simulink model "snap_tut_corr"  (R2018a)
settings: Solver=VariableStepDiscrete  StartTime=0.0  StopTime=100  RelTol=1e-3
undefined symbols (not defined in the file): Area, behavioral, Behavioral, Bit, Both, BRAM, bram, c, core, d, Falling, getfield, hamming, hex2dec, led, Location, logic, Lower, Minimum_Area, out, quant0, quant1, quant2, reg, repmat, Rising, ROACH, ROACH2, SNAP, Speed, sync_in, Truncate, Unsigned, Upper, Width, Wrap, xc7k160t
libraries: xbsIndex_r4 x17901, casper_library_misc x29, xbsReplacements_r4 x20, casper_library_delays x14, xps_library x5
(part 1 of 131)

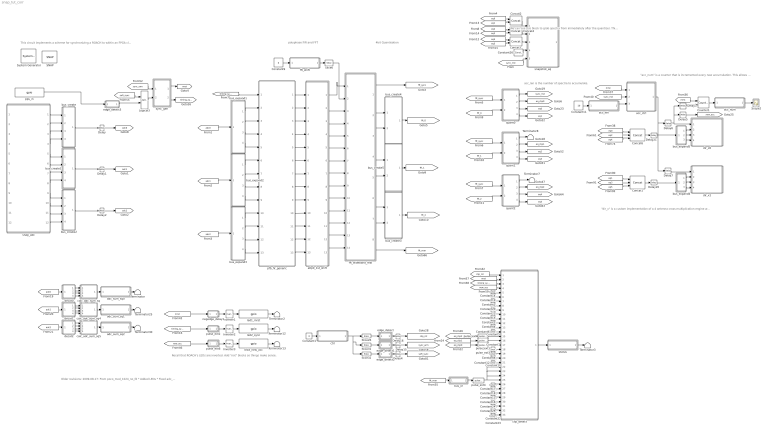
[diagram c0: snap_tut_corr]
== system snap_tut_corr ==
  note: We can use this block to grab spectra from immediately after the quantizer. This will help determine what the correct quantizer EQ coefficients are
  note: This circuit implements a scheme for synchronizing a ROACH to within an FPGA clock of a second boundary using an external 1 pulse-per-second device. * A sync_arm command will cause the sync_gen to stop issuing sync pulses. * It will then ignore the next input trigger (1PPS), while sync is flushed through the DSP pipeline. * It will then lock onto the next trigger (1PPS) and issue syncs thereafter every sync_period clocks. * Need a multiple of (pfb_fir taps*LCM(FFT reorder orders) *fft bins/parallel inputs =) (4 * LCM(2,2,2,9) * 1024 / 4) = 18432) for sync_period for simulation * Trigger off either ADC's 1PPS inputs
  note: polyphase FIR and FFT
  note: "dir_x" is a custom implementation of a 4 antenna cross-multiplication engine which uses a multiplication core for each auto- and cross-correlation. Some BRAM space is wasted in this 1024 channel compile because the minimum shared BRAM size is 2048.
  note: "acc_num" is a counter that is incremented every new accumulation. This allows a computer to know when a new accumulation is available.
  note: acc_len is the number of spectra to accumulate.
  note: 4bit Quantisation
  note: Recall that ROACH's LEDs are inverted. Add "not" blocks so things make sense.
  note: Older revisions: 2009-08-17: From poco_mod_1024_no_fd * Added LEDs * Fixed adc_levels 2009-08-18: r310 * Changed dir_x numbering scheme * mods to adc_levels * added status register * EQ now per channel 2010-08-14: r313 * adc_sum_sq copied from kat-7 feng 2010-08-16: r314: * tidyup for workshop 2012-05-09: r315: * replaced FFT and PFB_FIR with new library ones * software register replacement 2013-08-16: r316: Updated for workshop. Ran DM's update_casper_blocks script Replaced all cross-multiplication modules with dsp48_cmults Replaced deprecated snap blocks Replaced FFT and FIR blocks for combined multi-input blocks.
  " System Generator" : xbsIndex_r4/ System Generator  Tag=genX  xilinxfamily=kintex7  part=xc7k160t  speed=-2  package=ffg676  synthesis_tool=XST  clock_wrapper=Clock Enables  directory=/home/jackh/mergeymcmergeface/tutorials_devel2/vivado/snap/tut_corr/snap_tut_corr/sysgen  proj_type=Vivado  Synth_file=Vivado Synthesis Defaults  Impl_file=Vivado Implementation Defaults  testbench=off  simulink_period=1  sysclk_period=5  dcm_input_clock_period=10  incr_netlist=off  trim_vbits=Everywhere in SubSystem  dbl_ovrd=According to Block Masks  core_generation=According to Block Masks  run_coregen=off  deprecated_control=off  eval_field=0  block_type=sysgen
  Concat1 : xbsIndex_r4/Concat  num_inputs=3  dbl_ovrd=off  block_type=concat
  Concat2 : xbsIndex_r4/Concat  num_inputs=2  dbl_ovrd=off  block_type=concat
  Concat3 : xbsIndex_r4/Concat  num_inputs=2  dbl_ovrd=off  block_type=concat
  Concat4 : xbsIndex_r4/Concat  num_inputs=2  dbl_ovrd=off  block_type=concat
  Concat6 : xbsIndex_r4/Concat  num_inputs=3  dbl_ovrd=off  block_type=concat
  Constant1 : Constant  Value=0
  Constant{2..8,10,12..25} (22 alike) : xbsIndex_r4/Constant  const=0  gui_display_data_type=Fixed-point  arith_type=Boolean  n_bits=1  bin_pt=0  preci_type=Single  exp_width=8  frac_width=24  explicit_period=on  period=1  equ=P=C  opselect=C  inp2=PCIN>>17  opr=+  inp1=P  carry=CIN  dbl_ovrd=off  block_type=constant
  Constant11 : Constant  Value=10
  Constant26 : xbsIndex_r4/Constant  const=0  gui_display_data_type=Boolean  arith_type=Boolean  n_bits=32  bin_pt=0  preci_type=Single  exp_width=8  frac_width=24  explicit_period=on  period=1  equ=P=C  opselect=C  inp2=PCIN>>17  opr=+  inp1=P  carry=CIN  dbl_ovrd=off  block_type=constant
  Constant9 : Constant  Value=0
  Counter1 : xbsIndex_r4/Counter  cnt_type=Free Running  cnt_to=Inf  operation=Up  start_count=0  cnt_by_val=1  arith_type=Unsigned  n_bits=32  bin_pt=0  load_pin=off  rst=on  en=on  explicit_period=off  period=1  use_behavioral_HDL=off  implementation=Fabric  use_rpm=on  dbl_ovrd=off  block_type=counter
  Delay{,1..2,4..7,15..16} (9 alike) : xbsIndex_r4/Delay  rst=off  infoeditControl=Selection of Reset will increase slice count due to use of real FFs and instead of SRLs  en=off  latency=1  reg_retiming=on  dbl_ovrd=off  block_type=delay
  Delay20 : xbsIndex_r4/Delay  rst=off  infoeditControl=Selection of Reset will increase slice count due to use of real FFs and instead of SRLs  en=off  latency=2  reg_retiming=on  dbl_ovrd=off  block_type=delay
  Delay21 : xbsIndex_r4/Delay  rst=off  infoeditControl=Selection of Reset will increase slice count due to use of real FFs and instead of SRLs  en=off  latency=2  reg_retiming=on  dbl_ovrd=off  block_type=delay
  Delay3 : xbsIndex_r4/Delay  rst=off  infoeditControl=Selection of Reset will increase slice count due to use of real FFs and instead of SRLs  en=off  latency=2  reg_retiming=on  dbl_ovrd=off  block_type=delay
  Inverter1 : xbsIndex_r4/Inverter  en=off  latency=1  dbl_ovrd=off  block_type=inv
  Inverter2 : xbsIndex_r4/Inverter  en=off  latency=1  dbl_ovrd=off  block_type=inv
  Inverter3 : xbsIndex_r4/Inverter  en=off  latency=1  dbl_ovrd=off  block_type=inv
  Logical3 : xbsIndex_r4/Logical  logical_function=OR  inputs=2  en=off  latency=0  precision=Full  arith_type=Unsigned  n_bits=16  bin_pt=0  align_bp=on  dbl_ovrd=off  block_type=logical
  SNAP : xps_library/Platforms/SNAP  Tag=xps:xsg  hw_sys=SNAP:xc7k160t  clk_src=adc0_clk  clk_rate=200  use_microblaze=off  sample_period=1  synthesis_tool=XST
  Scope2 : Scope
  Slice26 : xbsIndex_r4/Slice  nbits=1  boolean_output=on  mode=Lower Bit Location + Width  bit1=0  base1=MSB of Input  bit0=16  base0=LSB of Input  dbl_ovrd=off  block_type=slice
  Slice31 : xbsIndex_r4/Slice  nbits=1  boolean_output=on  mode=Lower Bit Location + Width  bit1=0  base1=MSB of Input  bit0=17  base0=LSB of Input  dbl_ovrd=off  block_type=slice
  Slice32 : xbsIndex_r4/Slice  nbits=1  boolean_output=on  mode=Lower Bit Location + Width  bit1=0  base1=MSB of Input  bit0=18  base0=LSB of Input  dbl_ovrd=off  block_type=slice
  Slice6 : xbsIndex_r4/Slice  nbits=11  boolean_output=off  mode=Lower Bit Location + Width  bit1=0  base1=MSB of Input  bit0=0  base0=LSB of Input  dbl_ovrd=off  block_type=slice
  Terminator{,2..3,7..8,12..13,25,30} (9 alike) : Terminator
  a0p0_1st_shift : Subsystem  mask{shift=1, latency=0}
      mask prompts: shift "Number bits to shift right by"; latency "Shift latency"
  acc_ctrl : Subsystem  mask{chan_bits=9}
      mask prompts: chan_bits "Vector length (2^?)"
  acc_len : Subsystem  Tag=xps:sw_reg  AncestorBlock=xps_library/Memory/software_register  mask(swreg){io_dir=From Processor, io_delay=0, init_val=0, sample_period=1, names=reg, bitwidths=32, bin_pts=0, arith_types=0, sim_port=on, show_format=on}
      mask prompts: io_dir "I/O direction"; io_delay "I/O delay"; init_val "Initial Value"; sample_period "Sample period"; names "Bitfield names [msb...lsb]"; bitwidths "Bitfield widths"; bin_pts "Bitfield binary pts"; arith_types "Bitfield types, ufix=0, fix=1, bool=2"; sim_port "Provide sim input/output?"; show_format "Print format string?"
      mask help: A 32-bit software-accessible register. Can be divided into bitfields of varying widths and types using the fields in the block mask.
      mask init:
      | swreg_init(gcb)
  acc_num : Subsystem  Tag=xps:sw_reg  AncestorBlock=xps_library/Memory/software_register  mask(swreg){io_dir=To Processor, io_delay=0, init_val=0, sample_period=1, names=reg, bitwidths=32, bin_pts=0, arith_types=0, sim_port=on, show_format=on}
      mask prompts: io_dir "I/O direction"; io_delay "I/O delay"; init_val "Initial Value"; sample_period "Sample period"; names "Bitfield names [msb...lsb]"; bitwidths "Bitfield widths"; bin_pts "Bitfield binary pts"; arith_types "Bitfield types, ufix=0, fix=1, bool=2"; sim_port "Provide sim input/output?"; show_format "Print format string?"
      mask help: A 32-bit software-accessible register. Can be divided into bitfields of varying widths and types using the fields in the block mask.
      mask init:
      | swreg_init(gcb)
  adc_sum_sq0 : Subsystem  Tag=xps:sw_reg  AncestorBlock=xps_library/Memory/software_register  mask(swreg){io_dir=To Processor, io_delay=0, init_val=0, sample_period=1, names=reg, bitwidths=32, bin_pts=0, arith_types=0, sim_port=on, show_format=on}
      mask prompts: io_dir "I/O direction"; io_delay "I/O delay"; init_val "Initial Value"; sample_period "Sample period"; names "Bitfield names [msb...lsb]"; bitwidths "Bitfield widths"; bin_pts "Bitfield binary pts"; arith_types "Bitfield types, ufix=0, fix=1, bool=2"; sim_port "Provide sim input/output?"; show_format "Print format string?"
      mask help: A 32-bit software-accessible register. Can be divided into bitfields of varying widths and types using the fields in the block mask.
      mask init:
      | swreg_init(gcb)
  adc_sum_sq1 : Subsystem  Tag=xps:sw_reg  AncestorBlock=xps_library/Memory/software_register  mask(swreg){io_dir=To Processor, io_delay=0, init_val=0, sample_period=1, names=reg, bitwidths=32, bin_pts=0, arith_types=0, sim_port=on, show_format=on}
      mask prompts: io_dir "I/O direction"; io_delay "I/O delay"; init_val "Initial Value"; sample_period "Sample period"; names "Bitfield names [msb...lsb]"; bitwidths "Bitfield widths"; bin_pts "Bitfield binary pts"; arith_types "Bitfield types, ufix=0, fix=1, bool=2"; sim_port "Provide sim input/output?"; show_format "Print format string?"
      mask help: A 32-bit software-accessible register. Can be divided into bitfields of varying widths and types using the fields in the block mask.
      mask init:
      | swreg_init(gcb)
  adc_sum_sq2 : Subsystem  Tag=xps:sw_reg  AncestorBlock=xps_library/Memory/software_register  mask(swreg){io_dir=To Processor, io_delay=0, init_val=0, sample_period=1, names=reg, bitwidths=32, bin_pts=0, arith_types=0, sim_port=on, show_format=on}
      mask prompts: io_dir "I/O direction"; io_delay "I/O delay"; init_val "Initial Value"; sample_period "Sample period"; names "Bitfield names [msb...lsb]"; bitwidths "Bitfield widths"; bin_pts "Bitfield binary pts"; arith_types "Bitfield types, ufix=0, fix=1, bool=2"; sim_port "Provide sim input/output?"; show_format "Print format string?"
      mask help: A 32-bit software-accessible register. Can be divided into bitfields of varying widths and types using the fields in the block mask.
      mask init:
      | swreg_init(gcb)
  bus_create : Subsystem  AncestorBlock=casper_library_flow_control/bus_create  mask(bus_create){inputNum=4}
      mask prompts: inputNum "Number of inputs:"
      mask init:
      | bus_create_init(gcb,...
      |     'inputNum', inputNum);
  bus_create1 : Subsystem  AncestorBlock=casper_library_flow_control/bus_create  mask(bus_create){inputNum=4}
      mask prompts: inputNum "Number of inputs:"
      mask init:
      | bus_create_init(gcb,...
      |     'inputNum', inputNum);
  bus_create2 : Subsystem  AncestorBlock=casper_library_flow_control/bus_create  mask(bus_create){inputNum=4}
      mask prompts: inputNum "Number of inputs:"
      mask init:
      | bus_create_init(gcb,...
      |     'inputNum', inputNum);
  bus_create3 : Subsystem  AncestorBlock=casper_library_flow_control/bus_create  mask(bus_create){inputNum=2}
      mask prompts: inputNum "Number of inputs:"
      mask init:
      | bus_create_init(gcb,...
      |     'inputNum', inputNum);
  bus_create4 : Subsystem  AncestorBlock=casper_library_flow_control/bus_create  mask(bus_create){inputNum=2}
      mask prompts: inputNum "Number of inputs:"
      mask init:
      | bus_create_init(gcb,...
      |     'inputNum', inputNum);
  bus_create5 : Subsystem  AncestorBlock=casper_library_flow_control/bus_create  mask(bus_create){inputNum=2}
      mask prompts: inputNum "Number of inputs:"
      mask init:
      | bus_create_init(gcb,...
      |     'inputNum', inputNum);
  bus_expand1 : Subsystem  AncestorBlock=casper_library_flow_control/bus_expand  mask(bus_expand){mode=divisions of equal size, outputNum=4, outputWidth=8, outputBinaryPt=7, outputArithmeticType=1, show_format=off, outputToWorkspace=off, variablePrefix=out, outputToModelAsWell=on}
      mask prompts: outputNum "Number of outputs:"; outputWidth "Output width:"; outputBinaryPt "Output binary point position:"; outputArithmeticType "Output arithmetic type (ufix=0, fix=1, bool=2):"; show_format "Print format string?"; outputToWorkspace "Output to workspace?"; variablePrefix "Variable name prefix:"; outputToModelAsWell "Output to model as well?"
      mask help: Expands a 'bus' made using a bus_create or Xilinx concat block. The input will be divided into the specified number of outputs with the specified arithmetic types. Divisions are made from most significant bit.
      mask init:
      | bus_expand_init(gcb,...
      |     'mode', mode, ...
      |     'outputNum', outputNum, ...
      |     'outputWidth', outputWidth, ...
      |     'outputBinaryPt', outputBinaryPt, ...
      |     'outputArithmeticType', outputArithmeticType, ...
      |     'show_format', show_format, ...
      |     'outputToWorkspace', outputToWorkspace, ...
      |     'variablePrefix', variablePrefix, ...
      |     'outputToModelAsWell', outputToModelAsWell);
  bus_expand2 : Subsystem  AncestorBlock=casper_library_flow_control/bus_expand  mask(bus_expand){mode=divisions of equal size, outputNum=4, outputWidth=8, outputBinaryPt=7, outputArithmeticType=1, show_format=off, outputToWorkspace=off, variablePrefix=out, outputToModelAsWell=on}
      mask prompts: outputNum "Number of outputs:"; outputWidth "Output width:"; outputBinaryPt "Output binary point position:"; outputArithmeticType "Output arithmetic type (ufix=0, fix=1, bool=2):"; show_format "Print format string?"; outputToWorkspace "Output to workspace?"; variablePrefix "Variable name prefix:"; outputToModelAsWell "Output to model as well?"
      mask help: Expands a 'bus' made using a bus_create or Xilinx concat block. The input will be divided into the specified number of outputs with the specified arithmetic types. Divisions are made from most significant bit.
      mask init:
      | bus_expand_init(gcb,...
      |     'mode', mode, ...
      |     'outputNum', outputNum, ...
      |     'outputWidth', outputWidth, ...
      |     'outputBinaryPt', outputBinaryPt, ...
      |     'outputArithmeticType', outputArithmeticType, ...
      |     'show_format', show_format, ...
      |     'outputToWorkspace', outputToWorkspace, ...
      |     'variablePrefix', variablePrefix, ...
      |     'outputToModelAsWell', outputToModelAsWell);
  bus_expand3 : Subsystem  AncestorBlock=casper_library_flow_control/bus_expand  mask(bus_expand){mode=divisions of equal size, outputNum=4, outputWidth=8, outputBinaryPt=7, outputArithmeticType=1, show_format=off, outputToWorkspace=off, variablePrefix=out, outputToModelAsWell=on}
      mask prompts: outputNum "Number of outputs:"; outputWidth "Output width:"; outputBinaryPt "Output binary point position:"; outputArithmeticType "Output arithmetic type (ufix=0, fix=1, bool=2):"; show_format "Print format string?"; outputToWorkspace "Output to workspace?"; variablePrefix "Variable name prefix:"; outputToModelAsWell "Output to model as well?"
      mask help: Expands a 'bus' made using a bus_create or Xilinx concat block. The input will be divided into the specified number of outputs with the specified arithmetic types. Divisions are made from most significant bit.
      mask init:
      | bus_expand_init(gcb,...
      |     'mode', mode, ...
      |     'outputNum', outputNum, ...
      |     'outputWidth', outputWidth, ...
      |     'outputBinaryPt', outputBinaryPt, ...
      |     'outputArithmeticType', outputArithmeticType, ...
      |     'show_format', show_format, ...
      |     'outputToWorkspace', outputToWorkspace, ...
      |     'variablePrefix', variablePrefix, ...
      |     'outputToModelAsWell', outputToModelAsWell);
  bus_expand4 : Subsystem  AncestorBlock=casper_library_flow_control/bus_expand  mask(bus_expand){mode=divisions of equal size, outputNum=3, outputWidth=8, outputBinaryPt=0, outputArithmeticType=0, show_format=off, outputToWorkspace=off, variablePrefix=out, outputToModelAsWell=on}
      mask prompts: outputNum "Number of outputs:"; outputWidth "Output width:"; outputBinaryPt "Output binary point position:"; outputArithmeticType "Output arithmetic type (ufix=0, fix=1, bool=2):"; show_format "Print format string?"; outputToWorkspace "Output to workspace?"; variablePrefix "Variable name prefix:"; outputToModelAsWell "Output to model as well?"
      mask help: Expands a 'bus' made using a bus_create or Xilinx concat block. The input will be divided into the specified number of outputs with the specified arithmetic types. Divisions are made from most significant bit.
      mask init:
      | bus_expand_init(gcb,...
      |     'mode', mode, ...
      |     'outputNum', outputNum, ...
      |     'outputWidth', outputWidth, ...
      |     'outputBinaryPt', outputBinaryPt, ...
      |     'outputArithmeticType', outputArithmeticType, ...
      |     'show_format', show_format, ...
      |     'outputToWorkspace', outputToWorkspace, ...
      |     'variablePrefix', variablePrefix, ...
      |     'outputToModelAsWell', outputToModelAsWell);
  bus_expand5 : Subsystem  AncestorBlock=casper_library_flow_control/bus_expand  mask(bus_expand){mode=divisions of equal size, outputNum=3, outputWidth=8, outputBinaryPt=0, outputArithmeticType=0, show_format=off, outputToWorkspace=off, variablePrefix=out, outputToModelAsWell=on}
      mask prompts: outputNum "Number of outputs:"; outputWidth "Output width:"; outputBinaryPt "Output binary point position:"; outputArithmeticType "Output arithmetic type (ufix=0, fix=1, bool=2):"; show_format "Print format string?"; outputToWorkspace "Output to workspace?"; variablePrefix "Variable name prefix:"; outputToModelAsWell "Output to model as well?"
      mask help: Expands a 'bus' made using a bus_create or Xilinx concat block. The input will be divided into the specified number of outputs with the specified arithmetic types. Divisions are made from most significant bit.
      mask init:
      | bus_expand_init(gcb,...
      |     'mode', mode, ...
      |     'outputNum', outputNum, ...
      |     'outputWidth', outputWidth, ...
      |     'outputBinaryPt', outputBinaryPt, ...
      |     'outputArithmeticType', outputArithmeticType, ...
      |     'show_format', show_format, ...
      |     'outputToWorkspace', outputToWorkspace, ...
      |     'variablePrefix', variablePrefix, ...
      |     'outputToModelAsWell', outputToModelAsWell);
  bus_or : Subsystem
  calc_adc_sum_sq : Subsystem
  calc_adc_sum_sq4 : Subsystem
  calc_adc_sum_sq5 : Subsystem
  clip_detect : Subsystem
  ctrl : Subsystem  Tag=xps:sw_reg  AncestorBlock=xps_library/Memory/software_register  mask(swreg){io_dir=From Processor, io_delay=0, init_val=0, sample_period=1, names=reg, bitwidths=32, bin_pts=0, arith_types=0, sim_port=on, show_format=on}
      mask prompts: io_dir "I/O direction"; io_delay "I/O delay"; init_val "Initial Value"; sample_period "Sample period"; names "Bitfield names [msb...lsb]"; bitwidths "Bitfield widths"; bin_pts "Bitfield binary pts"; arith_types "Bitfield types, ufix=0, fix=1, bool=2"; sim_port "Provide sim input/output?"; show_format "Print format string?"
      mask help: A 32-bit software-accessible register. Can be divided into bitfields of varying widths and types using the fields in the block mask.
      mask init:
      | swreg_init(gcb)
  decat0 : Subsystem
  decat1 : Subsystem
  decat2 : Subsystem
  dir_x0 : Subsystem  mask{n_chans=512}
      mask prompts: n_chans "Number of Channels"
  dir_x1 : Subsystem  mask{n_chans=512}
      mask prompts: n_chans "Number of Channels"
  edge_detect : Subsystem  AncestorBlock=casper_library_misc/edge_detect  mask(edge_detect){edge=Rising, polarity=Active High, x_in=[0 0.08 0.08 0.16 0.16 0.24 0.24 0.32 0.32 0.4], y_in=[-1 -1  1  1  1  1  1  1  1  1], x_out=[0.6 0.68 0.68 0.76 0.76 0.84 0.84 0.92 0.92 1], y_out=[-1 -1  1  1 -1 -1 -1 -1 -1 -1]}
      mask prompts: edge "Edge Type"; polarity "Output Polarity"; x_in "Input X Positions"; y_in "Input Y Positions"; x_out "Output X Positions"; y_out "Output Y Positions"
      mask help: Output is active for one-cycle after each edge of the specified type (i.e. rising, falling or both).
      mask init:
      | edge_detect_init(gcb,...
      |     'edge',edge,...
      |     'polarity',polarity,...
      |     'x_in',x_in,...
      |     'x_out',x_out,...
      |     'y_in',y_in,...
      |     'y_out',y_out);
      | 
      | x_in_num=str2num(getfield(getfield(get_param(gcb,'UserData'),'parameters'),'x_in'));
      | x_out_num=str2num(getfield(getfield(get_param(gcb,'UserData'),'parameters'),'x_out'));
      | y_in_num=str2num(getfield(getfield(get_param(gcb,'UserData'),'parameters'),'y_in'));
      | y_out_num=str2num(getfield(getfield(get_param(gcb,'UserData'),'parameters'),'y_out'));
  edge_detect1 : Subsystem  AncestorBlock=casper_library_misc/edge_detect  mask(edge_detect){edge=Rising, polarity=Active High, x_in=[0 0.08 0.08 0.16 0.16 0.24 0.24 0.32 0.32 0.4], y_in=[-1 -1  1  1  1  1  1  1  1  1], x_out=[0.6 0.68 0.68 0.76 0.76 0.84 0.84 0.92 0.92 1], y_out=[-1 -1  1  1 -1 -1 -1 -1 -1 -1]}
      mask prompts: edge "Edge Type"; polarity "Output Polarity"; x_in "Input X Positions"; y_in "Input Y Positions"; x_out "Output X Positions"; y_out "Output Y Positions"
      mask help: Output is active for one-cycle after each edge of the specified type (i.e. rising, falling or both).
      mask init:
      | edge_detect_init(gcb,...
      |     'edge',edge,...
      |     'polarity',polarity,...
      |     'x_in',x_in,...
      |     'x_out',x_out,...
      |     'y_in',y_in,...
      |     'y_out',y_out);
      | 
      | x_in_num=str2num(getfield(getfield(get_param(gcb,'UserData'),'parameters'),'x_in'));
      | x_out_num=str2num(getfield(getfield(get_param(gcb,'UserData'),'parameters'),'x_out'));
      | y_in_num=str2num(getfield(getfield(get_param(gcb,'UserData'),'parameters'),'y_in'));
      | y_out_num=str2num(getfield(getfield(get_param(gcb,'UserData'),'parameters'),'y_out'));
  edge_detect2 : Subsystem  AncestorBlock=casper_library_misc/edge_detect  mask(edge_detect){edge=Rising, polarity=Active High, x_in=[0 0.08 0.08 0.16 0.16 0.24 0.24 0.32 0.32 0.4], y_in=[-1 -1  1  1  1  1  1  1  1  1], x_out=[0.6 0.68 0.68 0.76 0.76 0.84 0.84 0.92 0.92 1], y_out=[-1 -1  1  1 -1 -1 -1 -1 -1 -1]}
      mask prompts: edge "Edge Type"; polarity "Output Polarity"; x_in "Input X Positions"; y_in "Input Y Positions"; x_out "Output X Positions"; y_out "Output Y Positions"
      mask help: Output is active for one-cycle after each edge of the specified type (i.e. rising, falling or both).
      mask init:
      | edge_detect_init(gcb,...
      |     'edge',edge,...
      |     'polarity',polarity,...
      |     'x_in',x_in,...
      |     'x_out',x_out,...
      |     'y_in',y_in,...
      |     'y_out',y_out);
      | 
      | x_in_num=str2num(getfield(getfield(get_param(gcb,'UserData'),'parameters'),'x_in'));
      | x_out_num=str2num(getfield(getfield(get_param(gcb,'UserData'),'parameters'),'x_out'));
      | y_in_num=str2num(getfield(getfield(get_param(gcb,'UserData'),'parameters'),'y_in'));
      | y_out_num=str2num(getfield(getfield(get_param(gcb,'UserData'),'parameters'),'y_out'));
  edge_detect3 : Subsystem  AncestorBlock=casper_library_misc/edge_detect  mask(edge_detect){edge=Rising, polarity=Active High, x_in=[0 0.08 0.08 0.16 0.16 0.24 0.24 0.32 0.32 0.4], y_in=[-1 -1  1  1  1  1  1  1  1  1], x_out=[0.6 0.68 0.68 0.76 0.76 0.84 0.84 0.92 0.92 1], y_out=[-1 -1  1  1 -1 -1 -1 -1 -1 -1]}
      mask prompts: edge "Edge Type"; polarity "Output Polarity"; x_in "Input X Positions"; y_in "Input Y Positions"; x_out "Output X Positions"; y_out "Output Y Positions"
      mask help: Output is active for one-cycle after each edge of the specified type (i.e. rising, falling or both).
      mask init:
      | edge_detect_init(gcb,...
      |     'edge',edge,...
      |     'polarity',polarity,...
      |     'x_in',x_in,...
      |     'x_out',x_out,...
      |     'y_in',y_in,...
      |     'y_out',y_out);
      | 
      | x_in_num=str2num(getfield(getfield(get_param(gcb,'UserData'),'parameters'),'x_in'));
      | x_out_num=str2num(getfield(getfield(get_param(gcb,'UserData'),'parameters'),'x_out'));
      | y_in_num=str2num(getfield(getfield(get_param(gcb,'UserData'),'parameters'),'y_in'));
      | y_out_num=str2num(getfield(getfield(get_param(gcb,'UserData'),'parameters'),'y_out'));
  fft_shift : Subsystem  Tag=xps:sw_reg  AncestorBlock=xps_library/Memory/software_register  mask(swreg){io_dir=From Processor, io_delay=0, init_val=0, sample_period=1, names=reg, bitwidths=32, bin_pts=0, arith_types=0, sim_port=on, show_format=on}
      mask prompts: io_dir "I/O direction"; io_delay "I/O delay"; init_val "Initial Value"; sample_period "Sample period"; names "Bitfield names [msb...lsb]"; bitwidths "Bitfield widths"; bin_pts "Bitfield binary pts"; arith_types "Bitfield types, ufix=0, fix=1, bool=2"; sim_port "Provide sim input/output?"; show_format "Print format string?"
      mask help: A 32-bit software-accessible register. Can be divided into bitfields of varying widths and types using the fields in the block mask.
      mask init:
      | swreg_init(gcb)
  fft_wideband_real : Subsystem  Tag=casper:fft_wideband_real  AncestorBlock=casper_library_ffts/fft_wideband_real  mask(fft_wideband_real){n_streams=3, FFTSize=11, n_inputs=2, input_bit_width=18, bin_pt_in=17, coeff_bit_width=18, unscramble=on, async=off, floating_point=off, float_type=single, exp_width=8, frac_width=24, add_latency=1, mult_latency=3, bram_latency=3, conv_latency=1, input_latency=0, biplex_direct_latency=0, add_pipe_latency=0, mult_pipe_latency=0, quantization=Round  (unbiased: Even Values), overflow=Wrap, delays_bit_limit=7, coeffs_bit_limit=7, coeff_sharing=off, coeff_decimation=off, coeff_generation=off, cal_bits=1, n_bits_rotation=25, mult_spec=2, max_fanout=8, bitgrowth=off, max_bits=19, hardcode_shifts=off, shift_schedule=[], dsp48_adders=off}
      mask prompts: n_streams "Number simultaneous streams"; FFTSize "Size of FFT: (2^? pts)"; n_inputs "Number of Simultaneous Inputs: (2^?)"; input_bit_width "Input Bit Width"; bin_pt_in "Input binary point"; coeff_bit_width "Coefficient Bit Width"; unscramble "Unscramble output (ie, put channels in canonical order)"; async "Asynchronous operation"; floating_point "floating point"; float_type "float type"; exp_width "exponent width"; frac_width "fraction width"; add_latency "Add Latency"; mult_latency "Mult Latency"; bram_latency "BRAM Latency"; conv_latency "Convert Latency"; input_latency "Input Latency"; biplex_direct_latency "Latency between biplexes and fft_direct"; add_pipe_latency "Add Interface Pipeline Latency"; mult_pipe_latency "CMult Pipeline Latency"; quantization "Quantization Behavior"; overflow "Overflow Behavior"; delays_bit_limit "Number bits above which to store stage's delays in BRAM (2^? bits)"; coeffs_bit_limit "Number bits above which to store stage's coefficients in BRAM (2^? bits)"; coeff_sharing "BRAM sharing in coeff storage"; coeff_decimation "Store a fraction of coeff factors where useful"; coeff_generation "Generate coeffs with multipliers where useful"; cal_bits "Number calibration locations when generating coeffs (2^?)"; n_bits_rotation "Feedback rotation vector resolution"; mult_spec "Multiplier impl. (0=core, 1=embedded, 2=behavioural) (left=1st stage, or just one value)"; max_fanout "Maximum fanout"; bitgrowth "Bitgrowth instead of shifting"; max_bits "Max bits to grow to"; hardcode_shifts "Hardcode shift schedule"; shift_schedule "Shift schedule"; dsp48_adders "DSP48 adders in butterfly"
      mask help: A real-sampled wideband FFT.
      mask init:
      | fft_wideband_real_init(gcb, ...
      |     'n_streams', n_streams, ...
      |     'FFTSize', FFTSize, ...
      |     'n_inputs', n_inputs, ...
      |     'input_bit_width', input_bit_width, ...
      |     'bin_pt_in', bin_pt_in, ...
      |     'coeff_bit_width', coeff_bit_width, ...
      |     'floating_point', floating_point, ...
      |     'float_type', float_type, ...
      |     'exp_width', exp_width, ...
      |     'frac_width', frac_width, ...
      |     'unscramble', unscramble, ...
      |     'async', async, ...
      |     'add_latency', add_latency, ...
      |     'mult_latency', mult_latency, ...
      |     'bram_latency', bram_latency, ...
      |     'conv_latency', conv_latency, ...
      |     'input_latency', input_latency, ...
      |     'add_pipe_latency', add_pipe_latency, ...
      |     'mult_pipe_latency', mult_pipe_latency, ...
      |     'biplex_direct_latency', biplex_direct_latency, ...
      |     'quantization', quantization, ...
      |     'overflow', overflow, ...
      |     'delays_bit_limit', delays_bit_limit, ...
      |     'coeffs_bit_limit', coeffs_bit_limit, ...
      |     'coeff_sharing', coeff_sharing, ...
      |     'coeff_decimation', coeff_decimation, ...
      |     'coeff_generation', coeff_generation, ...
      |     'cal_bits', cal_bits, ...
      |     'n_bits_rotation', n_bits_rotation, ...
      |     'max_fanout', max_fanout, ...   
      |     'mult_spec', mult_spec, ...
      |     'bitgrowth', bitgrowth, ...
      |     'max_bits', max_bits, ...
      |     'hardcode_shifts', hardcode_shifts, ...
      |     'shift_schedule', shift_schedule, ...
      |     'dsp48_adders', dsp48_adders);
  led1_mrst : xps_library/IO/gpio  Tag=xps:gpio  io_group_params_forwarded=on  io_group=ROACH:led  io_group_real=led  io_group_custom=0  io_dir=out  arith_type=Boolean  bitwidth=1  bin_pt=0  bit_index=1  sample_period=1  use_single_ended=off  use_ddr=off  reg_iob=on  reg_clk_phase=0  termination=None
  led2_sync : xps_library/IO/gpio  Tag=xps:gpio  io_group_params_forwarded=on  io_group=ROACH:led  io_group_real=led  io_group_custom=0  io_dir=out  arith_type=Boolean  bitwidth=1  bin_pt=0  bit_index=2  sample_period=1  use_single_ended=off  use_ddr=off  reg_iob=on  reg_clk_phase=0  termination=None
  led3_new_acc : xps_library/IO/gpio  Tag=xps:gpio  io_group_params_forwarded=on  io_group=ROACH:led  io_group_real=led  io_group_custom=0  io_dir=out  arith_type=Unsigned  bitwidth=1  bin_pt=0  bit_index=3  sample_period=1  use_single_ended=off  use_ddr=off  reg_iob=on  reg_clk_phase=0  termination=None
  negedge_delay1 : Subsystem  AncestorBlock=casper_library_misc/negedge_delay  mask(negedge_delay){pulse_len=2^24}
      mask prompts: pulse_len "Length of Pulse"
      mask help: Extends a boolean signal to be high for the specified number of clocks after the last high input (negative edge). Minimum length is 3.
      mask init:
      | bits = ceil(log2(pulse_len+1));
      | 
      | if pulse_len < 3,
      |     errordlg('Minimum length is 3.');
      | end
  pfb_fir_generic : Subsystem  Tag=casper:pfb_fir_generic  AncestorBlock=casper_library_pfbs/pfb_fir_generic  mask(pfb_fir_generic){n_streams=3, PFBSize=11, TotalTaps=4, n_inputs=2, BitWidthIn=8, BitWidthOut=18, CoeffBitWidth=18, complex=off, async=off, floating_point=off, float_type=single, frac_width=0, exp_width=0, WindowType=hamming, quantization=Round  (unbiased: Even Values), fwidth=1, coeffs_bram_optimization=Area, delays_bram_optimization=Area, add_latency=2, mult_latency=3, bram_latency=1, fan_latency=1, conv_latency=1, fixed_float_latency=0}
      mask prompts: n_streams "Number input streams?"; PFBSize "Size of PFB: (2^? pnts)"; TotalTaps "Total Number of Taps:"; n_inputs "Number of Simultaneous Inputs: (2^?)"; BitWidthIn "Input Bitwidth:"; BitWidthOut "Output Bitwidth:"; CoeffBitWidth "Coefficient Bitwidth:"; complex "Complex data inputs"; async "Asynchronous operation"; floating_point "floating point"; float_type "float type"; frac_width "fraction width"; exp_width "exponent width"; WindowType "Windowing Function:"; quantization "Quantization Behavior"; fwidth "Bin Width Scaling (normal=1)"; coeffs_bram_optimization "Coefficient BRAMs optimization"; delays_bram_optimization "Delay BRAMs optimization"; add_latency "Add Latency"; mult_latency "Mult Latency"; bram_latency "BRAM Latency"; fan_latency "Fanout Latency"; conv_latency "Convert latency"; fixed_float_latency "Fixed to float latency"
      mask init:
      | pfb_fir_generic_init(gcb, ...
      |     'n_streams', n_streams, ...
      |     'PFBSize', PFBSize, ...
      |     'TotalTaps', TotalTaps, ...
      |     'WindowType', WindowType, ...
      |     'n_inputs', n_inputs, ...
      |     'complex', complex, ...
      |     'BitWidthIn', BitWidthIn, ...
      |     'BitWidthOut', BitWidthOut, ...
      |     'CoeffBitWidth', CoeffBitWidth, ...
      |     'floating_point', floating_point, ...
      |     'float_type', float_type, ...
      |     'exp_width', exp_width, ...
      |     'frac_width', frac_width, ... 
      |     'fixed_float_latency', fixed_float_latency, ...
      |     'async', async, ...
      |     'add_latency', add_latency, ...
      |     'mult_latency', mult_latency, ...
      |     'bram_latency', bram_latency, ...
      |     'fan_latency', fan_latency, ...
      |     'conv_latency', conv_latency, ...
      |     'quantization', quantization, ...
      |     'fwidth', fwidth, ...
      |     'coeffs_bram_optimization', coeffs_bram_optimization, ...
      |     'delays_bram_optimization', delays_bram_optimization);
  pps_in : xps_library/IO/gpio  Tag=xps:gpio  io_group_params_forwarded=on  io_group=ROACH2:sync_in  io_group_real=sync_in  io_group_custom=0  io_dir=in  arith_type=Boolean  bitwidth=1  bin_pt=0  bit_index=0  sample_period=1  use_single_ended=off  use_ddr=off  reg_iob=off  reg_clk_phase=0  termination=None
  pulse_ext : casper_library_misc/pulse_ext  pulse_len=2^24
      link override Constant5: sg_icon_stat=70,32,0,1,white,blue,0,1cbef600,right,,[ ],[ ]  sg_mask_display="fprintf('','COMMENT: begin icon graphics'); patch([0 70 70 0 0 ],[0 0 32 32 0 ],[0.77 0.82 0.91 ]); plot([0 70 70 0 0 ],[0 0 32 32 0 ]); patch([26.1 31.88 35.88 39.88 43.88 35.88 30.1 26.1 ],[20.44 20.44 24.44 20.44 24.44 24.44 24.44 20.44 ],[1 1 1 ]); patch([30.1 35.88 31.88 26.1 30.1 ],[16.44 16.44 20.44 20.44 16.44 ],[0.931 0.946 0.973 ]); patch([26.1 31.88 35.88 30.1 26.1 ],[12.44 12.44 16.44 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"
  pulse_ext1 : casper_library_misc/pulse_ext  pulse_len=2^24
      link override Constant5: sg_icon_stat=70,32,0,1,white,blue,0,1cbef600,right,,[ ],[ ]  sg_mask_display="fprintf('','COMMENT: begin icon graphics'); patch([0 70 70 0 0 ],[0 0 32 32 0 ],[0.77 0.82 0.91 ]); plot([0 70 70 0 0 ],[0 0 32 32 0 ]); patch([26.1 31.88 35.88 39.88 43.88 35.88 30.1 26.1 ],[20.44 20.44 24.44 20.44 24.44 24.44 24.44 20.44 ],[1 1 1 ]); patch([30.1 35.88 31.88 26.1 30.1 ],[16.44 16.44 20.44 20.44 16.44 ],[0.931 0.946 0.973 ]); patch([26.1 31.88 35.88 30.1 26.1 ],[12.44 12.44 16.44 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"
  pulse_ext2 : Subsystem  mask{pulse_len=2^24}
      mask prompts: pulse_len "Length of Pulse"
      mask init:
      | bits = ceil(log2(pulse_len+1));
  pulse_ext3 : casper_library_misc/pulse_ext  pulse_len=2^24
      link override Constant5: sg_icon_stat=70,32,0,1,white,blue,0,1cbef600,right,,[ ],[ ]  sg_mask_display="fprintf('','COMMENT: begin icon graphics'); patch([0 70 70 0 0 ],[0 0 32 32 0 ],[0.77 0.82 0.91 ]); plot([0 70 70 0 0 ],[0 0 32 32 0 ]); patch([26.1 31.88 35.88 39.88 43.88 35.88 30.1 26.1 ],[20.44 20.44 24.44 20.44 24.44 24.44 24.44 20.44 ],[1 1 1 ]); patch([30.1 35.88 31.88 26.1 30.1 ],[16.44 16.44 20.44 20.44 16.44 ],[0.931 0.946 0.973 ]); patch([26.1 31.88 35.88 30.1 26.1 ],[12.44 12.44 16.44 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"
  pulse_ext4 : casper_library_misc/pulse_ext  pulse_len=2^24
      link override Constant5: sg_icon_stat=70,32,0,1,white,blue,0,1cbef600,right,,[ ],[ ]  sg_mask_display="fprintf('','COMMENT: begin icon graphics'); patch([0 70 70 0 0 ],[0 0 32 32 0 ],[0.77 0.82 0.91 ]); plot([0 70 70 0 0 ],[0 0 32 32 0 ]); patch([26.1 31.88 35.88 39.88 43.88 35.88 30.1 26.1 ],[20.44 20.44 24.44 20.44 24.44 24.44 24.44 20.44 ],[1 1 1 ]); patch([30.1 35.88 31.88 26.1 30.1 ],[16.44 16.44 20.44 20.44 16.44 ],[0.931 0.946 0.973 ]); patch([26.1 31.88 35.88 30.1 26.1 ],[12.44 12.44 16.44 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"
  pulse_ext6 : Subsystem  mask{pulse_len=2^24}
      mask prompts: pulse_len "Length of Pulse"
      mask init:
      | bits = ceil(log2(pulse_len+1));
  quant0 : Subsystem
  quant1 : Subsystem
  quant2 : Subsystem
  snap_adc : Subsystem  Tag=xps:snap_adc  AncestorBlock=xps_library/ADCs/snap_adc  mask(adc_snap){sample_rate=800, snap_inputs=3, adc_resolution=8}
      mask prompts: sample_rate "Sample rate (MHz)"; snap_inputs "Number of inputs per snap"; adc_resolution "Resolution of ADC (number of bit)"
      mask help: Interface to the 3 adc chips on the SNAP board. Please see Help for instructions on parameter settings
      mask init:
      | adc_snap_init(gcb);
  snapshot_eq : Subsystem  Tag=casper:bitsnap  AncestorBlock=casper_library_scopes/bitfield_snapshot  mask(bitsnap){io_names=[quant0 quant1 quant2], io_widths=[16 16 16], io_bps=[0 0 0], io_types=[0 0 0], show_format=on, snap_storage=bram, snap_dram_dimm=2, snap_dram_clock=250, snap_nsamples=10, snap_data_width=64, snap_offset=off, snap_circap=off, snap_value=off, snap_ext_arm=off, snap_ext_circ=off, snap_provide_outputs=on, snap_use_dsp48=on, snap_delay=0, extra_names=[c d], extra_widths=[30 2], extra_bps=[0 0], extra_types=[0 0]}
      mask prompts: io_names "Names [msb...lsb]"; io_widths "Bitwidths [msb...lsb]"; io_bps "Binary pts [msb...lsb]"; io_types "Data types [msb...lsb], ufix=0, fix=1, bool=2"; show_format "Print format string?"; snap_storage "Storage medium"; snap_dram_dimm "DRAM dimm"; snap_dram_clock "DRAM clock rate"; snap_nsamples "Number of Samples (2^?)"; snap_data_width "Data width"; snap_offset "Start delay support"; snap_circap "Circular capture support"; snap_value "Extra value capture support"; snap_ext_arm "External arm support"; snap_ext_circ "External circular capture support"; snap_provide_outputs "Provide outputs"; snap_use_dsp48 "Use DSP48s to implement counters"; snap_delay "Pre-snapshot delay"; extra_names "Names [msb...lsb]"; extra_widths "Widths [msb...lsb]"; extra_bps "Binary pts [msb...lsb]"; extra_types "Data types [msb...lsb], ufix=0, fix=1, bool=2"
      mask help: A wrapped snapshot block. Allows specification of inputs to a snapblock word so the toolflow can automatically set up the scope. See documentation for snapshot for explanation of parameters.
      mask init:
      | bitsnap_init(gcb);
  status : Subsystem  Tag=xps:sw_reg  AncestorBlock=xps_library/Memory/software_register  mask(swreg){io_dir=To Processor, io_delay=0, init_val=0, sample_period=1, names=reg, bitwidths=32, bin_pts=0, arith_types=0, sim_port=on, show_format=on}
      mask prompts: io_dir "I/O direction"; io_delay "I/O delay"; init_val "Initial Value"; sample_period "Sample period"; names "Bitfield names [msb...lsb]"; bitwidths "Bitfield widths"; bin_pts "Bitfield binary pts"; arith_types "Bitfield types, ufix=0, fix=1, bool=2"; sim_port "Provide sim input/output?"; show_format "Print format string?"
      mask help: A 32-bit software-accessible register. Can be divided into bitfields of varying widths and types using the fields in the block mask.
      mask init:
      | swreg_init(gcb)
  sync_gen : Subsystem  mask(sync_gen_hw){sync_period=184320000}
      mask prompts: sync_period "Sync Period"
      mask help: This circuit implements a scheme for synchronizing a design to within an FPGA clock of an external 1 pulse-per-second signal. * An arm pulse will cause the sync_gen to stop issuing sync pulses. * It will then ignore the next input trigger (1PPS), while sync is flushed through the DSP pipeline. * It will then lock onto the next trigger (1PPS) and issue syncs thereafter every sync_period clocks. * You will need a multiple of (pfb_fir taps*LCM(FFT reorder orders) *fft bins/parallel inputs). See the sync memo for further details.
      mask init:
      | sync_period_bits = ceil(log2(sync_period))
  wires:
  bus_create/1(bus_out) -> Delay/1
  sync_gen/1(mrst) -> [mrst]
  sync_gen/2(sync) -> [timing_sync]
  Logical3/1 -> sync_gen/2(pps)
  [soft_sync] -> Logical3/1
  Constant9/1 -> fft_shift/1(sim_1)
  fft_shift/1(in_reg) -> Slice6/1
  quant0/1(sync_out) -> [sync_rnd]
  quant0/3(dout0) -> [eq0]
  quant0/4(dout1) -> [eq1]
  Constant11/1 -> acc_len/1(sim_1)
  acc_len/1(in_reg) -> acc_ctrl/3(acc_len)
  Concat6/1 -> Delay21/1
  Counter1/1 -> acc_num/1(out_reg)
  acc_ctrl/1(new_acc) -> Delay6/1, Delay7/1
  [mrst] -> acc_ctrl/1(mrst)
  Delay5/1 -> [new_acc]
  [sync_rnd] -> acc_ctrl/2(sync)
  acc_num/1(sim_out) -> Scope2/1
  Delay3/1 -> Counter1/2
  [mrst] -> Counter1/1
  Delay6/1 -> dir_x0/1(new_acc), Delay3/1, Delay5/1
  [eq0] -> Concat6/1
  [eq2] -> Concat6/2
  [eq4] -> Concat6/3
  [eq1] -> Concat1/1
  [eq3] -> Concat1/2
  [eq5] -> Concat1/3
  Concat1/1 -> Delay20/1
  Delay7/1 -> dir_x1/1(new_acc)
  Constant1/1 -> ctrl/1(sim_1)
  ctrl/1(in_reg) -> Slice26/1, Slice31/1, Slice32/1
  [clip_rst] -> clip_detect/1(rst)
  Constant24/1 -> clip_detect/30(In_03)
  Constant25/1 -> clip_detect/31(In_02)
  Constant22/1 -> clip_detect/32(In_01)
  Constant23/1 -> clip_detect/33(in_lsb)
  Constant16/1 -> clip_detect/29(In_04)
  Constant17/1 -> clip_detect/26(In_07)
  Constant18/1 -> clip_detect/27(In_06)
  Constant13/1 -> clip_detect/28(In_05)
  [mrst] -> clip_detect/2(in_msb_nr)
  [timing_sync] -> clip_detect/3(In_30_nr)
  [new_acc] -> clip_detect/4(In_29_nr)
  Constant14/1 -> clip_detect/5(In_28_nr)
  Constant19/1 -> clip_detect/6(In_27_nr)
  Constant2/1 -> clip_detect/7(In_26_nr)
  Constant20/1 -> clip_detect/8(In_25_nr)
  Constant21/1 -> clip_detect/9(In_24_nr)
  Constant6/1 -> clip_detect/14(In_19)
  [eq_clip2] -> pulse_ext/1
  [eq_clip1] -> pulse_ext1/1
  [eq_clip0] -> pulse_ext3/1
  Constant7/1 -> clip_detect/18(In_15)
  Constant8/1 -> clip_detect/19(In_14)
  Constant10/1 -> clip_detect/20(In_13)
  Constant12/1 -> clip_detect/21(In_12)
  clip_detect/1(registered_out) -> status/1(out_reg)
  Slice26/1 -> edge_detect/1(in)
  [adc0] -> decat0/1(In1)
  Slice31/1 -> edge_detect1/1(in)
  Slice32/1 -> edge_detect2/1(in)
  edge_detect1/1(out) -> Delay15/1
  edge_detect/1(out) -> Delay16/1
  edge_detect2/1(out) -> Delay4/1
  [sync_arm] -> sync_gen/1(arm)
  Delay/1 -> [adc0]
  pulse_ext2/1(out) -> Inverter2/1
  [timing_sync] -> pulse_ext2/1(in)
  [mrst] -> negedge_delay1/1(in)
  pulse_ext6/1(out) -> Inverter3/1
  [new_acc] -> pulse_ext6/1(in)
  led1_mrst/1 -> Terminator2/1
  led2_sync/1 -> Terminator12/1
  led3_new_acc/1 -> Terminator13/1
  negedge_delay1/1(out) -> Inverter1/1
  status/1(sim_out) -> Terminator3/1
  Constant15/1 -> clip_detect/10(In_23)
  Constant3/1 -> clip_detect/11(In_22)
  Constant4/1 -> clip_detect/12(In_21)
  Constant5/1 -> clip_detect/13(In_20)
  quant0/2(clip_out) -> [eq_clip0]
  quant1/1(sync_out) -> Terminator8/1
  quant1/3(dout0) -> [eq2]
  quant1/4(dout1) -> [eq3]
  quant1/2(clip_out) -> [eq_clip1]
  quant2/1(sync_out) -> Terminator7/1
  quant2/3(dout0) -> [eq4]
  quant2/2(clip_out) -> [eq_clip2]
  Delay4/1 -> [soft_sync]
  Delay15/1 -> [sync_arm]
  Delay16/1 -> [clip_rst]
  Inverter1/1 -> led1_mrst/1
  Inverter2/1 -> led2_sync/1
  Inverter3/1 -> led3_new_acc/1
  calc_adc_sum_sq/1(sum_sq) -> adc_sum_sq0/1(out_reg)
  decat0/1(Out1) -> calc_adc_sum_sq/1(In1)
  decat0/2(Out2) -> calc_adc_sum_sq/2(In2)
  decat0/3(Out3) -> calc_adc_sum_sq/3(In3)
  decat0/4(Out4) -> calc_adc_sum_sq/4(In4)
  adc_sum_sq0/1(sim_out) -> Terminator/1
  calc_adc_sum_sq4/1(sum_sq) -> adc_sum_sq1/1(out_reg)
  decat1/1(Out1) -> calc_adc_sum_sq4/1(In1)
  decat1/2(Out2) -> calc_adc_sum_sq4/2(In2)
  decat1/3(Out3) -> calc_adc_sum_sq4/3(In3)
  decat1/4(Out4) -> calc_adc_sum_sq4/4(In4)
  adc_sum_sq1/1(sim_out) -> Terminator25/1
  calc_adc_sum_sq5/1(sum_sq) -> adc_sum_sq2/1(out_reg)
  decat2/1(Out1) -> calc_adc_sum_sq5/1(In1)
  decat2/2(Out2) -> calc_adc_sum_sq5/2(In2)
  decat2/3(Out3) -> calc_adc_sum_sq5/3(In3)
  decat2/4(Out4) -> calc_adc_sum_sq5/4(In4)
  adc_sum_sq2/1(sim_out) -> Terminator30/1
  [adc1] -> decat1/1(In1)
  [adc2] -> decat2/1(In1)
  quant2/4(dout1) -> [eq5]
  [fft_over] -> bus_or/1(In1)
  Slice6/1 -> fft_wideband_real/2(shift)
  fft_wideband_real/8(of) -> [fft_over]
  a0p0_1st_shift/1(sync_out) -> fft_wideband_real/1(sync)
  a0p0_1st_shift/10(dout9) -> fft_wideband_real/11(in20)
  a0p0_1st_shift/6(dout5) -> fft_wideband_real/7(in10)
  a0p0_1st_shift/7(dout6) -> fft_wideband_real/8(in11)
  a0p0_1st_shift/8(dout7) -> fft_wideband_real/9(in12)
  a0p0_1st_shift/9(dout8) -> fft_wideband_real/10(in13)
  a0p0_1st_shift/2(dout1) -> fft_wideband_real/3(in00)
  a0p0_1st_shift/3(dout2) -> fft_wideband_real/4(in01)
  a0p0_1st_shift/5(dout4) -> fft_wideband_real/6(in03)
  a0p0_1st_shift/4(dout3) -> fft_wideband_real/5(in02)
  bus_or/1(Out1) -> pulse_ext4/1
  fft_wideband_real/1(sync_out) -> [fft_sync]
  bus_create4/1(bus_out) -> [fft_0]
  [fft_sync] -> quant0/1(sync)
  [fft_sync] -> quant1/1(sync)
  [fft_sync] -> quant2/1(sync)
  [fft_0] -> quant0/2(din)
  [fft_1] -> quant1/2(din)
  [fft_2] -> quant2/2(din)
  fft_wideband_real/5(out11) -> bus_create5/2(in2)
  fft_wideband_real/4(out10) -> bus_create5/1(in1)
  bus_create5/1(bus_out) -> [fft_1]
  bus_create3/1(bus_out) -> [fft_2]
  snap_adc/1(a1) -> bus_create/1(in1)
  snap_adc/2(a2) -> bus_create/2(in2)
  snap_adc/3(a3) -> bus_create/3(in3)
  snap_adc/4(a4) -> bus_create/4(in4)
  bus_create1/1(bus_out) -> Delay1/1
  Delay1/1 -> [adc1]
  snap_adc/5(b1) -> bus_create1/1(in1)
  snap_adc/6(b2) -> bus_create1/2(in2)
  snap_adc/7(b3) -> bus_create1/3(in3)
  snap_adc/8(b4) -> bus_create1/4(in4)
  bus_create2/1(bus_out) -> Delay2/1
  Delay2/1 -> [adc2]
  snap_adc/9(c1) -> bus_create2/1(in1)
  snap_adc/10(c2) -> bus_create2/2(in2)
  snap_adc/11(c3) -> bus_create2/3(in3)
  snap_adc/12(c4) -> bus_create2/4(in4)
  pps_in/1 -> edge_detect3/1(in)
  edge_detect3/1(out) -> Logical3/2
  [timing_sync] -> pfb_fir_generic/1(sync)
  [adc0] -> bus_expand1/1(bus_in)
  bus_expand1/1(msb_out4) -> pfb_fir_generic/2(pol0_in0)
  bus_expand1/2(out3) -> pfb_fir_generic/3(pol0_in1)
  bus_expand1/3(out2) -> pfb_fir_generic/4(pol0_in2)
  bus_expand1/4(lsb_out1) -> pfb_fir_generic/5(pol0_in3)
  [adc1] -> bus_expand2/1(bus_in)
  bus_expand2/1(msb_out4) -> pfb_fir_generic/6(pol1_in0)
  bus_expand2/2(out3) -> pfb_fir_generic/7(pol1_in1)
  bus_expand2/3(out2) -> pfb_fir_generic/8(pol1_in2)
  bus_expand2/4(lsb_out1) -> pfb_fir_generic/9(pol1_in3)
  [adc2] -> bus_expand3/1(bus_in)
  bus_expand3/1(msb_out4) -> pfb_fir_generic/10(pol2_in0)
  bus_expand3/2(out3) -> pfb_fir_generic/11(pol2_in1)
  bus_expand3/3(out2) -> pfb_fir_generic/12(pol2_in2)
  bus_expand3/4(lsb_out1) -> pfb_fir_generic/13(pol2_in3)
  pfb_fir_generic/1(sync_out) -> a0p0_1st_shift/1(sync_in)
  pfb_fir_generic/2(pol0_out0) -> a0p0_1st_shift/2(din1)
  pfb_fir_generic/3(pol0_out1) -> a0p0_1st_shift/3(din2)
  pfb_fir_generic/4(pol0_out2) -> a0p0_1st_shift/4(din3)
  pfb_fir_generic/5(pol0_out3) -> a0p0_1st_shift/5(din4)
  pfb_fir_generic/6(pol1_out0) -> a0p0_1st_shift/6(din5)
  pfb_fir_generic/7(pol1_out1) -> a0p0_1st_shift/7(din6)
  pfb_fir_generic/8(pol1_out2) -> a0p0_1st_shift/8(din7)
  pfb_fir_generic/9(pol1_out3) -> a0p0_1st_shift/9(din8)
  pfb_fir_generic/10(pol2_out0) -> a0p0_1st_shift/10(din9)
  pfb_fir_generic/11(pol2_out1) -> a0p0_1st_shift/11(din10)
  pfb_fir_generic/12(pol2_out2) -> a0p0_1st_shift/12(din11)
  pfb_fir_generic/13(pol2_out3) -> a0p0_1st_shift/13(din12)
  a0p0_1st_shift/11(dout10) -> fft_wideband_real/12(in21)
  a0p0_1st_shift/12(dout11) -> fft_wideband_real/13(in22)
  a0p0_1st_shift/13(dout12) -> fft_wideband_real/14(in23)
  fft_wideband_real/6(out20) -> bus_create3/1(in1)
  fft_wideband_real/7(out21) -> bus_create3/2(in2)
  fft_wideband_real/2(out00) -> bus_create4/1(in1)
  fft_wideband_real/3(out01) -> bus_create4/2(in2)
  pulse_ext/1 -> clip_detect/15(In_18)
  pulse_ext1/1 -> clip_detect/16(In_17)
  pulse_ext3/1 -> clip_detect/17(In_16)
  pulse_ext4/1 -> clip_detect/22(In_11), clip_detect/23(In_10), clip_detect/24(In_09), clip_detect/25(In_08)
  Constant26/1 -> snapshot_eq/4(we)
  [sync_rnd] -> snapshot_eq/5(trig)
  Concat2/1 -> snapshot_eq/1(in_quant0)
  Concat4/1 -> snapshot_eq/2(in_quant1)
  Concat3/1 -> snapshot_eq/3(in_quant2)
  [eq0] -> Concat2/1
  [eq1] -> Concat2/2
  [eq4] -> Concat3/1
  [eq2] -> Concat4/1
  [eq3] -> Concat4/2
  [eq5] -> Concat3/2
  bus_expand4/1(msb_out3) -> dir_x1/2(a)
  bus_expand4/2(out2) -> dir_x1/3(b)
  bus_expand4/3(lsb_out1) -> dir_x1/4(c)
  Delay20/1 -> bus_expand4/1(bus_in)
  bus_expand5/1(msb_out3) -> dir_x0/2(a)
  bus_expand5/2(out2) -> dir_x0/3(b)
  bus_expand5/3(lsb_out1) -> dir_x0/4(c)
  Delay21/1 -> bus_expand5/1(bus_in)
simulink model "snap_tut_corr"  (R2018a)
settings: Solver=VariableStepDiscrete  StartTime=0.0  StopTime=100  RelTol=1e-3
undefined symbols (not defined in the file): Area, behavioral, Behavioral, Bit, Both, BRAM, bram, c, core, d, Falling, getfield, hamming, hex2dec, led, Location, logic, Lower, Minimum_Area, out, quant0, quant1, quant2, reg, repmat, Rising, ROACH, ROACH2, SNAP, Speed, sync_in, Truncate, Unsigned, Upper, Width, Wrap, xc7k160t
libraries: xbsIndex_r4 x17901, casper_library_misc x29, xbsReplacements_r4 x20, casper_library_delays x14, xps_library x5
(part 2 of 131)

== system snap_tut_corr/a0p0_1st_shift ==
  sync_in : Inport
  din1 : Inport  Port=2
  din2 : Inport  Port=3
  din3 : Inport  Port=4
  din4 : Inport  Port=5
  din5 : Inport  Port=6
  din6 : Inport  Port=7
  din7 : Inport  Port=8
  din8 : Inport  Port=9
  din9 : Inport  Port=10
  din10 : Inport  Port=11
  din11 : Inport  Port=12
  din12 : Inport  Port=13
  Delay : xbsIndex_r4/Delay  rst=off  infoeditControl=Selection of Reset will increase slice count due to use of real FFs and instead of SRLs  en=off  latency=latency  reg_retiming=off  dbl_ovrd=off  block_type=delay
  Shift{1..12} (12 alike) : xbsIndex_r4/Shift  shift_dir=Right  shift_bits=shift  en=off  latency=latency  precision=Full  arith_type="Signed  (2's comp)"  n_bits=16  bin_pt=14  quantization=Truncate  overflow=Wrap  dbl_ovrd=off  block_type=shift
  sync_out : Outport
  dout1 : Outport  Port=2
  dout2 : Outport  Port=3
  dout3 : Outport  Port=4
  dout4 : Outport  Port=5
  dout5 : Outport  Port=6
  dout6 : Outport  Port=7
  dout7 : Outport  Port=8
  dout8 : Outport  Port=9
  dout9 : Outport  Port=10
  dout10 : Outport  Port=11
  dout11 : Outport  Port=12
  dout12 : Outport  Port=13
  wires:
  din1/1 -> Shift3/1
  Shift3/1 -> dout1/1
  din2/1 -> Shift1/1
  Shift1/1 -> dout2/1
  din3/1 -> Shift4/1
  Shift4/1 -> dout3/1
  din4/1 -> Shift2/1
  Shift2/1 -> dout4/1
  sync_in/1 -> Delay/1
  Delay/1 -> sync_out/1
  din5/1 -> Shift7/1
  Shift7/1 -> dout5/1
  din6/1 -> Shift5/1
  Shift5/1 -> dout6/1
  din7/1 -> Shift8/1
  Shift8/1 -> dout7/1
  din8/1 -> Shift6/1
  Shift6/1 -> dout8/1
  din9/1 -> Shift11/1
  Shift11/1 -> dout9/1
  din10/1 -> Shift9/1
  Shift9/1 -> dout10/1
  din11/1 -> Shift12/1
  Shift12/1 -> dout11/1
  din12/1 -> Shift10/1
  Shift10/1 -> dout12/1

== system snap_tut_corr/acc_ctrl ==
  mrst : Inport
  sync : Inport  Port=2
  acc_len : Inport  Port=3
  Delay : xbsIndex_r4/Delay  rst=off  infoeditControl=Selection of Reset will increase slice count due to use of real FFs and instead of SRLs  en=off  latency=1  reg_retiming=on  dbl_ovrd=off  block_type=delay
  Logical : xbsIndex_r4/Logical  logical_function=OR  inputs=2  en=off  latency=0  precision=Full  arith_type=Unsigned  n_bits=8  bin_pt=2  align_bp=on  dbl_ovrd=off  block_type=logical
  Register : xbsIndex_r4/Register  init=0  rst=on  en=on  dbl_ovrd=off  block_type=register
  Relational5 : xbsIndex_r4/Relational  mode=a>=b  op_type=Bool  en=off  latency=0  dbl_ovrd=off  block_type=relational
  Shift : xbsIndex_r4/Shift  shift_dir=Left  shift_bits=chan_bits  en=off  latency=0  precision=Full  arith_type="Signed  (2's comp)"  n_bits=8  bin_pt=2  quantization=Truncate  overflow=Wrap  dbl_ovrd=off  block_type=shift
  cntr : xbsIndex_r4/Counter  cnt_type=Free Running  cnt_to=Inf  operation=Up  start_count=1  cnt_by_val=1  arith_type=Unsigned  n_bits=32  bin_pt=0  load_pin=off  rst=on  en=off  explicit_period=on  period=1  use_behavioral_HDL=off  implementation=Fabric  use_rpm=on  dbl_ovrd=off  block_type=counter
  edge_detect : Subsystem  AncestorBlock=casper_library_misc/edge_detect  mask(edge_detect){edge=Rising, polarity=Active High, x_in=[0 0.08 0.08 0.16 0.16 0.24 0.24 0.32 0.32 0.4], y_in=[-1 -1  1  1  1  1  1  1  1  1], x_out=[0.6 0.68 0.68 0.76 0.76 0.84 0.84 0.92 0.92 1], y_out=[-1 -1  1  1 -1 -1 -1 -1 -1 -1]}
      mask prompts: edge "Edge Type"; polarity "Output Polarity"; x_in "Input X Positions"; y_in "Input Y Positions"; x_out "Output X Positions"; y_out "Output Y Positions"
      mask help: Output is active for one-cycle after each edge of the specified type (i.e. rising, falling or both).
      mask init:
      | edge_detect_init(gcb,...
      |     'edge',edge,...
      |     'polarity',polarity,...
      |     'x_in',x_in,...
      |     'x_out',x_out,...
      |     'y_in',y_in,...
      |     'y_out',y_out);
      | 
      | x_in_num=str2num(getfield(getfield(get_param(gcb,'UserData'),'parameters'),'x_in'));
      | x_out_num=str2num(getfield(getfield(get_param(gcb,'UserData'),'parameters'),'x_out'));
      | y_in_num=str2num(getfield(getfield(get_param(gcb,'UserData'),'parameters'),'y_in'));
      | y_out_num=str2num(getfield(getfield(get_param(gcb,'UserData'),'parameters'),'y_out'));
  edge_detect1 : Subsystem  AncestorBlock=casper_library_misc/edge_detect  mask(edge_detect){edge=Rising, polarity=Active High, x_in=[0 0.08 0.08 0.16 0.16 0.24 0.24 0.32 0.32 0.4], y_in=[-1 -1  1  1  1  1  1  1  1  1], x_out=[0.6 0.68 0.68 0.76 0.76 0.84 0.84 0.92 0.92 1], y_out=[-1 -1  1  1 -1 -1 -1 -1 -1 -1]}
      mask prompts: edge "Edge Type"; polarity "Output Polarity"; x_in "Input X Positions"; y_in "Input Y Positions"; x_out "Output X Positions"; y_out "Output Y Positions"
      mask help: Output is active for one-cycle after each edge of the specified type (i.e. rising, falling or both).
      mask init:
      | edge_detect_init(gcb,...
      |     'edge',edge,...
      |     'polarity',polarity,...
      |     'x_in',x_in,...
      |     'x_out',x_out,...
      |     'y_in',y_in,...
      |     'y_out',y_out);
      | 
      | x_in_num=str2num(getfield(getfield(get_param(gcb,'UserData'),'parameters'),'x_in'));
      | x_out_num=str2num(getfield(getfield(get_param(gcb,'UserData'),'parameters'),'x_out'));
      | y_in_num=str2num(getfield(getfield(get_param(gcb,'UserData'),'parameters'),'y_in'));
      | y_out_num=str2num(getfield(getfield(get_param(gcb,'UserData'),'parameters'),'y_out'));
  edge_detect2 : Subsystem  AncestorBlock=casper_library_misc/edge_detect  mask(edge_detect){edge=Rising, polarity=Active High, x_in=[0 0.08 0.08 0.16 0.16 0.24 0.24 0.32 0.32 0.4], y_in=[-1 -1  1  1  1  1  1  1  1  1], x_out=[0.6 0.68 0.68 0.76 0.76 0.84 0.84 0.92 0.92 1], y_out=[-1 -1  1  1 -1 -1 -1 -1 -1 -1]}
      mask prompts: edge "Edge Type"; polarity "Output Polarity"; x_in "Input X Positions"; y_in "Input Y Positions"; x_out "Output X Positions"; y_out "Output Y Positions"
      mask help: Output is active for one-cycle after each edge of the specified type (i.e. rising, falling or both).
      mask init:
      | edge_detect_init(gcb,...
      |     'edge',edge,...
      |     'polarity',polarity,...
      |     'x_in',x_in,...
      |     'x_out',x_out,...
      |     'y_in',y_in,...
      |     'y_out',y_out);
      | 
      | x_in_num=str2num(getfield(getfield(get_param(gcb,'UserData'),'parameters'),'x_in'));
      | x_out_num=str2num(getfield(getfield(get_param(gcb,'UserData'),'parameters'),'x_out'));
      | y_in_num=str2num(getfield(getfield(get_param(gcb,'UserData'),'parameters'),'y_in'));
      | y_out_num=str2num(getfield(getfield(get_param(gcb,'UserData'),'parameters'),'y_out'));
  new_acc : Outport
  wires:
  Relational5/1 -> Logical/2, edge_detect2/1(in)
  acc_len/1 -> Shift/1
  edge_detect2/1(out) -> new_acc/1
  Logical/1 -> cntr/1
  Register/1 -> edge_detect1/1(in)
  edge_detect/1(out) -> Register/2
  edge_detect1/1(out) -> Logical/1
  Delay/1 -> Relational5/2
  Shift/1 -> Delay/1
  cntr/1 -> Relational5/1
  mrst/1 -> edge_detect/1(in)
  sync/1 -> Register/1, Register/3

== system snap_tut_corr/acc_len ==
  sim_1 : Inport
  convert1_1 : DataTypeConversion  OutDataTypeStr=fixdt('ufix32_En0')
  convert2_1 : DataTypeConversion  OutDataTypeStr=fixdt('ufix32_En0')  ConvertRealWorld=Stored Integer (SI)
  gain_1 : Gain
  io_delay : xbsIndex_r4/Delay  rst=off  infoeditControl=Selection of Reset will increase slice count due to use of real FFs and instead of SRLs  en=off  latency=0  reg_retiming=on  dbl_ovrd=off  block_type=delay
  reint1 : xbsIndex_r4/Reinterpret  force_arith_type=on  arith_type=Unsigned  force_bin_pt=on  bin_pt=0  block_type=reinterpret
  slice_reg : xbsIndex_r4/Slice  nbits=32  boolean_output=off  mode=Lower Bit Location + Width  bit1=0  base1=MSB of Input  bit0=0  base0=LSB of Input  dbl_ovrd=off  block_type=slice
  snap_tut_corr_acc_len_user_data_out : xbsIndex_r4/Gateway In  gui_display_data_type=Fixed-point  arith_type=Unsigned  n_bits=32  bin_pt=0  preci_type=Single  exp_width=8  frac_width=24  rows=1  columns=1  quantization="Round  (unbiased: +/- Inf)"  overflow=Saturate  period=1  UseAsADC=off  ADCChannel='1'  interface=None  automatic_assignment=on  address_offset=hex2dec('00')  intf_name=''  intf_description=''  default_value=0  timing_constraint=None  locs_specified=off  LOCs={}  io_standard={}  inherit_from_input=off  hdl_port=on  dbl_ovrd=off  block_type=gatewayin
  in_reg : Outport
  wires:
  snap_tut_corr_acc_len_user_data_out/1 -> io_delay/1
  sim_1/1 -> convert1_1/1
  convert1_1/1 -> convert2_1/1
  convert2_1/1 -> gain_1/1
  gain_1/1 -> snap_tut_corr_acc_len_user_data_out/1
  io_delay/1 -> slice_reg/1
  slice_reg/1 -> reint1/1
  reint1/1 -> in_reg/1

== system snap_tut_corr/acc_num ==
  out_reg : Inport
  assert_reg : xbsIndex_r4/Assert  assert_type=on  type_source=Explicitly  gui_display_data_type=Fixed-point  arith_type=Unsigned  n_bits=32  bin_pt=0  preci_type=Single  exp_width=8  frac_width=24  assert_rate=off  rate_source=Explicitly  period=1  output_port=on  block_type=assert
  cast_gw : xbsIndex_r4/Convert  gui_display_data_type=Fixed-point  arith_type=Unsigned  n_bits=32  bin_pt=0  float_type=Single  exp_bits=8  fraction_bits=24  quantization=Truncate  overflow=Wrap  en=off  latency=1  pipeline=off  dbl_ovrd=off  block_type=convert
  io_delay : xbsIndex_r4/Delay  rst=off  infoeditControl=Selection of Reset will increase slice count due to use of real FFs and instead of SRLs  en=off  latency=0  reg_retiming=on  dbl_ovrd=off  block_type=delay
  reint1 : xbsIndex_r4/Reinterpret  force_arith_type=on  arith_type=Unsigned  force_bin_pt=on  bin_pt=0  block_type=reinterpret
  snap_tut_corr_acc_num_user_data_in : xbsIndex_r4/Gateway Out  inherit_from_input=off  hdl_port=on  rows=1  columns=1  UseAsDAC=off  DACChannel='1'  interface=None  automatic_assignment=on  address_offset=hex2dec('00')  intf_name=''  intf_description=''  timing_constraint=None  locs_specified=off  LOCs={}  io_standard={}  block_type=gatewayout
  sim_out : Outport
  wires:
  io_delay/1 -> cast_gw/1
  cast_gw/1 -> snap_tut_corr_acc_num_user_data_in/1
  snap_tut_corr_acc_num_user_data_in/1 -> sim_out/1
  out_reg/1 -> assert_reg/1
  assert_reg/1 -> reint1/1
  reint1/1 -> io_delay/1

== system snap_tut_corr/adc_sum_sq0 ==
  out_reg : Inport
  assert_reg : xbsIndex_r4/Assert  assert_type=on  type_source=Explicitly  gui_display_data_type=Fixed-point  arith_type=Unsigned  n_bits=32  bin_pt=0  preci_type=Single  exp_width=8  frac_width=24  assert_rate=off  rate_source=Explicitly  period=1  output_port=on  block_type=assert
  cast_gw : xbsIndex_r4/Convert  gui_display_data_type=Fixed-point  arith_type=Unsigned  n_bits=32  bin_pt=0  float_type=Single  exp_bits=8  fraction_bits=24  quantization=Truncate  overflow=Wrap  en=off  latency=1  pipeline=off  dbl_ovrd=off  block_type=convert
  io_delay : xbsIndex_r4/Delay  rst=off  infoeditControl=Selection of Reset will increase slice count due to use of real FFs and instead of SRLs  en=off  latency=0  reg_retiming=on  dbl_ovrd=off  block_type=delay
  reint1 : xbsIndex_r4/Reinterpret  force_arith_type=on  arith_type=Unsigned  force_bin_pt=on  bin_pt=0  block_type=reinterpret
  snap_tut_corr_adc_sum_sq0_user_data_in : xbsIndex_r4/Gateway Out  inherit_from_input=off  hdl_port=on  rows=1  columns=1  UseAsDAC=off  DACChannel='1'  interface=None  automatic_assignment=on  address_offset=hex2dec('00')  intf_name=''  intf_description=''  timing_constraint=None  locs_specified=off  LOCs={}  io_standard={}  block_type=gatewayout
  sim_out : Outport
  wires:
  io_delay/1 -> cast_gw/1
  cast_gw/1 -> snap_tut_corr_adc_sum_sq0_user_data_in/1
  snap_tut_corr_adc_sum_sq0_user_data_in/1 -> sim_out/1
  out_reg/1 -> assert_reg/1
  assert_reg/1 -> reint1/1
  reint1/1 -> io_delay/1

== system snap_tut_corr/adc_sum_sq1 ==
  out_reg : Inport
  assert_reg : xbsIndex_r4/Assert  assert_type=on  type_source=Explicitly  gui_display_data_type=Fixed-point  arith_type=Unsigned  n_bits=32  bin_pt=0  preci_type=Single  exp_width=8  frac_width=24  assert_rate=off  rate_source=Explicitly  period=1  output_port=on  block_type=assert
  cast_gw : xbsIndex_r4/Convert  gui_display_data_type=Fixed-point  arith_type=Unsigned  n_bits=32  bin_pt=0  float_type=Single  exp_bits=8  fraction_bits=24  quantization=Truncate  overflow=Wrap  en=off  latency=1  pipeline=off  dbl_ovrd=off  block_type=convert
  io_delay : xbsIndex_r4/Delay  rst=off  infoeditControl=Selection of Reset will increase slice count due to use of real FFs and instead of SRLs  en=off  latency=0  reg_retiming=on  dbl_ovrd=off  block_type=delay
  reint1 : xbsIndex_r4/Reinterpret  force_arith_type=on  arith_type=Unsigned  force_bin_pt=on  bin_pt=0  block_type=reinterpret
  snap_tut_corr_adc_sum_sq1_user_data_in : xbsIndex_r4/Gateway Out  inherit_from_input=off  hdl_port=on  rows=1  columns=1  UseAsDAC=off  DACChannel='1'  interface=None  automatic_assignment=on  address_offset=hex2dec('00')  intf_name=''  intf_description=''  timing_constraint=None  locs_specified=off  LOCs={}  io_standard={}  block_type=gatewayout
  sim_out : Outport
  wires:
  io_delay/1 -> cast_gw/1
  cast_gw/1 -> snap_tut_corr_adc_sum_sq1_user_data_in/1
  snap_tut_corr_adc_sum_sq1_user_data_in/1 -> sim_out/1
  out_reg/1 -> assert_reg/1
  assert_reg/1 -> reint1/1
  reint1/1 -> io_delay/1

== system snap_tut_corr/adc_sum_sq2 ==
  out_reg : Inport
  assert_reg : xbsIndex_r4/Assert  assert_type=on  type_source=Explicitly  gui_display_data_type=Fixed-point  arith_type=Unsigned  n_bits=32  bin_pt=0  preci_type=Single  exp_width=8  frac_width=24  assert_rate=off  rate_source=Explicitly  period=1  output_port=on  block_type=assert
  cast_gw : xbsIndex_r4/Convert  gui_display_data_type=Fixed-point  arith_type=Unsigned  n_bits=32  bin_pt=0  float_type=Single  exp_bits=8  fraction_bits=24  quantization=Truncate  overflow=Wrap  en=off  latency=1  pipeline=off  dbl_ovrd=off  block_type=convert
  io_delay : xbsIndex_r4/Delay  rst=off  infoeditControl=Selection of Reset will increase slice count due to use of real FFs and instead of SRLs  en=off  latency=0  reg_retiming=on  dbl_ovrd=off  block_type=delay
  reint1 : xbsIndex_r4/Reinterpret  force_arith_type=on  arith_type=Unsigned  force_bin_pt=on  bin_pt=0  block_type=reinterpret
  snap_tut_corr_adc_sum_sq2_user_data_in : xbsIndex_r4/Gateway Out  inherit_from_input=off  hdl_port=on  rows=1  columns=1  UseAsDAC=off  DACChannel='1'  interface=None  automatic_assignment=on  address_offset=hex2dec('00')  intf_name=''  intf_description=''  timing_constraint=None  locs_specified=off  LOCs={}  io_standard={}  block_type=gatewayout
  sim_out : Outport
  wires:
  io_delay/1 -> cast_gw/1
  cast_gw/1 -> snap_tut_corr_adc_sum_sq2_user_data_in/1
  snap_tut_corr_adc_sum_sq2_user_data_in/1 -> sim_out/1
  out_reg/1 -> assert_reg/1
  assert_reg/1 -> reint1/1
  reint1/1 -> io_delay/1

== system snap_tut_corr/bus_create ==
  in1 : Inport
  in2 : Inport  Port=2
  in3 : Inport  Port=3
  in4 : Inport  Port=4
  concatenate : xbsIndex_r4/Concat  num_inputs=4  dbl_ovrd=off  block_type=concat
  reinterpret{1..4} (4 alike) : xbsIndex_r4/Reinterpret  force_arith_type=on  arith_type=Unsigned  force_bin_pt=on  bin_pt=0  block_type=reinterpret
  bus_out : Outport
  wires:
  concatenate/1 -> bus_out/1
  in1/1 -> reinterpret1/1
  reinterpret1/1 -> concatenate/1
  in2/1 -> reinterpret2/1
  reinterpret2/1 -> concatenate/2
  in3/1 -> reinterpret3/1
  reinterpret3/1 -> concatenate/3
  in4/1 -> reinterpret4/1
  reinterpret4/1 -> concatenate/4

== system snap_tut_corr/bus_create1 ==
  in1 : Inport
  in2 : Inport  Port=2
  in3 : Inport  Port=3
  in4 : Inport  Port=4
  concatenate : xbsIndex_r4/Concat  num_inputs=4  dbl_ovrd=off  block_type=concat
  reinterpret{1..4} (4 alike) : xbsIndex_r4/Reinterpret  force_arith_type=on  arith_type=Unsigned  force_bin_pt=on  bin_pt=0  block_type=reinterpret
  bus_out : Outport
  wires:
  concatenate/1 -> bus_out/1
  in1/1 -> reinterpret1/1
  reinterpret1/1 -> concatenate/1
  in2/1 -> reinterpret2/1
  reinterpret2/1 -> concatenate/2
  in3/1 -> reinterpret3/1
  reinterpret3/1 -> concatenate/3
  in4/1 -> reinterpret4/1
  reinterpret4/1 -> concatenate/4

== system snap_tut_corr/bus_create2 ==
  in1 : Inport
  in2 : Inport  Port=2
  in3 : Inport  Port=3
  in4 : Inport  Port=4
  concatenate : xbsIndex_r4/Concat  num_inputs=4  dbl_ovrd=off  block_type=concat
  reinterpret{1..4} (4 alike) : xbsIndex_r4/Reinterpret  force_arith_type=on  arith_type=Unsigned  force_bin_pt=on  bin_pt=0  block_type=reinterpret
  bus_out : Outport
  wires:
  concatenate/1 -> bus_out/1
  in1/1 -> reinterpret1/1
  reinterpret1/1 -> concatenate/1
  in2/1 -> reinterpret2/1
  reinterpret2/1 -> concatenate/2
  in3/1 -> reinterpret3/1
  reinterpret3/1 -> concatenate/3
  in4/1 -> reinterpret4/1
  reinterpret4/1 -> concatenate/4

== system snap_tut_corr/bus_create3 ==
  in1 : Inport
  in2 : Inport  Port=2
  concatenate : xbsIndex_r4/Concat  num_inputs=2  dbl_ovrd=off  block_type=concat
  reinterpret1 : xbsIndex_r4/Reinterpret  force_arith_type=on  arith_type=Unsigned  force_bin_pt=on  bin_pt=0  block_type=reinterpret
  reinterpret2 : xbsIndex_r4/Reinterpret  force_arith_type=on  arith_type=Unsigned  force_bin_pt=on  bin_pt=0  block_type=reinterpret
  bus_out : Outport
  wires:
  concatenate/1 -> bus_out/1
  in1/1 -> reinterpret1/1
  reinterpret1/1 -> concatenate/1
  in2/1 -> reinterpret2/1
  reinterpret2/1 -> concatenate/2

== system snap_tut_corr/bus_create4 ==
  in1 : Inport
  in2 : Inport  Port=2
  concatenate : xbsIndex_r4/Concat  num_inputs=2  dbl_ovrd=off  block_type=concat
  reinterpret1 : xbsIndex_r4/Reinterpret  force_arith_type=on  arith_type=Unsigned  force_bin_pt=on  bin_pt=0  block_type=reinterpret
  reinterpret2 : xbsIndex_r4/Reinterpret  force_arith_type=on  arith_type=Unsigned  force_bin_pt=on  bin_pt=0  block_type=reinterpret
  bus_out : Outport
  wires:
  concatenate/1 -> bus_out/1
  in1/1 -> reinterpret1/1
  reinterpret1/1 -> concatenate/1
  in2/1 -> reinterpret2/1
  reinterpret2/1 -> concatenate/2

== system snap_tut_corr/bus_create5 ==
  in1 : Inport
  in2 : Inport  Port=2
  concatenate : xbsIndex_r4/Concat  num_inputs=2  dbl_ovrd=off  block_type=concat
  reinterpret1 : xbsIndex_r4/Reinterpret  force_arith_type=on  arith_type=Unsigned  force_bin_pt=on  bin_pt=0  block_type=reinterpret
  reinterpret2 : xbsIndex_r4/Reinterpret  force_arith_type=on  arith_type=Unsigned  force_bin_pt=on  bin_pt=0  block_type=reinterpret
  bus_out : Outport
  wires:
  concatenate/1 -> bus_out/1
  in1/1 -> reinterpret1/1
  reinterpret1/1 -> concatenate/1
  in2/1 -> reinterpret2/1
  reinterpret2/1 -> concatenate/2

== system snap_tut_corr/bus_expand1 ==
  bus_in : Inport
  reinterpret{1..4} (4 alike) : xbsIndex_r4/Reinterpret  force_arith_type=on  arith_type="Signed  (2's comp)"  force_bin_pt=on  bin_pt=7  block_type=reinterpret
  slice1 : xbsIndex_r4/Slice  nbits=8  boolean_output=off  mode=Upper Bit Location + Width  bit1=-24  base1=MSB of Input  bit0=0  base0=LSB of Input  dbl_ovrd=off  block_type=slice
  slice2 : xbsIndex_r4/Slice  nbits=8  boolean_output=off  mode=Upper Bit Location + Width  bit1=-16  base1=MSB of Input  bit0=0  base0=LSB of Input  dbl_ovrd=off  block_type=slice
  slice3 : xbsIndex_r4/Slice  nbits=8  boolean_output=off  mode=Upper Bit Location + Width  bit1=-8  base1=MSB of Input  bit0=0  base0=LSB of Input  dbl_ovrd=off  block_type=slice
  slice4 : xbsIndex_r4/Slice  nbits=8  boolean_output=off  mode=Upper Bit Location + Width  bit1=0  base1=MSB of Input  bit0=0  base0=LSB of Input  dbl_ovrd=off  block_type=slice
  msb_out4 : Outport
  out3 : Outport  Port=2
  out2 : Outport  Port=3
  lsb_out1 : Outport  Port=4
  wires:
  bus_in/1 -> slice4/1, slice3/1, slice2/1, slice1/1
  slice4/1 -> reinterpret4/1
  reinterpret4/1 -> msb_out4/1
  slice3/1 -> reinterpret3/1
  reinterpret3/1 -> out3/1
  slice2/1 -> reinterpret2/1
  reinterpret2/1 -> out2/1
  slice1/1 -> reinterpret1/1
  reinterpret1/1 -> lsb_out1/1

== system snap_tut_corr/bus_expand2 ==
  bus_in : Inport
  reinterpret{1..4} (4 alike) : xbsIndex_r4/Reinterpret  force_arith_type=on  arith_type="Signed  (2's comp)"  force_bin_pt=on  bin_pt=7  block_type=reinterpret
  slice1 : xbsIndex_r4/Slice  nbits=8  boolean_output=off  mode=Upper Bit Location + Width  bit1=-24  base1=MSB of Input  bit0=0  base0=LSB of Input  dbl_ovrd=off  block_type=slice
  slice2 : xbsIndex_r4/Slice  nbits=8  boolean_output=off  mode=Upper Bit Location + Width  bit1=-16  base1=MSB of Input  bit0=0  base0=LSB of Input  dbl_ovrd=off  block_type=slice
  slice3 : xbsIndex_r4/Slice  nbits=8  boolean_output=off  mode=Upper Bit Location + Width  bit1=-8  base1=MSB of Input  bit0=0  base0=LSB of Input  dbl_ovrd=off  block_type=slice
  slice4 : xbsIndex_r4/Slice  nbits=8  boolean_output=off  mode=Upper Bit Location + Width  bit1=0  base1=MSB of Input  bit0=0  base0=LSB of Input  dbl_ovrd=off  block_type=slice
  msb_out4 : Outport
  out3 : Outport  Port=2
  out2 : Outport  Port=3
  lsb_out1 : Outport  Port=4
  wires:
  bus_in/1 -> slice4/1, slice3/1, slice2/1, slice1/1
  slice4/1 -> reinterpret4/1
  reinterpret4/1 -> msb_out4/1
  slice3/1 -> reinterpret3/1
  reinterpret3/1 -> out3/1
  slice2/1 -> reinterpret2/1
  reinterpret2/1 -> out2/1
  slice1/1 -> reinterpret1/1
  reinterpret1/1 -> lsb_out1/1

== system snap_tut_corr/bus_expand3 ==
  bus_in : Inport
  reinterpret{1..4} (4 alike) : xbsIndex_r4/Reinterpret  force_arith_type=on  arith_type="Signed  (2's comp)"  force_bin_pt=on  bin_pt=7  block_type=reinterpret
  slice1 : xbsIndex_r4/Slice  nbits=8  boolean_output=off  mode=Upper Bit Location + Width  bit1=-24  base1=MSB of Input  bit0=0  base0=LSB of Input  dbl_ovrd=off  block_type=slice
  slice2 : xbsIndex_r4/Slice  nbits=8  boolean_output=off  mode=Upper Bit Location + Width  bit1=-16  base1=MSB of Input  bit0=0  base0=LSB of Input  dbl_ovrd=off  block_type=slice
  slice3 : xbsIndex_r4/Slice  nbits=8  boolean_output=off  mode=Upper Bit Location + Width  bit1=-8  base1=MSB of Input  bit0=0  base0=LSB of Input  dbl_ovrd=off  block_type=slice
  slice4 : xbsIndex_r4/Slice  nbits=8  boolean_output=off  mode=Upper Bit Location + Width  bit1=0  base1=MSB of Input  bit0=0  base0=LSB of Input  dbl_ovrd=off  block_type=slice
  msb_out4 : Outport
  out3 : Outport  Port=2
  out2 : Outport  Port=3
  lsb_out1 : Outport  Port=4
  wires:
  bus_in/1 -> slice4/1, slice3/1, slice2/1, slice1/1
  slice4/1 -> reinterpret4/1
  reinterpret4/1 -> msb_out4/1
  slice3/1 -> reinterpret3/1
  reinterpret3/1 -> out3/1
  slice2/1 -> reinterpret2/1
  reinterpret2/1 -> out2/1
  slice1/1 -> reinterpret1/1
  reinterpret1/1 -> lsb_out1/1

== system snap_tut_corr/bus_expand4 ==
  bus_in : Inport
  reinterpret1 : xbsIndex_r4/Reinterpret  force_arith_type=on  arith_type=Unsigned  force_bin_pt=on  bin_pt=0  block_type=reinterpret
  reinterpret2 : xbsIndex_r4/Reinterpret  force_arith_type=on  arith_type=Unsigned  force_bin_pt=on  bin_pt=0  block_type=reinterpret
  reinterpret3 : xbsIndex_r4/Reinterpret  force_arith_type=on  arith_type=Unsigned  force_bin_pt=on  bin_pt=0  block_type=reinterpret
  slice1 : xbsIndex_r4/Slice  nbits=8  boolean_output=off  mode=Upper Bit Location + Width  bit1=-16  base1=MSB of Input  bit0=0  base0=LSB of Input  dbl_ovrd=off  block_type=slice
  slice2 : xbsIndex_r4/Slice  nbits=8  boolean_output=off  mode=Upper Bit Location + Width  bit1=-8  base1=MSB of Input  bit0=0  base0=LSB of Input  dbl_ovrd=off  block_type=slice
  slice3 : xbsIndex_r4/Slice  nbits=8  boolean_output=off  mode=Upper Bit Location + Width  bit1=0  base1=MSB of Input  bit0=0  base0=LSB of Input  dbl_ovrd=off  block_type=slice
  msb_out3 : Outport
  out2 : Outport  Port=2
  lsb_out1 : Outport  Port=3
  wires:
  bus_in/1 -> slice3/1, slice2/1, slice1/1
  slice3/1 -> reinterpret3/1
  reinterpret3/1 -> msb_out3/1
  slice2/1 -> reinterpret2/1
  reinterpret2/1 -> out2/1
  slice1/1 -> reinterpret1/1
  reinterpret1/1 -> lsb_out1/1

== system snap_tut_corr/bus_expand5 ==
  bus_in : Inport
  reinterpret1 : xbsIndex_r4/Reinterpret  force_arith_type=on  arith_type=Unsigned  force_bin_pt=on  bin_pt=0  block_type=reinterpret
  reinterpret2 : xbsIndex_r4/Reinterpret  force_arith_type=on  arith_type=Unsigned  force_bin_pt=on  bin_pt=0  block_type=reinterpret
  reinterpret3 : xbsIndex_r4/Reinterpret  force_arith_type=on  arith_type=Unsigned  force_bin_pt=on  bin_pt=0  block_type=reinterpret
  slice1 : xbsIndex_r4/Slice  nbits=8  boolean_output=off  mode=Upper Bit Location + Width  bit1=-16  base1=MSB of Input  bit0=0  base0=LSB of Input  dbl_ovrd=off  block_type=slice
  slice2 : xbsIndex_r4/Slice  nbits=8  boolean_output=off  mode=Upper Bit Location + Width  bit1=-8  base1=MSB of Input  bit0=0  base0=LSB of Input  dbl_ovrd=off  block_type=slice
  slice3 : xbsIndex_r4/Slice  nbits=8  boolean_output=off  mode=Upper Bit Location + Width  bit1=0  base1=MSB of Input  bit0=0  base0=LSB of Input  dbl_ovrd=off  block_type=slice
  msb_out3 : Outport
  out2 : Outport  Port=2
  lsb_out1 : Outport  Port=3
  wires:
  bus_in/1 -> slice3/1, slice2/1, slice1/1
  slice3/1 -> reinterpret3/1
  reinterpret3/1 -> msb_out3/1
  slice2/1 -> reinterpret2/1
  reinterpret2/1 -> out2/1
  slice1/1 -> reinterpret1/1
  reinterpret1/1 -> lsb_out1/1

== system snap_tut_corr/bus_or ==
  In1 : Inport
  Logical5 : xbsIndex_r4/Logical  logical_function=OR  inputs=3  en=off  latency=2  precision=Full  arith_type=Unsigned  n_bits=16  bin_pt=0  align_bp=on  dbl_ovrd=off  block_type=logical
  bus_expand4 : Subsystem  AncestorBlock=casper_library_flow_control/bus_expand  mask(bus_expand){mode=divisions of equal size, outputNum=3, outputWidth=1, outputBinaryPt=0, outputArithmeticType=2, show_format=off, outputToWorkspace=off, variablePrefix=out, outputToModelAsWell=on}
      mask prompts: outputNum "Number of outputs:"; outputWidth "Output width:"; outputBinaryPt "Output binary point position:"; outputArithmeticType "Output arithmetic type (ufix=0, fix=1, bool=2):"; show_format "Print format string?"; outputToWorkspace "Output to workspace?"; variablePrefix "Variable name prefix:"; outputToModelAsWell "Output to model as well?"
      mask help: Expands a 'bus' made using a bus_create or Xilinx concat block. The input will be divided into the specified number of outputs with the specified arithmetic types. Divisions are made from most significant bit.
      mask init:
      | bus_expand_init(gcb,...
      |     'mode', mode, ...
      |     'outputNum', outputNum, ...
      |     'outputWidth', outputWidth, ...
      |     'outputBinaryPt', outputBinaryPt, ...
      |     'outputArithmeticType', outputArithmeticType, ...
      |     'show_format', show_format, ...
      |     'outputToWorkspace', outputToWorkspace, ...
      |     'variablePrefix', variablePrefix, ...
      |     'outputToModelAsWell', outputToModelAsWell);
  Out1 : Outport
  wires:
  Logical5/1 -> Out1/1
  In1/1 -> bus_expand4/1(bus_in)
  bus_expand4/1(msb_out3) -> Logical5/1
  bus_expand4/2(out2) -> Logical5/2
  bus_expand4/3(lsb_out1) -> Logical5/3

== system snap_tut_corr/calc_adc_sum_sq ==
  In1 : Inport
  In2 : Inport  Port=2
  In3 : Inport  Port=3
  In4 : Inport  Port=4
  Accumulator : xbsIndex_r4/Accumulator  operation=Add  n_bits=32  overflow=Wrap  scale=1  rst=on  hasbypass=off  infoeditControl=reset for floating point data type must be asserted for a minimum of 2 cycles  en=off  latency=1  msb_inp=100  msb=100  lsb=-100  use_behavioral_HDL=on  implementation=Fabric  dbl_ovrd=off  block_type=accum
  Convert1 : xbsIndex_r4/Convert  gui_display_data_type=Fixed-point  arith_type=Unsigned  n_bits=32  bin_pt=0  float_type=Single  exp_bits=8  fraction_bits=24  quantization=Truncate  overflow=Wrap  en=off  latency=0  pipeline=off  dbl_ovrd=off  block_type=convert
  Convert2 : xbsIndex_r4/Convert  gui_display_data_type=Boolean  arith_type=Boolean  n_bits=32  bin_pt=0  float_type=Single  exp_bits=8  fraction_bits=24  quantization=Truncate  overflow=Wrap  en=off  latency=0  pipeline=off  dbl_ovrd=off  block_type=convert
  Counter : xbsIndex_r4/Counter  cnt_type=Free Running  cnt_to=Inf  operation=Up  start_count=0  cnt_by_val=1  arith_type=Unsigned  n_bits=2  bin_pt=0  load_pin=off  rst=off  en=off  explicit_period=off  period=1  use_behavioral_HDL=off  implementation=Fabric  use_rpm=on  dbl_ovrd=off  block_type=counter
  Counter1 : xbsIndex_r4/Counter  cnt_type=Free Running  cnt_to=Inf  operation=Up  start_count=0  cnt_by_val=1  arith_type=Unsigned  n_bits=16  bin_pt=0  load_pin=off  rst=off  en=off  explicit_period=off  period=1  use_behavioral_HDL=off  implementation=Fabric  use_rpm=on  dbl_ovrd=off  block_type=counter
  Mult : xbsIndex_r4/Mult  precision=Full  arith_type="Signed  (2's comp)"  n_bits=8  bin_pt=2  quantization=Truncate  overflow=Wrap  en=off  latency=2  use_behavioral_HDL=on  opt=Speed  use_embedded=on  optimum_pipeline=off  pipeline=on  dbl_ovrd=off  use_rpm=on  placement_style=Rectangular shape  block_type=mult
  Mux : xbsIndex_r4/Mux  inputs=4  en=off  latency=1  precision=Full  arith_type="Signed  (2's comp)"  n_bits=8  bin_pt=2  quantization=Truncate  overflow=Wrap  dbl_ovrd=off  block_type=mux
  Register : xbsIndex_r4/Register  init=0  rst=off  en=on  dbl_ovrd=off  block_type=register
  Slice : xbsIndex_r4/Slice  nbits=1  boolean_output=off  mode=Upper Bit Location + Width  bit1=0  base1=MSB of Input  bit0=0  base0=LSB of Input  dbl_ovrd=off  block_type=slice
  edge_detect2 : Subsystem  AncestorBlock=casper_library_misc/edge_detect  mask(edge_detect){edge=Falling, polarity=Active High, x_in=[0 0.08 0.08 0.16 0.16 0.24 0.24 0.32 0.32 0.4], y_in=[1  1 -1 -1 -1 -1 -1 -1 -1 -1], x_out=[0.6 0.68 0.68 0.76 0.76 0.84 0.84 0.92 0.92 1], y_out=[-1 -1  1  1 -1 -1 -1 -1 -1 -1]}
      mask prompts: edge "Edge Type"; polarity "Output Polarity"; x_in "Input X Positions"; y_in "Input Y Positions"; x_out "Output X Positions"; y_out "Output Y Positions"
      mask help: Output is active for one-cycle after each edge of the specified type (i.e. rising, falling or both).
      mask init:
      | edge_detect_init(gcb,...
      |     'edge',edge,...
      |     'polarity',polarity,...
      |     'x_in',x_in,...
      |     'x_out',x_out,...
      |     'y_in',y_in,...
      |     'y_out',y_out);
      | 
      | x_in_num=str2num(getfield(getfield(get_param(gcb,'UserData'),'parameters'),'x_in'));
      | x_out_num=str2num(getfield(getfield(get_param(gcb,'UserData'),'parameters'),'x_out'));
      | y_in_num=str2num(getfield(getfield(get_param(gcb,'UserData'),'parameters'),'y_in'));
      | y_out_num=str2num(getfield(getfield(get_param(gcb,'UserData'),'parameters'),'y_out'));
  sum_sq : Outport
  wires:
  Mult/1 -> Accumulator/1
  Accumulator/1 -> Register/1
  Register/1 -> Convert1/1
  Mux/1 -> Mult/1, Mult/2
  Counter/1 -> Mux/1
  Counter1/1 -> Slice/1
  Slice/1 -> edge_detect2/1(in)
  edge_detect2/1(out) -> Convert2/1
  In1/1 -> Mux/2
  In3/1 -> Mux/3
  In2/1 -> Mux/4
  In4/1 -> Mux/5
  Convert1/1 -> sum_sq/1
  Convert2/1 -> Accumulator/2, Register/2

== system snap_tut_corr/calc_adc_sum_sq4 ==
  In1 : Inport
  In2 : Inport  Port=2
  In3 : Inport  Port=3
  In4 : Inport  Port=4
  Accumulator : xbsIndex_r4/Accumulator  operation=Add  n_bits=32  overflow=Wrap  scale=1  rst=on  hasbypass=off  infoeditControl=reset for floating point data type must be asserted for a minimum of 2 cycles  en=off  latency=1  msb_inp=100  msb=100  lsb=-100  use_behavioral_HDL=on  implementation=Fabric  dbl_ovrd=off  block_type=accum
  Convert1 : xbsIndex_r4/Convert  gui_display_data_type=Fixed-point  arith_type=Unsigned  n_bits=32  bin_pt=0  float_type=Single  exp_bits=8  fraction_bits=24  quantization=Truncate  overflow=Wrap  en=off  latency=0  pipeline=off  dbl_ovrd=off  block_type=convert
  Convert2 : xbsIndex_r4/Convert  gui_display_data_type=Boolean  arith_type=Boolean  n_bits=32  bin_pt=0  float_type=Single  exp_bits=8  fraction_bits=24  quantization=Truncate  overflow=Wrap  en=off  latency=0  pipeline=off  dbl_ovrd=off  block_type=convert
  Counter : xbsIndex_r4/Counter  cnt_type=Free Running  cnt_to=Inf  operation=Up  start_count=0  cnt_by_val=1  arith_type=Unsigned  n_bits=2  bin_pt=0  load_pin=off  rst=off  en=off  explicit_period=off  period=1  use_behavioral_HDL=off  implementation=Fabric  use_rpm=on  dbl_ovrd=off  block_type=counter
  Counter1 : xbsIndex_r4/Counter  cnt_type=Free Running  cnt_to=Inf  operation=Up  start_count=0  cnt_by_val=1  arith_type=Unsigned  n_bits=16  bin_pt=0  load_pin=off  rst=off  en=off  explicit_period=off  period=1  use_behavioral_HDL=off  implementation=Fabric  use_rpm=on  dbl_ovrd=off  block_type=counter
  Mult : xbsIndex_r4/Mult  precision=Full  arith_type="Signed  (2's comp)"  n_bits=8  bin_pt=2  quantization=Truncate  overflow=Wrap  en=off  latency=2  use_behavioral_HDL=on  opt=Speed  use_embedded=on  optimum_pipeline=off  pipeline=on  dbl_ovrd=off  use_rpm=on  placement_style=Rectangular shape  block_type=mult
  Mux : xbsIndex_r4/Mux  inputs=4  en=off  latency=1  precision=Full  arith_type="Signed  (2's comp)"  n_bits=8  bin_pt=2  quantization=Truncate  overflow=Wrap  dbl_ovrd=off  block_type=mux
  Register : xbsIndex_r4/Register  init=0  rst=off  en=on  dbl_ovrd=off  block_type=register
  Slice : xbsIndex_r4/Slice  nbits=1  boolean_output=off  mode=Upper Bit Location + Width  bit1=0  base1=MSB of Input  bit0=0  base0=LSB of Input  dbl_ovrd=off  block_type=slice
  edge_detect2 : Subsystem  AncestorBlock=casper_library_misc/edge_detect  mask(edge_detect){edge=Falling, polarity=Active High, x_in=[0 0.08 0.08 0.16 0.16 0.24 0.24 0.32 0.32 0.4], y_in=[1  1 -1 -1 -1 -1 -1 -1 -1 -1], x_out=[0.6 0.68 0.68 0.76 0.76 0.84 0.84 0.92 0.92 1], y_out=[-1 -1  1  1 -1 -1 -1 -1 -1 -1]}
      mask prompts: edge "Edge Type"; polarity "Output Polarity"; x_in "Input X Positions"; y_in "Input Y Positions"; x_out "Output X Positions"; y_out "Output Y Positions"
      mask help: Output is active for one-cycle after each edge of the specified type (i.e. rising, falling or both).
      mask init:
      | edge_detect_init(gcb,...
      |     'edge',edge,...
      |     'polarity',polarity,...
      |     'x_in',x_in,...
      |     'x_out',x_out,...
      |     'y_in',y_in,...
      |     'y_out',y_out);
      | 
      | x_in_num=str2num(getfield(getfield(get_param(gcb,'UserData'),'parameters'),'x_in'));
      | x_out_num=str2num(getfield(getfield(get_param(gcb,'UserData'),'parameters'),'x_out'));
      | y_in_num=str2num(getfield(getfield(get_param(gcb,'UserData'),'parameters'),'y_in'));
      | y_out_num=str2num(getfield(getfield(get_param(gcb,'UserData'),'parameters'),'y_out'));
  sum_sq : Outport
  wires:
  Convert1/1 -> sum_sq/1
  In4/1 -> Mux/5
  In2/1 -> Mux/4
  In3/1 -> Mux/3
  In1/1 -> Mux/2
  edge_detect2/1(out) -> Convert2/1
  Slice/1 -> edge_detect2/1(in)
  Counter1/1 -> Slice/1
  Counter/1 -> Mux/1
  Mux/1 -> Mult/2, Mult/1
  Register/1 -> Convert1/1
  Accumulator/1 -> Register/1
  Mult/1 -> Accumulator/1
  Convert2/1 -> Register/2, Accumulator/2

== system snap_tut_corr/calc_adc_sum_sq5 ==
  In1 : Inport
  In2 : Inport  Port=2
  In3 : Inport  Port=3
  In4 : Inport  Port=4
  Accumulator : xbsIndex_r4/Accumulator  operation=Add  n_bits=32  overflow=Wrap  scale=1  rst=on  hasbypass=off  infoeditControl=reset for floating point data type must be asserted for a minimum of 2 cycles  en=off  latency=1  msb_inp=100  msb=100  lsb=-100  use_behavioral_HDL=on  implementation=Fabric  dbl_ovrd=off  block_type=accum
  Convert1 : xbsIndex_r4/Convert  gui_display_data_type=Fixed-point  arith_type=Unsigned  n_bits=32  bin_pt=0  float_type=Single  exp_bits=8  fraction_bits=24  quantization=Truncate  overflow=Wrap  en=off  latency=0  pipeline=off  dbl_ovrd=off  block_type=convert
  Convert2 : xbsIndex_r4/Convert  gui_display_data_type=Boolean  arith_type=Boolean  n_bits=32  bin_pt=0  float_type=Single  exp_bits=8  fraction_bits=24  quantization=Truncate  overflow=Wrap  en=off  latency=0  pipeline=off  dbl_ovrd=off  block_type=convert
  Counter : xbsIndex_r4/Counter  cnt_type=Free Running  cnt_to=Inf  operation=Up  start_count=0  cnt_by_val=1  arith_type=Unsigned  n_bits=2  bin_pt=0  load_pin=off  rst=off  en=off  explicit_period=off  period=1  use_behavioral_HDL=off  implementation=Fabric  use_rpm=on  dbl_ovrd=off  block_type=counter
  Counter1 : xbsIndex_r4/Counter  cnt_type=Free Running  cnt_to=Inf  operation=Up  start_count=0  cnt_by_val=1  arith_type=Unsigned  n_bits=16  bin_pt=0  load_pin=off  rst=off  en=off  explicit_period=off  period=1  use_behavioral_HDL=off  implementation=Fabric  use_rpm=on  dbl_ovrd=off  block_type=counter
  Mult : xbsIndex_r4/Mult  precision=Full  arith_type="Signed  (2's comp)"  n_bits=8  bin_pt=2  quantization=Truncate  overflow=Wrap  en=off  latency=2  use_behavioral_HDL=on  opt=Speed  use_embedded=on  optimum_pipeline=off  pipeline=on  dbl_ovrd=off  use_rpm=on  placement_style=Rectangular shape  block_type=mult
  Mux : xbsIndex_r4/Mux  inputs=4  en=off  latency=1  precision=Full  arith_type="Signed  (2's comp)"  n_bits=8  bin_pt=2  quantization=Truncate  overflow=Wrap  dbl_ovrd=off  block_type=mux
  Register : xbsIndex_r4/Register  init=0  rst=off  en=on  dbl_ovrd=off  block_type=register
  Slice : xbsIndex_r4/Slice  nbits=1  boolean_output=off  mode=Upper Bit Location + Width  bit1=0  base1=MSB of Input  bit0=0  base0=LSB of Input  dbl_ovrd=off  block_type=slice
  edge_detect2 : Subsystem  AncestorBlock=casper_library_misc/edge_detect  mask(edge_detect){edge=Falling, polarity=Active High, x_in=[0 0.08 0.08 0.16 0.16 0.24 0.24 0.32 0.32 0.4], y_in=[1  1 -1 -1 -1 -1 -1 -1 -1 -1], x_out=[0.6 0.68 0.68 0.76 0.76 0.84 0.84 0.92 0.92 1], y_out=[-1 -1  1  1 -1 -1 -1 -1 -1 -1]}
      mask prompts: edge "Edge Type"; polarity "Output Polarity"; x_in "Input X Positions"; y_in "Input Y Positions"; x_out "Output X Positions"; y_out "Output Y Positions"
      mask help: Output is active for one-cycle after each edge of the specified type (i.e. rising, falling or both).
      mask init:
      | edge_detect_init(gcb,...
      |     'edge',edge,...
      |     'polarity',polarity,...
      |     'x_in',x_in,...
      |     'x_out',x_out,...
      |     'y_in',y_in,...
      |     'y_out',y_out);
      | 
      | x_in_num=str2num(getfield(getfield(get_param(gcb,'UserData'),'parameters'),'x_in'));
      | x_out_num=str2num(getfield(getfield(get_param(gcb,'UserData'),'parameters'),'x_out'));
      | y_in_num=str2num(getfield(getfield(get_param(gcb,'UserData'),'parameters'),'y_in'));
      | y_out_num=str2num(getfield(getfield(get_param(gcb,'UserData'),'parameters'),'y_out'));
  sum_sq : Outport
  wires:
  Mult/1 -> Accumulator/1
  Accumulator/1 -> Register/1
  Register/1 -> Convert1/1
  Mux/1 -> Mult/1, Mult/2
  Counter/1 -> Mux/1
  Counter1/1 -> Slice/1
  Slice/1 -> edge_detect2/1(in)
  edge_detect2/1(out) -> Convert2/1
  In1/1 -> Mux/2
  In3/1 -> Mux/3
  In2/1 -> Mux/4
  In4/1 -> Mux/5
  Convert1/1 -> sum_sq/1
  Convert2/1 -> Accumulator/2, Register/2

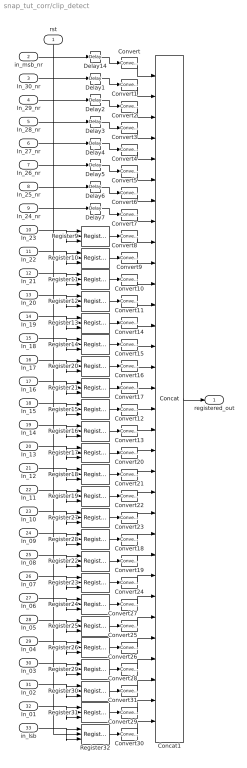
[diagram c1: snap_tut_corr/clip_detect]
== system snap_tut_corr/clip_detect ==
  rst : Inport
  in_msb_nr : Inport  Port=2
  In_30_nr : Inport  Port=3
  In_29_nr : Inport  Port=4
  In_28_nr : Inport  Port=5
  In_27_nr : Inport  Port=6
  In_26_nr : Inport  Port=7
  In_25_nr : Inport  Port=8
  In_24_nr : Inport  Port=9
  In_23 : Inport  Port=10
  In_22 : Inport  Port=11
  In_21 : Inport  Port=12
  In_20 : Inport  Port=13
  In_19 : Inport  Port=14
  In_18 : Inport  Port=15
  In_17 : Inport  Port=16
  In_16 : Inport  Port=17
  In_15 : Inport  Port=18
  In_14 : Inport  Port=19
  In_13 : Inport  Port=20
  In_12 : Inport  Port=21
  In_11 : Inport  Port=22
  In_10 : Inport  Port=23
  In_09 : Inport  Port=24
  In_08 : Inport  Port=25
  In_07 : Inport  Port=26
  In_06 : Inport  Port=27
  In_05 : Inport  Port=28
  In_04 : Inport  Port=29
  In_03 : Inport  Port=30
  In_02 : Inport  Port=31
  In_01 : Inport  Port=32
  in_lsb : Inport  Port=33
  Concat1 : xbsIndex_r4/Concat  num_inputs=32  dbl_ovrd=off  block_type=concat
  Convert{,1..31} (32 alike) : xbsIndex_r4/Convert  gui_display_data_type=Fixed-point  arith_type=Unsigned  n_bits=1  bin_pt=0  float_type=Single  exp_bits=8  fraction_bits=24  quantization=Truncate  overflow=Wrap  en=off  latency=0  pipeline=off  dbl_ovrd=off  block_type=convert
  Delay{1..7,14} (8 alike) : xbsIndex_r4/Delay  rst=off  infoeditControl=Selection of Reset will increase slice count due to use of real FFs and instead of SRLs  en=off  latency=1  reg_retiming=on  dbl_ovrd=off  block_type=delay
  Register{9..32} (24 alike) : xbsIndex_r4/Register  init=0  rst=on  en=on  dbl_ovrd=off  block_type=register
  registered_out : Outport
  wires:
  Concat1/1 -> registered_out/1
  rst/1 -> Register11/2, Register12/2, Register14/2, Register20/2, Register21/2, Register15/2, Register16/2, Register17/2, Register19/2, Register23/2, Register24/2, Register26/2, Register29/2, Register30/2, Register31/2, Register32/2, Register25/2, Register22/2, Register28/2, Register27/2, Register18/2, Register13/2, Register10/2, Register9/2
  in_msb_nr/1 -> Delay14/1
  Convert/1 -> Concat1/1
  In_30_nr/1 -> Delay1/1
  Convert1/1 -> Concat1/2
  Convert2/1 -> Concat1/3
  Convert3/1 -> Concat1/4
  Convert4/1 -> Concat1/5
  Convert5/1 -> Concat1/6
  Convert6/1 -> Concat1/7
  Convert7/1 -> Concat1/8
  Convert8/1 -> Concat1/9
  Convert9/1 -> Concat1/10
  Convert10/1 -> Concat1/11
  Convert11/1 -> Concat1/12
  Convert14/1 -> Concat1/13
  Convert15/1 -> Concat1/14
  Convert16/1 -> Concat1/15
  Convert17/1 -> Concat1/16
  Convert12/1 -> Concat1/17
  Convert13/1 -> Concat1/18
  Convert20/1 -> Concat1/19
  Convert21/1 -> Concat1/20
  Convert22/1 -> Concat1/21
  Convert23/1 -> Concat1/22
  Convert18/1 -> Concat1/23
  Convert19/1 -> Concat1/24
  Convert24/1 -> Concat1/25
  In_29_nr/1 -> Delay2/1
  In_28_nr/1 -> Delay3/1
  In_27_nr/1 -> Delay4/1
  In_26_nr/1 -> Delay5/1
  In_25_nr/1 -> Delay6/1
  In_24_nr/1 -> Delay7/1
  Register9/1 -> Convert8/1
  Register10/1 -> Convert9/1
  Register11/1 -> Convert10/1
  Register12/1 -> Convert11/1
  Register13/1 -> Convert14/1
  Register14/1 -> Convert15/1
  Register20/1 -> Convert16/1
  Register21/1 -> Convert17/1
  Register15/1 -> Convert12/1
  Register16/1 -> Convert13/1
  Register17/1 -> Convert20/1
  Register18/1 -> Convert21/1
  Register19/1 -> Convert22/1
  Register27/1 -> Convert23/1
  Register28/1 -> Convert18/1
  Register22/1 -> Convert19/1
  Register23/1 -> Convert24/1
  In_23/1 -> Register9/3, Register9/1
  In_22/1 -> Register10/3, Register10/1
  In_21/1 -> Register11/1, Register11/3
  In_20/1 -> Register12/3, Register12/1
  In_19/1 -> Register13/1, Register13/3
  In_18/1 -> Register14/3, Register14/1
  In_17/1 -> Register20/1, Register20/3
  In_16/1 -> Register21/1, Register21/3
  In_15/1 -> Register15/1, Register15/3
  In_14/1 -> Register16/3, Register16/1
  In_13/1 -> Register17/1, Register17/3
  In_12/1 -> Register18/3, Register18/1
  In_11/1 -> Register19/1, Register19/3
  In_10/1 -> Register27/3, Register27/1
  In_09/1 -> Register28/3, Register28/1
  In_08/1 -> Register22/3, Register22/1
  In_07/1 -> Register23/1, Register23/3
  In_06/1 -> Register24/3, Register24/1
  In_05/1 -> Register25/1, Register25/3
  In_04/1 -> Register26/3, Register26/1
  In_03/1 -> Register29/1, Register29/3
  In_02/1 -> Register30/3, Register30/1
  In_01/1 -> Register31/1, Register31/3
  Convert27/1 -> Concat1/26
  Convert25/1 -> Concat1/27
  Convert26/1 -> Concat1/28
  Convert28/1 -> Concat1/29
  Register24/1 -> Convert27/1
  Register25/1 -> Convert25/1
  Register26/1 -> Convert26/1
  Register29/1 -> Convert28/1
  Convert31/1 -> Concat1/30
  Convert29/1 -> Concat1/31
  Convert30/1 -> Concat1/32
  in_lsb/1 -> Register32/3, Register32/1
  Register30/1 -> Convert31/1
  Register31/1 -> Convert29/1
  Register32/1 -> Convert30/1
  Delay14/1 -> Convert/1
  Delay1/1 -> Convert1/1
  Delay2/1 -> Convert2/1
  Delay3/1 -> Convert3/1
  Delay4/1 -> Convert4/1
  Delay5/1 -> Convert5/1
  Delay6/1 -> Convert6/1
  Delay7/1 -> Convert7/1

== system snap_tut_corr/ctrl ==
  sim_1 : Inport
  convert1_1 : DataTypeConversion  OutDataTypeStr=fixdt('ufix32_En0')
  convert2_1 : DataTypeConversion  OutDataTypeStr=fixdt('ufix32_En0')  ConvertRealWorld=Stored Integer (SI)
  gain_1 : Gain
  io_delay : xbsIndex_r4/Delay  rst=off  infoeditControl=Selection of Reset will increase slice count due to use of real FFs and instead of SRLs  en=off  latency=0  reg_retiming=on  dbl_ovrd=off  block_type=delay
  reint1 : xbsIndex_r4/Reinterpret  force_arith_type=on  arith_type=Unsigned  force_bin_pt=on  bin_pt=0  block_type=reinterpret
  slice_reg : xbsIndex_r4/Slice  nbits=32  boolean_output=off  mode=Lower Bit Location + Width  bit1=0  base1=MSB of Input  bit0=0  base0=LSB of Input  dbl_ovrd=off  block_type=slice
  snap_tut_corr_ctrl_user_data_out : xbsIndex_r4/Gateway In  gui_display_data_type=Fixed-point  arith_type=Unsigned  n_bits=32  bin_pt=0  preci_type=Single  exp_width=8  frac_width=24  rows=1  columns=1  quantization="Round  (unbiased: +/- Inf)"  overflow=Saturate  period=1  UseAsADC=off  ADCChannel='1'  interface=None  automatic_assignment=on  address_offset=hex2dec('00')  intf_name=''  intf_description=''  default_value=0  timing_constraint=None  locs_specified=off  LOCs={}  io_standard={}  inherit_from_input=off  hdl_port=on  dbl_ovrd=off  block_type=gatewayin
  in_reg : Outport
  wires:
  snap_tut_corr_ctrl_user_data_out/1 -> io_delay/1
  sim_1/1 -> convert1_1/1
  convert1_1/1 -> convert2_1/1
  convert2_1/1 -> gain_1/1
  gain_1/1 -> snap_tut_corr_ctrl_user_data_out/1
  io_delay/1 -> slice_reg/1
  slice_reg/1 -> reint1/1
  reint1/1 -> in_reg/1

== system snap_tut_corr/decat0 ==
  In1 : Inport
  Reinterpret{1..4} (4 alike) : xbsIndex_r4/Reinterpret  force_arith_type=on  arith_type="Signed  (2's comp)"  force_bin_pt=on  bin_pt=0  block_type=reinterpret
  Slice15 : xbsIndex_r4/Slice  nbits=8  boolean_output=off  mode=Lower Bit Location + Width  bit1=0  base1=MSB of Input  bit0=8  base0=LSB of Input  dbl_ovrd=off  block_type=slice
  Slice16 : xbsIndex_r4/Slice  nbits=8  boolean_output=off  mode=Lower Bit Location + Width  bit1=0  base1=MSB of Input  bit0=16  base0=LSB of Input  dbl_ovrd=off  block_type=slice
  Slice17 : xbsIndex_r4/Slice  nbits=8  boolean_output=off  mode=Lower Bit Location + Width  bit1=0  base1=MSB of Input  bit0=24  base0=LSB of Input  dbl_ovrd=off  block_type=slice
  Slice9 : xbsIndex_r4/Slice  nbits=8  boolean_output=off  mode=Lower Bit Location + Width  bit1=0  base1=MSB of Input  bit0=0  base0=LSB of Input  dbl_ovrd=off  block_type=slice
  Out1 : Outport
  Out2 : Outport  Port=2
  Out3 : Outport  Port=3
  Out4 : Outport  Port=4
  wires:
  Reinterpret4/1 -> Out4/1
  Reinterpret3/1 -> Out3/1
  Reinterpret1/1 -> Out2/1
  Reinterpret2/1 -> Out1/1
  Slice9/1 -> Reinterpret4/1
  Slice15/1 -> Reinterpret3/1
  Slice16/1 -> Reinterpret1/1
  Slice17/1 -> Reinterpret2/1
  In1/1 -> Slice15/1, Slice9/1, Slice16/1, Slice17/1

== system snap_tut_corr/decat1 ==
  In1 : Inport
  Reinterpret{1..4} (4 alike) : xbsIndex_r4/Reinterpret  force_arith_type=on  arith_type="Signed  (2's comp)"  force_bin_pt=on  bin_pt=0  block_type=reinterpret
  Slice15 : xbsIndex_r4/Slice  nbits=8  boolean_output=off  mode=Lower Bit Location + Width  bit1=0  base1=MSB of Input  bit0=8  base0=LSB of Input  dbl_ovrd=off  block_type=slice
  Slice16 : xbsIndex_r4/Slice  nbits=8  boolean_output=off  mode=Lower Bit Location + Width  bit1=0  base1=MSB of Input  bit0=16  base0=LSB of Input  dbl_ovrd=off  block_type=slice
  Slice17 : xbsIndex_r4/Slice  nbits=8  boolean_output=off  mode=Lower Bit Location + Width  bit1=0  base1=MSB of Input  bit0=24  base0=LSB of Input  dbl_ovrd=off  block_type=slice
  Slice9 : xbsIndex_r4/Slice  nbits=8  boolean_output=off  mode=Lower Bit Location + Width  bit1=0  base1=MSB of Input  bit0=0  base0=LSB of Input  dbl_ovrd=off  block_type=slice
  Out1 : Outport
  Out2 : Outport  Port=2
  Out3 : Outport  Port=3
  Out4 : Outport  Port=4
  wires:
  In1/1 -> Slice17/1, Slice16/1, Slice9/1, Slice15/1
  Slice17/1 -> Reinterpret2/1
  Slice16/1 -> Reinterpret1/1
  Slice15/1 -> Reinterpret3/1
  Slice9/1 -> Reinterpret4/1
  Reinterpret2/1 -> Out1/1
  Reinterpret1/1 -> Out2/1
  Reinterpret3/1 -> Out3/1
  Reinterpret4/1 -> Out4/1
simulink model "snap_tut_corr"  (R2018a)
settings: Solver=VariableStepDiscrete  StartTime=0.0  StopTime=100  RelTol=1e-3
undefined symbols (not defined in the file): Area, behavioral, Behavioral, Bit, Both, BRAM, bram, c, core, d, Falling, getfield, hamming, hex2dec, led, Location, logic, Lower, Minimum_Area, out, quant0, quant1, quant2, reg, repmat, Rising, ROACH, ROACH2, SNAP, Speed, sync_in, Truncate, Unsigned, Upper, Width, Wrap, xc7k160t
libraries: xbsIndex_r4 x17901, casper_library_misc x29, xbsReplacements_r4 x20, casper_library_delays x14, xps_library x5
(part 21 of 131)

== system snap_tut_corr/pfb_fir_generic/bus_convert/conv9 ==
  note: (ones_bit & 1) -> round-to-even (ones_bit ^ 1) -> round-to-odd (sign_bit & 1)-> round-to-zero (sign_bit ^ 1) -> round-to-inf (X ~| 1) -> round half down (X | 1) -> round half up
  in : Inport
  Concat : xbsIndex_r4/Concat  num_inputs=2  dbl_ovrd=off  block_type=concat
  Constant : xbsIndex_r4/Constant  const=1  gui_display_data_type=Fixed-point  arith_type=Unsigned  n_bits=1  bin_pt=0  preci_type=Single  exp_width=8  frac_width=24  explicit_period=off  period=1  equ=P=C  opselect=C  inp2=PCIN>>17  opr=+  inp1=P  carry=CIN  dbl_ovrd=off  block_type=constant
  Reinterpret : xbsIndex_r4/Reinterpret  force_arith_type=on  arith_type=Unsigned  force_bin_pt=on  bin_pt=0  block_type=reinterpret
  adder : xbsIndex_r4/AddSub  mode=Addition  use_carryin=off  use_carryout=off  en=off  latency=1  precision=User Defined  arith_type="Signed  (2's comp)"  n_bits=18  bin_pt=17  quantization=Truncate  overflow=Wrap  use_behavioral_HDL=off  hw_selection=Fabric  pipelined=on  use_rpm=on  dbl_ovrd=off  block_type=addsub
  almost_half : xbsIndex_r4/Constant  const=255  gui_display_data_type=Fixed-point  arith_type=Unsigned  n_bits=26  bin_pt=0  preci_type=Single  exp_width=8  frac_width=24  explicit_period=off  period=1  equ=P=C  opselect=C  inp2=PCIN>>17  opr=+  inp1=P  carry=CIN  dbl_ovrd=off  block_type=constant
  bit : xbsIndex_r4/Slice  nbits=1  boolean_output=off  mode=Lower Bit Location + Width  bit1=0  base1=MSB of Input  bit0=8  base0=LSB of Input  dbl_ovrd=off  block_type=slice
  force1 : xbsIndex_r4/Reinterpret  force_arith_type=on  arith_type="Signed  (2's comp)"  force_bin_pt=on  bin_pt=26  block_type=reinterpret
  force2 : xbsIndex_r4/Reinterpret  force_arith_type=off  arith_type="Signed  (2's comp)"  force_bin_pt=on  bin_pt=26  block_type=reinterpret
  tweak_op : xbsIndex_r4/Logical  logical_function=AND  inputs=2  en=off  latency=0  precision=Full  arith_type=Unsigned  n_bits=8  bin_pt=2  align_bp=on  dbl_ovrd=off  block_type=logical
  out : Outport
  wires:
  tweak_op/1 -> Concat/2
  Constant/1 -> tweak_op/2
  bit/1 -> tweak_op/1
  almost_half/1 -> force2/1
  in/1 -> Reinterpret/1, bit/1
  Concat/1 -> force1/1
  Reinterpret/1 -> Concat/1
  force1/1 -> adder/1
  force2/1 -> adder/2
  adder/1 -> out/1

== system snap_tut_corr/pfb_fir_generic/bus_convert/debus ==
  bus_in : Inport
  reinterpret{1..12} (12 alike) : xbsIndex_r4/Reinterpret  force_arith_type=on  arith_type="Signed  (2's comp)"  force_bin_pt=on  bin_pt=25  block_type=reinterpret
  slice1 : xbsIndex_r4/Slice  nbits=28  boolean_output=off  mode=Upper Bit Location + Width  bit1=-308  base1=MSB of Input  bit0=0  base0=LSB of Input  dbl_ovrd=off  block_type=slice
  slice10 : xbsIndex_r4/Slice  nbits=28  boolean_output=off  mode=Upper Bit Location + Width  bit1=-56  base1=MSB of Input  bit0=0  base0=LSB of Input  dbl_ovrd=off  block_type=slice
  slice11 : xbsIndex_r4/Slice  nbits=28  boolean_output=off  mode=Upper Bit Location + Width  bit1=-28  base1=MSB of Input  bit0=0  base0=LSB of Input  dbl_ovrd=off  block_type=slice
  slice12 : xbsIndex_r4/Slice  nbits=28  boolean_output=off  mode=Upper Bit Location + Width  bit1=0  base1=MSB of Input  bit0=0  base0=LSB of Input  dbl_ovrd=off  block_type=slice
  slice2 : xbsIndex_r4/Slice  nbits=28  boolean_output=off  mode=Upper Bit Location + Width  bit1=-280  base1=MSB of Input  bit0=0  base0=LSB of Input  dbl_ovrd=off  block_type=slice
  slice3 : xbsIndex_r4/Slice  nbits=28  boolean_output=off  mode=Upper Bit Location + Width  bit1=-252  base1=MSB of Input  bit0=0  base0=LSB of Input  dbl_ovrd=off  block_type=slice
  slice4 : xbsIndex_r4/Slice  nbits=28  boolean_output=off  mode=Upper Bit Location + Width  bit1=-224  base1=MSB of Input  bit0=0  base0=LSB of Input  dbl_ovrd=off  block_type=slice
  slice5 : xbsIndex_r4/Slice  nbits=28  boolean_output=off  mode=Upper Bit Location + Width  bit1=-196  base1=MSB of Input  bit0=0  base0=LSB of Input  dbl_ovrd=off  block_type=slice
  slice6 : xbsIndex_r4/Slice  nbits=28  boolean_output=off  mode=Upper Bit Location + Width  bit1=-168  base1=MSB of Input  bit0=0  base0=LSB of Input  dbl_ovrd=off  block_type=slice
  slice7 : xbsIndex_r4/Slice  nbits=28  boolean_output=off  mode=Upper Bit Location + Width  bit1=-140  base1=MSB of Input  bit0=0  base0=LSB of Input  dbl_ovrd=off  block_type=slice
  slice8 : xbsIndex_r4/Slice  nbits=28  boolean_output=off  mode=Upper Bit Location + Width  bit1=-112  base1=MSB of Input  bit0=0  base0=LSB of Input  dbl_ovrd=off  block_type=slice
  slice9 : xbsIndex_r4/Slice  nbits=28  boolean_output=off  mode=Upper Bit Location + Width  bit1=-84  base1=MSB of Input  bit0=0  base0=LSB of Input  dbl_ovrd=off  block_type=slice
  msb_out12 : Outport
  out11 : Outport  Port=2
  out10 : Outport  Port=3
  out9 : Outport  Port=4
  out8 : Outport  Port=5
  out7 : Outport  Port=6
  out6 : Outport  Port=7
  out5 : Outport  Port=8
  out4 : Outport  Port=9
  out3 : Outport  Port=10
  out2 : Outport  Port=11
  lsb_out1 : Outport  Port=12
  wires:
  bus_in/1 -> slice12/1, slice11/1, slice10/1, slice9/1, slice8/1, slice7/1, slice6/1, slice5/1, slice4/1, slice3/1, slice2/1, slice1/1
  slice12/1 -> reinterpret12/1
  reinterpret12/1 -> msb_out12/1
  slice11/1 -> reinterpret11/1
  reinterpret11/1 -> out11/1
  slice10/1 -> reinterpret10/1
  reinterpret10/1 -> out10/1
  slice9/1 -> reinterpret9/1
  reinterpret9/1 -> out9/1
  slice8/1 -> reinterpret8/1
  reinterpret8/1 -> out8/1
  slice7/1 -> reinterpret7/1
  reinterpret7/1 -> out7/1
  slice6/1 -> reinterpret6/1
  reinterpret6/1 -> out6/1
  slice5/1 -> reinterpret5/1
  reinterpret5/1 -> out5/1
  slice4/1 -> reinterpret4/1
  reinterpret4/1 -> out4/1
  slice3/1 -> reinterpret3/1
  reinterpret3/1 -> out3/1
  slice2/1 -> reinterpret2/1
  reinterpret2/1 -> out2/1
  slice1/1 -> reinterpret1/1
  reinterpret1/1 -> lsb_out1/1

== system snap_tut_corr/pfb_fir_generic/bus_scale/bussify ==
  in1 : Inport
  in2 : Inport  Port=2
  in3 : Inport  Port=3
  in4 : Inport  Port=4
  in5 : Inport  Port=5
  in6 : Inport  Port=6
  in7 : Inport  Port=7
  in8 : Inport  Port=8
  in9 : Inport  Port=9
  in10 : Inport  Port=10
  in11 : Inport  Port=11
  in12 : Inport  Port=12
  concatenate : xbsIndex_r4/Concat  num_inputs=12  dbl_ovrd=off  block_type=concat
  reinterpret{1..12} (12 alike) : xbsIndex_r4/Reinterpret  force_arith_type=on  arith_type=Unsigned  force_bin_pt=on  bin_pt=0  block_type=reinterpret
  bus_out : Outport
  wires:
  concatenate/1 -> bus_out/1
  in1/1 -> reinterpret1/1
  reinterpret1/1 -> concatenate/1
  in2/1 -> reinterpret2/1
  reinterpret2/1 -> concatenate/2
  in3/1 -> reinterpret3/1
  reinterpret3/1 -> concatenate/3
  in4/1 -> reinterpret4/1
  reinterpret4/1 -> concatenate/4
  in5/1 -> reinterpret5/1
  reinterpret5/1 -> concatenate/5
  in6/1 -> reinterpret6/1
  reinterpret6/1 -> concatenate/6
  in7/1 -> reinterpret7/1
  reinterpret7/1 -> concatenate/7
  in8/1 -> reinterpret8/1
  reinterpret8/1 -> concatenate/8
  in9/1 -> reinterpret9/1
  reinterpret9/1 -> concatenate/9
  in10/1 -> reinterpret10/1
  reinterpret10/1 -> concatenate/10
  in11/1 -> reinterpret11/1
  reinterpret11/1 -> concatenate/11
  in12/1 -> reinterpret12/1
  reinterpret12/1 -> concatenate/12

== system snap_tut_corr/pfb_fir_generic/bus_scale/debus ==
  bus_in : Inport
  reinterpret{1..12} (12 alike) : xbsIndex_r4/Reinterpret  force_arith_type=on  arith_type="Signed  (2's comp)"  force_bin_pt=on  bin_pt=24  block_type=reinterpret
  slice1 : xbsIndex_r4/Slice  nbits=28  boolean_output=off  mode=Upper Bit Location + Width  bit1=-308  base1=MSB of Input  bit0=0  base0=LSB of Input  dbl_ovrd=off  block_type=slice
  slice10 : xbsIndex_r4/Slice  nbits=28  boolean_output=off  mode=Upper Bit Location + Width  bit1=-56  base1=MSB of Input  bit0=0  base0=LSB of Input  dbl_ovrd=off  block_type=slice
  slice11 : xbsIndex_r4/Slice  nbits=28  boolean_output=off  mode=Upper Bit Location + Width  bit1=-28  base1=MSB of Input  bit0=0  base0=LSB of Input  dbl_ovrd=off  block_type=slice
  slice12 : xbsIndex_r4/Slice  nbits=28  boolean_output=off  mode=Upper Bit Location + Width  bit1=0  base1=MSB of Input  bit0=0  base0=LSB of Input  dbl_ovrd=off  block_type=slice
  slice2 : xbsIndex_r4/Slice  nbits=28  boolean_output=off  mode=Upper Bit Location + Width  bit1=-280  base1=MSB of Input  bit0=0  base0=LSB of Input  dbl_ovrd=off  block_type=slice
  slice3 : xbsIndex_r4/Slice  nbits=28  boolean_output=off  mode=Upper Bit Location + Width  bit1=-252  base1=MSB of Input  bit0=0  base0=LSB of Input  dbl_ovrd=off  block_type=slice
  slice4 : xbsIndex_r4/Slice  nbits=28  boolean_output=off  mode=Upper Bit Location + Width  bit1=-224  base1=MSB of Input  bit0=0  base0=LSB of Input  dbl_ovrd=off  block_type=slice
  slice5 : xbsIndex_r4/Slice  nbits=28  boolean_output=off  mode=Upper Bit Location + Width  bit1=-196  base1=MSB of Input  bit0=0  base0=LSB of Input  dbl_ovrd=off  block_type=slice
  slice6 : xbsIndex_r4/Slice  nbits=28  boolean_output=off  mode=Upper Bit Location + Width  bit1=-168  base1=MSB of Input  bit0=0  base0=LSB of Input  dbl_ovrd=off  block_type=slice
  slice7 : xbsIndex_r4/Slice  nbits=28  boolean_output=off  mode=Upper Bit Location + Width  bit1=-140  base1=MSB of Input  bit0=0  base0=LSB of Input  dbl_ovrd=off  block_type=slice
  slice8 : xbsIndex_r4/Slice  nbits=28  boolean_output=off  mode=Upper Bit Location + Width  bit1=-112  base1=MSB of Input  bit0=0  base0=LSB of Input  dbl_ovrd=off  block_type=slice
  slice9 : xbsIndex_r4/Slice  nbits=28  boolean_output=off  mode=Upper Bit Location + Width  bit1=-84  base1=MSB of Input  bit0=0  base0=LSB of Input  dbl_ovrd=off  block_type=slice
  msb_out12 : Outport
  out11 : Outport  Port=2
  out10 : Outport  Port=3
  out9 : Outport  Port=4
  out8 : Outport  Port=5
  out7 : Outport  Port=6
  out6 : Outport  Port=7
  out5 : Outport  Port=8
  out4 : Outport  Port=9
  out3 : Outport  Port=10
  out2 : Outport  Port=11
  lsb_out1 : Outport  Port=12
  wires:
  bus_in/1 -> slice12/1, slice11/1, slice10/1, slice9/1, slice8/1, slice7/1, slice6/1, slice5/1, slice4/1, slice3/1, slice2/1, slice1/1
  slice12/1 -> reinterpret12/1
  reinterpret12/1 -> msb_out12/1
  slice11/1 -> reinterpret11/1
  reinterpret11/1 -> out11/1
  slice10/1 -> reinterpret10/1
  reinterpret10/1 -> out10/1
  slice9/1 -> reinterpret9/1
  reinterpret9/1 -> out9/1
  slice8/1 -> reinterpret8/1
  reinterpret8/1 -> out8/1
  slice7/1 -> reinterpret7/1
  reinterpret7/1 -> out7/1
  slice6/1 -> reinterpret6/1
  reinterpret6/1 -> out6/1
  slice5/1 -> reinterpret5/1
  reinterpret5/1 -> out5/1
  slice4/1 -> reinterpret4/1
  reinterpret4/1 -> out4/1
  slice3/1 -> reinterpret3/1
  reinterpret3/1 -> out3/1
  slice2/1 -> reinterpret2/1
  reinterpret2/1 -> out2/1
  slice1/1 -> reinterpret1/1
  reinterpret1/1 -> lsb_out1/1

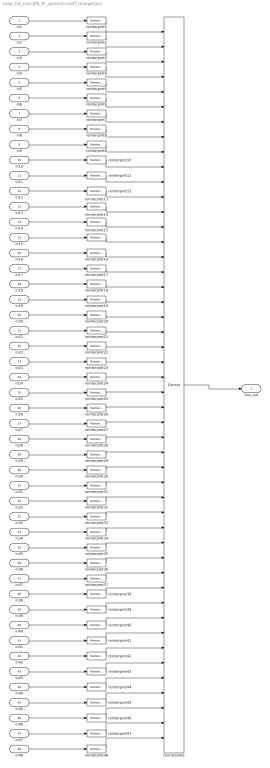
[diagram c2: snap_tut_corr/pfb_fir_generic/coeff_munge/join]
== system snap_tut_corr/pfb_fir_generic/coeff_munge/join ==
  in1 : Inport
  in2 : Inport  Port=2
  in3 : Inport  Port=3
  in4 : Inport  Port=4
  in5 : Inport  Port=5
  in6 : Inport  Port=6
  in7 : Inport  Port=7
  in8 : Inport  Port=8
  in9 : Inport  Port=9
  in10 : Inport  Port=10
  in11 : Inport  Port=11
  in12 : Inport  Port=12
  in13 : Inport  Port=13
  in14 : Inport  Port=14
  in15 : Inport  Port=15
  in16 : Inport  Port=16
  in17 : Inport  Port=17
  in18 : Inport  Port=18
  in19 : Inport  Port=19
  in20 : Inport  Port=20
  in21 : Inport  Port=21
  in22 : Inport  Port=22
  in23 : Inport  Port=23
  in24 : Inport  Port=24
  in25 : Inport  Port=25
  in26 : Inport  Port=26
  in27 : Inport  Port=27
  in28 : Inport  Port=28
  in29 : Inport  Port=29
  in30 : Inport  Port=30
  in31 : Inport  Port=31
  in32 : Inport  Port=32
  in33 : Inport  Port=33
  in34 : Inport  Port=34
  in35 : Inport  Port=35
  in36 : Inport  Port=36
  in37 : Inport  Port=37
  in38 : Inport  Port=38
  in39 : Inport  Port=39
  in40 : Inport  Port=40
  in41 : Inport  Port=41
  in42 : Inport  Port=42
  in43 : Inport  Port=43
  in44 : Inport  Port=44
  in45 : Inport  Port=45
  in46 : Inport  Port=46
  in47 : Inport  Port=47
  in48 : Inport  Port=48
  concatenate : xbsIndex_r4/Concat  num_inputs=48  dbl_ovrd=off  block_type=concat
  reinterpret{1..48} (48 alike) : xbsIndex_r4/Reinterpret  force_arith_type=on  arith_type=Unsigned  force_bin_pt=on  bin_pt=0  block_type=reinterpret
  bus_out : Outport
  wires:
  concatenate/1 -> bus_out/1
  in1/1 -> reinterpret1/1
  reinterpret1/1 -> concatenate/1
  in2/1 -> reinterpret2/1
  reinterpret2/1 -> concatenate/2
  in3/1 -> reinterpret3/1
  reinterpret3/1 -> concatenate/3
  in4/1 -> reinterpret4/1
  reinterpret4/1 -> concatenate/4
  in5/1 -> reinterpret5/1
  reinterpret5/1 -> concatenate/5
  in6/1 -> reinterpret6/1
  reinterpret6/1 -> concatenate/6
  in7/1 -> reinterpret7/1
  reinterpret7/1 -> concatenate/7
  in8/1 -> reinterpret8/1
  reinterpret8/1 -> concatenate/8
  in9/1 -> reinterpret9/1
  reinterpret9/1 -> concatenate/9
  in10/1 -> reinterpret10/1
  reinterpret10/1 -> concatenate/10
  in11/1 -> reinterpret11/1
  reinterpret11/1 -> concatenate/11
  in12/1 -> reinterpret12/1
  reinterpret12/1 -> concatenate/12
  in13/1 -> reinterpret13/1
  reinterpret13/1 -> concatenate/13
  in14/1 -> reinterpret14/1
  reinterpret14/1 -> concatenate/14
  in15/1 -> reinterpret15/1
  reinterpret15/1 -> concatenate/15
  in16/1 -> reinterpret16/1
  reinterpret16/1 -> concatenate/16
  in17/1 -> reinterpret17/1
  reinterpret17/1 -> concatenate/17
  in18/1 -> reinterpret18/1
  reinterpret18/1 -> concatenate/18
  in19/1 -> reinterpret19/1
  reinterpret19/1 -> concatenate/19
  in20/1 -> reinterpret20/1
  reinterpret20/1 -> concatenate/20
  in21/1 -> reinterpret21/1
  reinterpret21/1 -> concatenate/21
  in22/1 -> reinterpret22/1
  reinterpret22/1 -> concatenate/22
  in23/1 -> reinterpret23/1
  reinterpret23/1 -> concatenate/23
  in24/1 -> reinterpret24/1
  reinterpret24/1 -> concatenate/24
  in25/1 -> reinterpret25/1
  reinterpret25/1 -> concatenate/25
  in26/1 -> reinterpret26/1
  reinterpret26/1 -> concatenate/26
  in27/1 -> reinterpret27/1
  reinterpret27/1 -> concatenate/27
  in28/1 -> reinterpret28/1
  reinterpret28/1 -> concatenate/28
  in29/1 -> reinterpret29/1
  reinterpret29/1 -> concatenate/29
  in30/1 -> reinterpret30/1
  reinterpret30/1 -> concatenate/30
  in31/1 -> reinterpret31/1
  reinterpret31/1 -> concatenate/31
  in32/1 -> reinterpret32/1
  reinterpret32/1 -> concatenate/32
  in33/1 -> reinterpret33/1
  reinterpret33/1 -> concatenate/33
  in34/1 -> reinterpret34/1
  reinterpret34/1 -> concatenate/34
  in35/1 -> reinterpret35/1
  reinterpret35/1 -> concatenate/35
  in36/1 -> reinterpret36/1
  reinterpret36/1 -> concatenate/36
  in37/1 -> reinterpret37/1
  reinterpret37/1 -> concatenate/37
  in38/1 -> reinterpret38/1
  reinterpret38/1 -> concatenate/38
  in39/1 -> reinterpret39/1
  reinterpret39/1 -> concatenate/39
  in40/1 -> reinterpret40/1
  reinterpret40/1 -> concatenate/40
  in41/1 -> reinterpret41/1
  reinterpret41/1 -> concatenate/41
  in42/1 -> reinterpret42/1
  reinterpret42/1 -> concatenate/42
  in43/1 -> reinterpret43/1
  reinterpret43/1 -> concatenate/43
  in44/1 -> reinterpret44/1
  reinterpret44/1 -> concatenate/44
  in45/1 -> reinterpret45/1
  reinterpret45/1 -> concatenate/45
  in46/1 -> reinterpret46/1
  reinterpret46/1 -> concatenate/46
  in47/1 -> reinterpret47/1
  reinterpret47/1 -> concatenate/47
  in48/1 -> reinterpret48/1
  reinterpret48/1 -> concatenate/48

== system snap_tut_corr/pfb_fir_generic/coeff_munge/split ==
  bus_in : Inport
  reinterpret{1..16} (16 alike) : xbsIndex_r4/Reinterpret  force_arith_type=on  arith_type=Unsigned  force_bin_pt=on  bin_pt=0  block_type=reinterpret
  slice1 : xbsIndex_r4/Slice  nbits=18  boolean_output=off  mode=Upper Bit Location + Width  bit1=-270  base1=MSB of Input  bit0=0  base0=LSB of Input  dbl_ovrd=off  block_type=slice
  slice10 : xbsIndex_r4/Slice  nbits=18  boolean_output=off  mode=Upper Bit Location + Width  bit1=-108  base1=MSB of Input  bit0=0  base0=LSB of Input  dbl_ovrd=off  block_type=slice
  slice11 : xbsIndex_r4/Slice  nbits=18  boolean_output=off  mode=Upper Bit Location + Width  bit1=-90  base1=MSB of Input  bit0=0  base0=LSB of Input  dbl_ovrd=off  block_type=slice
  slice12 : xbsIndex_r4/Slice  nbits=18  boolean_output=off  mode=Upper Bit Location + Width  bit1=-72  base1=MSB of Input  bit0=0  base0=LSB of Input  dbl_ovrd=off  block_type=slice
  slice13 : xbsIndex_r4/Slice  nbits=18  boolean_output=off  mode=Upper Bit Location + Width  bit1=-54  base1=MSB of Input  bit0=0  base0=LSB of Input  dbl_ovrd=off  block_type=slice
  slice14 : xbsIndex_r4/Slice  nbits=18  boolean_output=off  mode=Upper Bit Location + Width  bit1=-36  base1=MSB of Input  bit0=0  base0=LSB of Input  dbl_ovrd=off  block_type=slice
  slice15 : xbsIndex_r4/Slice  nbits=18  boolean_output=off  mode=Upper Bit Location + Width  bit1=-18  base1=MSB of Input  bit0=0  base0=LSB of Input  dbl_ovrd=off  block_type=slice
  slice16 : xbsIndex_r4/Slice  nbits=18  boolean_output=off  mode=Upper Bit Location + Width  bit1=0  base1=MSB of Input  bit0=0  base0=LSB of Input  dbl_ovrd=off  block_type=slice
  slice2 : xbsIndex_r4/Slice  nbits=18  boolean_output=off  mode=Upper Bit Location + Width  bit1=-252  base1=MSB of Input  bit0=0  base0=LSB of Input  dbl_ovrd=off  block_type=slice
  slice3 : xbsIndex_r4/Slice  nbits=18  boolean_output=off  mode=Upper Bit Location + Width  bit1=-234  base1=MSB of Input  bit0=0  base0=LSB of Input  dbl_ovrd=off  block_type=slice
  slice4 : xbsIndex_r4/Slice  nbits=18  boolean_output=off  mode=Upper Bit Location + Width  bit1=-216  base1=MSB of Input  bit0=0  base0=LSB of Input  dbl_ovrd=off  block_type=slice
  slice5 : xbsIndex_r4/Slice  nbits=18  boolean_output=off  mode=Upper Bit Location + Width  bit1=-198  base1=MSB of Input  bit0=0  base0=LSB of Input  dbl_ovrd=off  block_type=slice
  slice6 : xbsIndex_r4/Slice  nbits=18  boolean_output=off  mode=Upper Bit Location + Width  bit1=-180  base1=MSB of Input  bit0=0  base0=LSB of Input  dbl_ovrd=off  block_type=slice
  slice7 : xbsIndex_r4/Slice  nbits=18  boolean_output=off  mode=Upper Bit Location + Width  bit1=-162  base1=MSB of Input  bit0=0  base0=LSB of Input  dbl_ovrd=off  block_type=slice
  slice8 : xbsIndex_r4/Slice  nbits=18  boolean_output=off  mode=Upper Bit Location + Width  bit1=-144  base1=MSB of Input  bit0=0  base0=LSB of Input  dbl_ovrd=off  block_type=slice
  slice9 : xbsIndex_r4/Slice  nbits=18  boolean_output=off  mode=Upper Bit Location + Width  bit1=-126  base1=MSB of Input  bit0=0  base0=LSB of Input  dbl_ovrd=off  block_type=slice
  msb_out16 : Outport
  out15 : Outport  Port=2
  out14 : Outport  Port=3
  out13 : Outport  Port=4
  out12 : Outport  Port=5
  out11 : Outport  Port=6
  out10 : Outport  Port=7
  out9 : Outport  Port=8
  out8 : Outport  Port=9
  out7 : Outport  Port=10
  out6 : Outport  Port=11
  out5 : Outport  Port=12
  out4 : Outport  Port=13
  out3 : Outport  Port=14
  out2 : Outport  Port=15
  lsb_out1 : Outport  Port=16
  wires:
  bus_in/1 -> slice16/1, slice15/1, slice14/1, slice13/1, slice12/1, slice11/1, slice10/1, slice9/1, slice8/1, slice7/1, slice6/1, slice5/1, slice4/1, slice3/1, slice2/1, slice1/1
  slice16/1 -> reinterpret16/1
  reinterpret16/1 -> msb_out16/1
  slice15/1 -> reinterpret15/1
  reinterpret15/1 -> out15/1
  slice14/1 -> reinterpret14/1
  reinterpret14/1 -> out14/1
  slice13/1 -> reinterpret13/1
  reinterpret13/1 -> out13/1
  slice12/1 -> reinterpret12/1
  reinterpret12/1 -> out12/1
  slice11/1 -> reinterpret11/1
  reinterpret11/1 -> out11/1
  slice10/1 -> reinterpret10/1
  reinterpret10/1 -> out10/1
  slice9/1 -> reinterpret9/1
  reinterpret9/1 -> out9/1
  slice8/1 -> reinterpret8/1
  reinterpret8/1 -> out8/1
  slice7/1 -> reinterpret7/1
  reinterpret7/1 -> out7/1
  slice6/1 -> reinterpret6/1
  reinterpret6/1 -> out6/1
  slice5/1 -> reinterpret5/1
  reinterpret5/1 -> out5/1
  slice4/1 -> reinterpret4/1
  reinterpret4/1 -> out4/1
  slice3/1 -> reinterpret3/1
  reinterpret3/1 -> out3/1
  slice2/1 -> reinterpret2/1
  reinterpret2/1 -> out2/1
  slice1/1 -> reinterpret1/1
  reinterpret1/1 -> lsb_out1/1

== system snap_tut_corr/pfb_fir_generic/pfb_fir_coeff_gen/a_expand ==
  bus_in : Inport
  reinterpret{1..8} (8 alike) : xbsIndex_r4/Reinterpret  force_arith_type=on  arith_type=Unsigned  force_bin_pt=on  bin_pt=0  block_type=reinterpret
  slice1 : xbsIndex_r4/Slice  nbits=18  boolean_output=off  mode=Upper Bit Location + Width  bit1=-126  base1=MSB of Input  bit0=0  base0=LSB of Input  dbl_ovrd=off  block_type=slice
  slice2 : xbsIndex_r4/Slice  nbits=18  boolean_output=off  mode=Upper Bit Location + Width  bit1=-108  base1=MSB of Input  bit0=0  base0=LSB of Input  dbl_ovrd=off  block_type=slice
  slice3 : xbsIndex_r4/Slice  nbits=18  boolean_output=off  mode=Upper Bit Location + Width  bit1=-90  base1=MSB of Input  bit0=0  base0=LSB of Input  dbl_ovrd=off  block_type=slice
  slice4 : xbsIndex_r4/Slice  nbits=18  boolean_output=off  mode=Upper Bit Location + Width  bit1=-72  base1=MSB of Input  bit0=0  base0=LSB of Input  dbl_ovrd=off  block_type=slice
  slice5 : xbsIndex_r4/Slice  nbits=18  boolean_output=off  mode=Upper Bit Location + Width  bit1=-54  base1=MSB of Input  bit0=0  base0=LSB of Input  dbl_ovrd=off  block_type=slice
  slice6 : xbsIndex_r4/Slice  nbits=18  boolean_output=off  mode=Upper Bit Location + Width  bit1=-36  base1=MSB of Input  bit0=0  base0=LSB of Input  dbl_ovrd=off  block_type=slice
  slice7 : xbsIndex_r4/Slice  nbits=18  boolean_output=off  mode=Upper Bit Location + Width  bit1=-18  base1=MSB of Input  bit0=0  base0=LSB of Input  dbl_ovrd=off  block_type=slice
  slice8 : xbsIndex_r4/Slice  nbits=18  boolean_output=off  mode=Upper Bit Location + Width  bit1=0  base1=MSB of Input  bit0=0  base0=LSB of Input  dbl_ovrd=off  block_type=slice
  msb_out8 : Outport
  out7 : Outport  Port=2
  out6 : Outport  Port=3
  out5 : Outport  Port=4
  out4 : Outport  Port=5
  out3 : Outport  Port=6
  out2 : Outport  Port=7
  lsb_out1 : Outport  Port=8
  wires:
  bus_in/1 -> slice8/1, slice7/1, slice6/1, slice5/1, slice4/1, slice3/1, slice2/1, slice1/1
  slice8/1 -> reinterpret8/1
  reinterpret8/1 -> msb_out8/1
  slice7/1 -> reinterpret7/1
  reinterpret7/1 -> out7/1
  slice6/1 -> reinterpret6/1
  reinterpret6/1 -> out6/1
  slice5/1 -> reinterpret5/1
  reinterpret5/1 -> out5/1
  slice4/1 -> reinterpret4/1
  reinterpret4/1 -> out4/1
  slice3/1 -> reinterpret3/1
  reinterpret3/1 -> out3/1
  slice2/1 -> reinterpret2/1
  reinterpret2/1 -> out2/1
  slice1/1 -> reinterpret1/1
  reinterpret1/1 -> lsb_out1/1

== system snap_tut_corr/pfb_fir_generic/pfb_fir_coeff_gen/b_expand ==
  bus_in : Inport
  reinterpret{1..8} (8 alike) : xbsIndex_r4/Reinterpret  force_arith_type=on  arith_type=Unsigned  force_bin_pt=on  bin_pt=0  block_type=reinterpret
  slice1 : xbsIndex_r4/Slice  nbits=18  boolean_output=off  mode=Upper Bit Location + Width  bit1=-126  base1=MSB of Input  bit0=0  base0=LSB of Input  dbl_ovrd=off  block_type=slice
  slice2 : xbsIndex_r4/Slice  nbits=18  boolean_output=off  mode=Upper Bit Location + Width  bit1=-108  base1=MSB of Input  bit0=0  base0=LSB of Input  dbl_ovrd=off  block_type=slice
  slice3 : xbsIndex_r4/Slice  nbits=18  boolean_output=off  mode=Upper Bit Location + Width  bit1=-90  base1=MSB of Input  bit0=0  base0=LSB of Input  dbl_ovrd=off  block_type=slice
  slice4 : xbsIndex_r4/Slice  nbits=18  boolean_output=off  mode=Upper Bit Location + Width  bit1=-72  base1=MSB of Input  bit0=0  base0=LSB of Input  dbl_ovrd=off  block_type=slice
  slice5 : xbsIndex_r4/Slice  nbits=18  boolean_output=off  mode=Upper Bit Location + Width  bit1=-54  base1=MSB of Input  bit0=0  base0=LSB of Input  dbl_ovrd=off  block_type=slice
  slice6 : xbsIndex_r4/Slice  nbits=18  boolean_output=off  mode=Upper Bit Location + Width  bit1=-36  base1=MSB of Input  bit0=0  base0=LSB of Input  dbl_ovrd=off  block_type=slice
  slice7 : xbsIndex_r4/Slice  nbits=18  boolean_output=off  mode=Upper Bit Location + Width  bit1=-18  base1=MSB of Input  bit0=0  base0=LSB of Input  dbl_ovrd=off  block_type=slice
  slice8 : xbsIndex_r4/Slice  nbits=18  boolean_output=off  mode=Upper Bit Location + Width  bit1=0  base1=MSB of Input  bit0=0  base0=LSB of Input  dbl_ovrd=off  block_type=slice
  msb_out8 : Outport
  out7 : Outport  Port=2
  out6 : Outport  Port=3
  out5 : Outport  Port=4
  out4 : Outport  Port=5
  out3 : Outport  Port=6
  out2 : Outport  Port=7
  lsb_out1 : Outport  Port=8
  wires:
  bus_in/1 -> slice8/1, slice7/1, slice6/1, slice5/1, slice4/1, slice3/1, slice2/1, slice1/1
  slice8/1 -> reinterpret8/1
  reinterpret8/1 -> msb_out8/1
  slice7/1 -> reinterpret7/1
  reinterpret7/1 -> out7/1
  slice6/1 -> reinterpret6/1
  reinterpret6/1 -> out6/1
  slice5/1 -> reinterpret5/1
  reinterpret5/1 -> out5/1
  slice4/1 -> reinterpret4/1
  reinterpret4/1 -> out4/1
  slice3/1 -> reinterpret3/1
  reinterpret3/1 -> out3/1
  slice2/1 -> reinterpret2/1
  reinterpret2/1 -> out2/1
  slice1/1 -> reinterpret1/1
  reinterpret1/1 -> lsb_out1/1

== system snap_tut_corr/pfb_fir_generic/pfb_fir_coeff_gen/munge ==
  din : Inport
  join : Subsystem  AncestorBlock=casper_library_flow_control/bus_create  mask(bus_create){inputNum=8}
      mask prompts: inputNum "Number of inputs:"
      mask init:
      | bus_create_init(gcb,...
      |     'inputNum', inputNum);
  reinterpret : xbsIndex_r4/Reinterpret  force_arith_type=on  arith_type=Unsigned  force_bin_pt=on  bin_pt=0  block_type=reinterpret
  reinterpret_out : xbsIndex_r4/Reinterpret  force_arith_type=on  arith_type=Unsigned  force_bin_pt=on  bin_pt=0  block_type=reinterpret
  split : Subsystem  AncestorBlock=casper_library_flow_control/bus_expand  mask(bus_expand){mode=divisions of arbitrary size, outputNum=1, outputWidth=[18 18 18 18 18 18 18 18], outputBinaryPt=[0 0 0 0 0 0 0 0], outputArithmeticType=[0 0 0 0 0 0 0 0], show_format=off, outputToWorkspace=off, variablePrefix=out, outputToModelAsWell=on}
      mask prompts: outputNum "Number of outputs:"; outputWidth "Output width [msb ... lsb]:"; outputBinaryPt "Output binary point position [msb ... lsb]:"; outputArithmeticType "Output arithmetic type (ufix=0, fix=1, bool=2) [msb ... lsb]:"; show_format "Print format string?"; outputToWorkspace "Output to workspace?"; variablePrefix "Variable name prefix:"; outputToModelAsWell "Output to model as well?"
      mask help: Expands a 'bus' made using a bus_create or Xilinx concat block. The input will be divided into the specified number of outputs with the specified arithmetic types. Divisions are made from most significant bit.
      mask init:
      | bus_expand_init(gcb,...
      |     'mode', mode, ...
      |     'outputNum', outputNum, ...
      |     'outputWidth', outputWidth, ...
      |     'outputBinaryPt', outputBinaryPt, ...
      |     'outputArithmeticType', outputArithmeticType, ...
      |     'show_format', show_format, ...
      |     'outputToWorkspace', outputToWorkspace, ...
      |     'variablePrefix', variablePrefix, ...
      |     'outputToModelAsWell', outputToModelAsWell);
  dout : Outport
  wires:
  reinterpret_out/1 -> dout/1
  din/1 -> reinterpret/1
  reinterpret/1 -> split/1(bus_in)
  join/1(bus_out) -> reinterpret_out/1
  split/5(out4) -> join/1(in1)
  split/8(lsb_out1) -> join/2(in2)
  split/7(out2) -> join/3(in3)
  split/6(out3) -> join/4(in4)
  split/1(msb_out8) -> join/5(in5)
  split/4(out5) -> join/6(in6)
  split/3(out6) -> join/7(in7)
  split/2(out7) -> join/8(in8)

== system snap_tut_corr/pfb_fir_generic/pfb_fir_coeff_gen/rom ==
  addra : Inport
  dina : Inport  Port=2
  wea : Inport  Port=3
  addrb : Inport  Port=4
  dinb : Inport  Port=5
  web : Inport  Port=6
  A_bussify0 : Subsystem  AncestorBlock=casper_library_flow_control/bus_create  mask(bus_create){inputNum=4}
      mask prompts: inputNum "Number of inputs:"
      mask init:
      | bus_create_init(gcb,...
      |     'inputNum', inputNum);
  B_bussify0 : Subsystem  AncestorBlock=casper_library_flow_control/bus_create  mask(bus_create){inputNum=4}
      mask prompts: inputNum "Number of inputs:"
      mask init:
      | bus_create_init(gcb,...
      |     'inputNum', inputNum);
  alsbs_slice : xbsIndex_r4/Slice  nbits=9  boolean_output=off  mode=Lower Bit Location + Width  bit1=0  base1=LSB of Input  bit0=0  base0=LSB of Input  dbl_ovrd=off  block_type=slice
  blsbs_slice : xbsIndex_r4/Slice  nbits=9  boolean_output=off  mode=Lower Bit Location + Width  bit1=0  base1=LSB of Input  bit0=0  base0=LSB of Input  dbl_ovrd=off  block_type=slice
  bram0_{0..3} (4 alike) : xbsIndex_r4/Dual Port RAM  depth=512  initVector=getfield(get_param(gcb, 'UserData'), 'initVector')  distributed_mem=Block RAM  init_a=0  init_b=0  rst_a=off  rst_b=off  en_a=off  en_b=off  latency=1  write_mode_A=Read Before Write  write_mode_B=Read Before Write  optimize=Area  dbl_ovrd=off  block_type=dpram
  ddina0 : xbsIndex_r4/Delay  rst=off  infoeditControl=Selection of Reset will increase slice count due to use of real FFs and instead of SRLs  en=off  latency=0  reg_retiming=on  dbl_ovrd=off  block_type=delay
  ddinb0 : xbsIndex_r4/Delay  rst=off  infoeditControl=Selection of Reset will increase slice count due to use of real FFs and instead of SRLs  en=off  latency=0  reg_retiming=on  dbl_ovrd=off  block_type=delay
  debus_addra0 : Subsystem  AncestorBlock=casper_library_flow_control/bus_expand  mask(bus_expand){mode=divisions of equal size, outputNum=4, outputWidth=[9 9 9 9], outputBinaryPt=[0 0 0 0], outputArithmeticType=[0 0 0 0], show_format=on, outputToWorkspace=off, variablePrefix=, outputToModelAsWell=on}
      mask prompts: outputNum "Number of outputs:"; outputWidth "Output width:"; outputBinaryPt "Output binary point position:"; outputArithmeticType "Output arithmetic type (ufix=0, fix=1, bool=2):"; show_format "Print format string?"; outputToWorkspace "Output to workspace?"; variablePrefix "Variable name prefix:"; outputToModelAsWell "Output to model as well?"
      mask help: Expands a 'bus' made using a bus_create or Xilinx concat block. The input will be divided into the specified number of outputs with the specified arithmetic types. Divisions are made from most significant bit.
      mask init:
      | bus_expand_init(gcb,...
      |     'mode', mode, ...
      |     'outputNum', outputNum, ...
      |     'outputWidth', outputWidth, ...
      |     'outputBinaryPt', outputBinaryPt, ...
      |     'outputArithmeticType', outputArithmeticType, ...
      |     'show_format', show_format, ...
      |     'outputToWorkspace', outputToWorkspace, ...
      |     'variablePrefix', variablePrefix, ...
      |     'outputToModelAsWell', outputToModelAsWell);
  debus_addrb0 : Subsystem  AncestorBlock=casper_library_flow_control/bus_expand  mask(bus_expand){mode=divisions of equal size, outputNum=4, outputWidth=[9 9 9 9], outputBinaryPt=[0 0 0 0], outputArithmeticType=[0 0 0 0], show_format=on, outputToWorkspace=off, variablePrefix=, outputToModelAsWell=on}
      mask prompts: outputNum "Number of outputs:"; outputWidth "Output width:"; outputBinaryPt "Output binary point position:"; outputArithmeticType "Output arithmetic type (ufix=0, fix=1, bool=2):"; show_format "Print format string?"; outputToWorkspace "Output to workspace?"; variablePrefix "Variable name prefix:"; outputToModelAsWell "Output to model as well?"
      mask help: Expands a 'bus' made using a bus_create or Xilinx concat block. The input will be divided into the specified number of outputs with the specified arithmetic types. Divisions are made from most significant bit.
      mask init:
      | bus_expand_init(gcb,...
      |     'mode', mode, ...
      |     'outputNum', outputNum, ...
      |     'outputWidth', outputWidth, ...
      |     'outputBinaryPt', outputBinaryPt, ...
      |     'outputArithmeticType', outputArithmeticType, ...
      |     'show_format', show_format, ...
      |     'outputToWorkspace', outputToWorkspace, ...
      |     'variablePrefix', variablePrefix, ...
      |     'outputToModelAsWell', outputToModelAsWell);
  debus_dina0 : Subsystem  AncestorBlock=casper_library_flow_control/bus_expand  mask(bus_expand){mode=divisions of arbitrary size, outputNum=1, outputWidth=[36 36 36 36], outputBinaryPt=[0 0 0 0], outputArithmeticType=[0 0 0 0], show_format=on, outputToWorkspace=off, variablePrefix=, outputToModelAsWell=on}
      mask prompts: outputNum "Number of outputs:"; outputWidth "Output width [msb ... lsb]:"; outputBinaryPt "Output binary point position [msb ... lsb]:"; outputArithmeticType "Output arithmetic type (ufix=0, fix=1, bool=2) [msb ... lsb]:"; show_format "Print format string?"; outputToWorkspace "Output to workspace?"; variablePrefix "Variable name prefix:"; outputToModelAsWell "Output to model as well?"
      mask help: Expands a 'bus' made using a bus_create or Xilinx concat block. The input will be divided into the specified number of outputs with the specified arithmetic types. Divisions are made from most significant bit.
      mask init:
      | bus_expand_init(gcb,...
      |     'mode', mode, ...
      |     'outputNum', outputNum, ...
      |     'outputWidth', outputWidth, ...
      |     'outputBinaryPt', outputBinaryPt, ...
      |     'outputArithmeticType', outputArithmeticType, ...
      |     'show_format', show_format, ...
      |     'outputToWorkspace', outputToWorkspace, ...
      |     'variablePrefix', variablePrefix, ...
      |     'outputToModelAsWell', outputToModelAsWell);
  debus_dinb0 : Subsystem  AncestorBlock=casper_library_flow_control/bus_expand  mask(bus_expand){mode=divisions of arbitrary size, outputNum=1, outputWidth=[36 36 36 36], outputBinaryPt=[0 0 0 0], outputArithmeticType=[0 0 0 0], show_format=on, outputToWorkspace=off, variablePrefix=, outputToModelAsWell=on}
      mask prompts: outputNum "Number of outputs:"; outputWidth "Output width [msb ... lsb]:"; outputBinaryPt "Output binary point position [msb ... lsb]:"; outputArithmeticType "Output arithmetic type (ufix=0, fix=1, bool=2) [msb ... lsb]:"; show_format "Print format string?"; outputToWorkspace "Output to workspace?"; variablePrefix "Variable name prefix:"; outputToModelAsWell "Output to model as well?"
      mask help: Expands a 'bus' made using a bus_create or Xilinx concat block. The input will be divided into the specified number of outputs with the specified arithmetic types. Divisions are made from most significant bit.
      mask init:
      | bus_expand_init(gcb,...
      |     'mode', mode, ...
      |     'outputNum', outputNum, ...
      |     'outputWidth', outputWidth, ...
      |     'outputBinaryPt', outputBinaryPt, ...
      |     'outputArithmeticType', outputArithmeticType, ...
      |     'show_format', show_format, ...
      |     'outputToWorkspace', outputToWorkspace, ...
      |     'variablePrefix', variablePrefix, ...
      |     'outputToModelAsWell', outputToModelAsWell);
  debus_wea0 : Subsystem  AncestorBlock=casper_library_flow_control/bus_expand  mask(bus_expand){mode=divisions of equal size, outputNum=4, outputWidth=[1 1 1 1], outputBinaryPt=[0 0 0 0], outputArithmeticType=[2 2 2 2], show_format=on, outputToWorkspace=off, variablePrefix=, outputToModelAsWell=on}
      mask prompts: outputNum "Number of outputs:"; outputWidth "Output width:"; outputBinaryPt "Output binary point position:"; outputArithmeticType "Output arithmetic type (ufix=0, fix=1, bool=2):"; show_format "Print format string?"; outputToWorkspace "Output to workspace?"; variablePrefix "Variable name prefix:"; outputToModelAsWell "Output to model as well?"
      mask help: Expands a 'bus' made using a bus_create or Xilinx concat block. The input will be divided into the specified number of outputs with the specified arithmetic types. Divisions are made from most significant bit.
      mask init:
      | bus_expand_init(gcb,...
      |     'mode', mode, ...
      |     'outputNum', outputNum, ...
      |     'outputWidth', outputWidth, ...
      |     'outputBinaryPt', outputBinaryPt, ...
      |     'outputArithmeticType', outputArithmeticType, ...
      |     'show_format', show_format, ...
      |     'outputToWorkspace', outputToWorkspace, ...
      |     'variablePrefix', variablePrefix, ...
      |     'outputToModelAsWell', outputToModelAsWell);
  debus_web0 : Subsystem  AncestorBlock=casper_library_flow_control/bus_expand  mask(bus_expand){mode=divisions of equal size, outputNum=4, outputWidth=[1 1 1 1], outputBinaryPt=[0 0 0 0], outputArithmeticType=[2 2 2 2], show_format=on, outputToWorkspace=off, variablePrefix=, outputToModelAsWell=on}
      mask prompts: outputNum "Number of outputs:"; outputWidth "Output width:"; outputBinaryPt "Output binary point position:"; outputArithmeticType "Output arithmetic type (ufix=0, fix=1, bool=2):"; show_format "Print format string?"; outputToWorkspace "Output to workspace?"; variablePrefix "Variable name prefix:"; outputToModelAsWell "Output to model as well?"
      mask help: Expands a 'bus' made using a bus_create or Xilinx concat block. The input will be divided into the specified number of outputs with the specified arithmetic types. Divisions are made from most significant bit.
      mask init:
      | bus_expand_init(gcb,...
      |     'mode', mode, ...
      |     'outputNum', outputNum, ...
      |     'outputWidth', outputWidth, ...
      |     'outputBinaryPt', outputBinaryPt, ...
      |     'outputArithmeticType', outputArithmeticType, ...
      |     'show_format', show_format, ...
      |     'outputToWorkspace', outputToWorkspace, ...
      |     'variablePrefix', variablePrefix, ...
      |     'outputToModelAsWell', outputToModelAsWell);
  rep_addra0 : Subsystem  AncestorBlock=casper_library_bus/bus_replicate  mask(bus_replicate){replication=4, csp_latency=1, misc=off, implementation=core}
      mask prompts: replication "replication factor"; csp_latency "latency"; misc "misc support"; implementation "delay implementation"
      mask help: Output bus formed by replicating input bus a number of times
      mask init:
      | bus_replicate_init(gcb, ...
      |     'replication', replication, ...
      |     'csp_latency', csp_latency, ...
      |     'implementation', implementation, ...
      |     'misc', misc);
  rep_addrb0 : Subsystem  AncestorBlock=casper_library_bus/bus_replicate  mask(bus_replicate){replication=4, csp_latency=1, misc=off, implementation=core}
      mask prompts: replication "replication factor"; csp_latency "latency"; misc "misc support"; implementation "delay implementation"
      mask help: Output bus formed by replicating input bus a number of times
      mask init:
      | bus_replicate_init(gcb, ...
      |     'replication', replication, ...
      |     'csp_latency', csp_latency, ...
      |     'implementation', implementation, ...
      |     'misc', misc);
  rep_wea0 : Subsystem  AncestorBlock=casper_library_bus/bus_replicate  mask(bus_replicate){replication=4, csp_latency=0, misc=off, implementation=behavioral}
      mask prompts: replication "replication factor"; csp_latency "latency"; misc "misc support"; implementation "delay implementation"
      mask help: Output bus formed by replicating input bus a number of times
      mask init:
      | bus_replicate_init(gcb, ...
      |     'replication', replication, ...
      |     'csp_latency', csp_latency, ...
      |     'implementation', implementation, ...
      |     'misc', misc);
  rep_web0 : Subsystem  AncestorBlock=casper_library_bus/bus_replicate  mask(bus_replicate){replication=4, csp_latency=0, misc=off, implementation=behavioral}
      mask prompts: replication "replication factor"; csp_latency "latency"; misc "misc support"; implementation "delay implementation"
      mask help: Output bus formed by replicating input bus a number of times
      mask init:
      | bus_replicate_init(gcb, ...
      |     'replication', replication, ...
      |     'csp_latency', csp_latency, ...
      |     'implementation', implementation, ...
      |     'misc', misc);
  A : Outport
  B : Outport  Port=2
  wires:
  addrb/1 -> blsbs_slice/1
  addra/1 -> alsbs_slice/1
  blsbs_slice/1 -> rep_addrb0/1(in)
  alsbs_slice/1 -> rep_addra0/1(in)
  dina/1 -> ddina0/1
  wea/1 -> rep_wea0/1(in)
  dinb/1 -> ddinb0/1
  web/1 -> rep_web0/1(in)
  rep_addrb0/1(out) -> debus_addrb0/1(bus_in)
  rep_addra0/1(out) -> debus_addra0/1(bus_in)
  ddina0/1 -> debus_dina0/1(bus_in)
  rep_wea0/1(out) -> debus_wea0/1(bus_in)
  ddinb0/1 -> debus_dinb0/1(bus_in)
  rep_web0/1(out) -> debus_web0/1(bus_in)
  debus_addra0/1(msb_out4) -> bram0_0/1
  debus_dina0/1(msb_out4) -> bram0_0/2
  debus_wea0/1(msb_out4) -> bram0_0/3
  debus_addrb0/1(msb_out4) -> bram0_0/4
  debus_dinb0/1(msb_out4) -> bram0_0/5
  debus_web0/1(msb_out4) -> bram0_0/6
  debus_addra0/2(out3) -> bram0_1/1
  debus_dina0/2(out3) -> bram0_1/2
  debus_wea0/2(out3) -> bram0_1/3
  debus_addrb0/2(out3) -> bram0_1/4
  debus_dinb0/2(out3) -> bram0_1/5
  debus_web0/2(out3) -> bram0_1/6
  debus_addra0/3(out2) -> bram0_2/1
  debus_dina0/3(out2) -> bram0_2/2
  debus_wea0/3(out2) -> bram0_2/3
  debus_addrb0/3(out2) -> bram0_2/4
  debus_dinb0/3(out2) -> bram0_2/5
  debus_web0/3(out2) -> bram0_2/6
  debus_addra0/4(lsb_out1) -> bram0_3/1
  debus_dina0/4(lsb_out1) -> bram0_3/2
  debus_wea0/4(lsb_out1) -> bram0_3/3
  debus_addrb0/4(lsb_out1) -> bram0_3/4
  debus_dinb0/4(lsb_out1) -> bram0_3/5
  debus_web0/4(lsb_out1) -> bram0_3/6
  bram0_0/1 -> A_bussify0/1(in1)
  bram0_0/2 -> B_bussify0/1(in1)
  bram0_1/1 -> A_bussify0/2(in2)
  bram0_1/2 -> B_bussify0/2(in2)
  bram0_2/1 -> A_bussify0/3(in3)
  bram0_2/2 -> B_bussify0/3(in3)
  bram0_3/1 -> A_bussify0/4(in4)
  bram0_3/2 -> B_bussify0/4(in4)
  A_bussify0/1(bus_out) -> A/1
  B_bussify0/1(bus_out) -> B/1
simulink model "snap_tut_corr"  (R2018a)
settings: Solver=VariableStepDiscrete  StartTime=0.0  StopTime=100  RelTol=1e-3
undefined symbols (not defined in the file): Area, behavioral, Behavioral, Bit, Both, BRAM, bram, c, core, d, Falling, getfield, hamming, hex2dec, led, Location, logic, Lower, Minimum_Area, out, quant0, quant1, quant2, reg, repmat, Rising, ROACH, ROACH2, SNAP, Speed, sync_in, Truncate, Unsigned, Upper, Width, Wrap, xc7k160t
libraries: xbsIndex_r4 x17901, casper_library_misc x29, xbsReplacements_r4 x20, casper_library_delays x14, xps_library x5
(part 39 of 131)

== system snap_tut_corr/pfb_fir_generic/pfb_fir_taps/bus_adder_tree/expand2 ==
  bus_in : Inport
  reinterpret{1..12} (12 alike) : xbsIndex_r4/Reinterpret  force_arith_type=on  arith_type="Signed  (2's comp)"  force_bin_pt=on  bin_pt=24  block_type=reinterpret
  slice1 : xbsIndex_r4/Slice  nbits=26  boolean_output=off  mode=Upper Bit Location + Width  bit1=-286  base1=MSB of Input  bit0=0  base0=LSB of Input  dbl_ovrd=off  block_type=slice
  slice10 : xbsIndex_r4/Slice  nbits=26  boolean_output=off  mode=Upper Bit Location + Width  bit1=-52  base1=MSB of Input  bit0=0  base0=LSB of Input  dbl_ovrd=off  block_type=slice
  slice11 : xbsIndex_r4/Slice  nbits=26  boolean_output=off  mode=Upper Bit Location + Width  bit1=-26  base1=MSB of Input  bit0=0  base0=LSB of Input  dbl_ovrd=off  block_type=slice
  slice12 : xbsIndex_r4/Slice  nbits=26  boolean_output=off  mode=Upper Bit Location + Width  bit1=0  base1=MSB of Input  bit0=0  base0=LSB of Input  dbl_ovrd=off  block_type=slice
  slice2 : xbsIndex_r4/Slice  nbits=26  boolean_output=off  mode=Upper Bit Location + Width  bit1=-260  base1=MSB of Input  bit0=0  base0=LSB of Input  dbl_ovrd=off  block_type=slice
  slice3 : xbsIndex_r4/Slice  nbits=26  boolean_output=off  mode=Upper Bit Location + Width  bit1=-234  base1=MSB of Input  bit0=0  base0=LSB of Input  dbl_ovrd=off  block_type=slice
  slice4 : xbsIndex_r4/Slice  nbits=26  boolean_output=off  mode=Upper Bit Location + Width  bit1=-208  base1=MSB of Input  bit0=0  base0=LSB of Input  dbl_ovrd=off  block_type=slice
  slice5 : xbsIndex_r4/Slice  nbits=26  boolean_output=off  mode=Upper Bit Location + Width  bit1=-182  base1=MSB of Input  bit0=0  base0=LSB of Input  dbl_ovrd=off  block_type=slice
  slice6 : xbsIndex_r4/Slice  nbits=26  boolean_output=off  mode=Upper Bit Location + Width  bit1=-156  base1=MSB of Input  bit0=0  base0=LSB of Input  dbl_ovrd=off  block_type=slice
  slice7 : xbsIndex_r4/Slice  nbits=26  boolean_output=off  mode=Upper Bit Location + Width  bit1=-130  base1=MSB of Input  bit0=0  base0=LSB of Input  dbl_ovrd=off  block_type=slice
  slice8 : xbsIndex_r4/Slice  nbits=26  boolean_output=off  mode=Upper Bit Location + Width  bit1=-104  base1=MSB of Input  bit0=0  base0=LSB of Input  dbl_ovrd=off  block_type=slice
  slice9 : xbsIndex_r4/Slice  nbits=26  boolean_output=off  mode=Upper Bit Location + Width  bit1=-78  base1=MSB of Input  bit0=0  base0=LSB of Input  dbl_ovrd=off  block_type=slice
  msb_out12 : Outport
  out11 : Outport  Port=2
  out10 : Outport  Port=3
  out9 : Outport  Port=4
  out8 : Outport  Port=5
  out7 : Outport  Port=6
  out6 : Outport  Port=7
  out5 : Outport  Port=8
  out4 : Outport  Port=9
  out3 : Outport  Port=10
  out2 : Outport  Port=11
  lsb_out1 : Outport  Port=12
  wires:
  bus_in/1 -> slice12/1, slice11/1, slice10/1, slice9/1, slice8/1, slice7/1, slice6/1, slice5/1, slice4/1, slice3/1, slice2/1, slice1/1
  slice12/1 -> reinterpret12/1
  reinterpret12/1 -> msb_out12/1
  slice11/1 -> reinterpret11/1
  reinterpret11/1 -> out11/1
  slice10/1 -> reinterpret10/1
  reinterpret10/1 -> out10/1
  slice9/1 -> reinterpret9/1
  reinterpret9/1 -> out9/1
  slice8/1 -> reinterpret8/1
  reinterpret8/1 -> out8/1
  slice7/1 -> reinterpret7/1
  reinterpret7/1 -> out7/1
  slice6/1 -> reinterpret6/1
  reinterpret6/1 -> out6/1
  slice5/1 -> reinterpret5/1
  reinterpret5/1 -> out5/1
  slice4/1 -> reinterpret4/1
  reinterpret4/1 -> out4/1
  slice3/1 -> reinterpret3/1
  reinterpret3/1 -> out3/1
  slice2/1 -> reinterpret2/1
  reinterpret2/1 -> out2/1
  slice1/1 -> reinterpret1/1
  reinterpret1/1 -> lsb_out1/1

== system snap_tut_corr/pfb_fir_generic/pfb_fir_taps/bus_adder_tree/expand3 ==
  bus_in : Inport
  reinterpret{1..12} (12 alike) : xbsIndex_r4/Reinterpret  force_arith_type=on  arith_type="Signed  (2's comp)"  force_bin_pt=on  bin_pt=24  block_type=reinterpret
  slice1 : xbsIndex_r4/Slice  nbits=26  boolean_output=off  mode=Upper Bit Location + Width  bit1=-286  base1=MSB of Input  bit0=0  base0=LSB of Input  dbl_ovrd=off  block_type=slice
  slice10 : xbsIndex_r4/Slice  nbits=26  boolean_output=off  mode=Upper Bit Location + Width  bit1=-52  base1=MSB of Input  bit0=0  base0=LSB of Input  dbl_ovrd=off  block_type=slice
  slice11 : xbsIndex_r4/Slice  nbits=26  boolean_output=off  mode=Upper Bit Location + Width  bit1=-26  base1=MSB of Input  bit0=0  base0=LSB of Input  dbl_ovrd=off  block_type=slice
  slice12 : xbsIndex_r4/Slice  nbits=26  boolean_output=off  mode=Upper Bit Location + Width  bit1=0  base1=MSB of Input  bit0=0  base0=LSB of Input  dbl_ovrd=off  block_type=slice
  slice2 : xbsIndex_r4/Slice  nbits=26  boolean_output=off  mode=Upper Bit Location + Width  bit1=-260  base1=MSB of Input  bit0=0  base0=LSB of Input  dbl_ovrd=off  block_type=slice
  slice3 : xbsIndex_r4/Slice  nbits=26  boolean_output=off  mode=Upper Bit Location + Width  bit1=-234  base1=MSB of Input  bit0=0  base0=LSB of Input  dbl_ovrd=off  block_type=slice
  slice4 : xbsIndex_r4/Slice  nbits=26  boolean_output=off  mode=Upper Bit Location + Width  bit1=-208  base1=MSB of Input  bit0=0  base0=LSB of Input  dbl_ovrd=off  block_type=slice
  slice5 : xbsIndex_r4/Slice  nbits=26  boolean_output=off  mode=Upper Bit Location + Width  bit1=-182  base1=MSB of Input  bit0=0  base0=LSB of Input  dbl_ovrd=off  block_type=slice
  slice6 : xbsIndex_r4/Slice  nbits=26  boolean_output=off  mode=Upper Bit Location + Width  bit1=-156  base1=MSB of Input  bit0=0  base0=LSB of Input  dbl_ovrd=off  block_type=slice
  slice7 : xbsIndex_r4/Slice  nbits=26  boolean_output=off  mode=Upper Bit Location + Width  bit1=-130  base1=MSB of Input  bit0=0  base0=LSB of Input  dbl_ovrd=off  block_type=slice
  slice8 : xbsIndex_r4/Slice  nbits=26  boolean_output=off  mode=Upper Bit Location + Width  bit1=-104  base1=MSB of Input  bit0=0  base0=LSB of Input  dbl_ovrd=off  block_type=slice
  slice9 : xbsIndex_r4/Slice  nbits=26  boolean_output=off  mode=Upper Bit Location + Width  bit1=-78  base1=MSB of Input  bit0=0  base0=LSB of Input  dbl_ovrd=off  block_type=slice
  msb_out12 : Outport
  out11 : Outport  Port=2
  out10 : Outport  Port=3
  out9 : Outport  Port=4
  out8 : Outport  Port=5
  out7 : Outport  Port=6
  out6 : Outport  Port=7
  out5 : Outport  Port=8
  out4 : Outport  Port=9
  out3 : Outport  Port=10
  out2 : Outport  Port=11
  lsb_out1 : Outport  Port=12
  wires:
  bus_in/1 -> slice12/1, slice11/1, slice10/1, slice9/1, slice8/1, slice7/1, slice6/1, slice5/1, slice4/1, slice3/1, slice2/1, slice1/1
  slice12/1 -> reinterpret12/1
  reinterpret12/1 -> msb_out12/1
  slice11/1 -> reinterpret11/1
  reinterpret11/1 -> out11/1
  slice10/1 -> reinterpret10/1
  reinterpret10/1 -> out10/1
  slice9/1 -> reinterpret9/1
  reinterpret9/1 -> out9/1
  slice8/1 -> reinterpret8/1
  reinterpret8/1 -> out8/1
  slice7/1 -> reinterpret7/1
  reinterpret7/1 -> out7/1
  slice6/1 -> reinterpret6/1
  reinterpret6/1 -> out6/1
  slice5/1 -> reinterpret5/1
  reinterpret5/1 -> out5/1
  slice4/1 -> reinterpret4/1
  reinterpret4/1 -> out4/1
  slice3/1 -> reinterpret3/1
  reinterpret3/1 -> out3/1
  slice2/1 -> reinterpret2/1
  reinterpret2/1 -> out2/1
  slice1/1 -> reinterpret1/1
  reinterpret1/1 -> lsb_out1/1

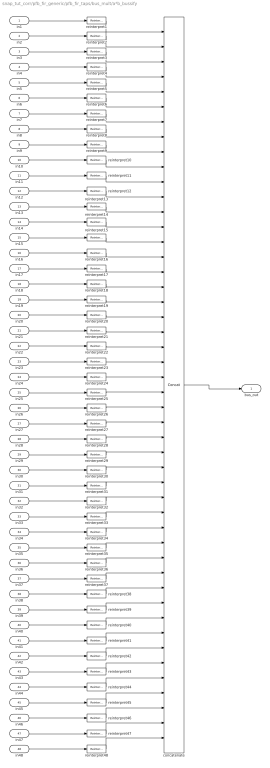
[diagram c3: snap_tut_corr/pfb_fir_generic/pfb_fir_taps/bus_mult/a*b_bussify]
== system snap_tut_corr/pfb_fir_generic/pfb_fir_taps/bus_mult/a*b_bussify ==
  in1 : Inport
  in2 : Inport  Port=2
  in3 : Inport  Port=3
  in4 : Inport  Port=4
  in5 : Inport  Port=5
  in6 : Inport  Port=6
  in7 : Inport  Port=7
  in8 : Inport  Port=8
  in9 : Inport  Port=9
  in10 : Inport  Port=10
  in11 : Inport  Port=11
  in12 : Inport  Port=12
  in13 : Inport  Port=13
  in14 : Inport  Port=14
  in15 : Inport  Port=15
  in16 : Inport  Port=16
  in17 : Inport  Port=17
  in18 : Inport  Port=18
  in19 : Inport  Port=19
  in20 : Inport  Port=20
  in21 : Inport  Port=21
  in22 : Inport  Port=22
  in23 : Inport  Port=23
  in24 : Inport  Port=24
  in25 : Inport  Port=25
  in26 : Inport  Port=26
  in27 : Inport  Port=27
  in28 : Inport  Port=28
  in29 : Inport  Port=29
  in30 : Inport  Port=30
  in31 : Inport  Port=31
  in32 : Inport  Port=32
  in33 : Inport  Port=33
  in34 : Inport  Port=34
  in35 : Inport  Port=35
  in36 : Inport  Port=36
  in37 : Inport  Port=37
  in38 : Inport  Port=38
  in39 : Inport  Port=39
  in40 : Inport  Port=40
  in41 : Inport  Port=41
  in42 : Inport  Port=42
  in43 : Inport  Port=43
  in44 : Inport  Port=44
  in45 : Inport  Port=45
  in46 : Inport  Port=46
  in47 : Inport  Port=47
  in48 : Inport  Port=48
  concatenate : xbsIndex_r4/Concat  num_inputs=48  dbl_ovrd=off  block_type=concat
  reinterpret{1..48} (48 alike) : xbsIndex_r4/Reinterpret  force_arith_type=on  arith_type=Unsigned  force_bin_pt=on  bin_pt=0  block_type=reinterpret
  bus_out : Outport
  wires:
  concatenate/1 -> bus_out/1
  in1/1 -> reinterpret1/1
  reinterpret1/1 -> concatenate/1
  in2/1 -> reinterpret2/1
  reinterpret2/1 -> concatenate/2
  in3/1 -> reinterpret3/1
  reinterpret3/1 -> concatenate/3
  in4/1 -> reinterpret4/1
  reinterpret4/1 -> concatenate/4
  in5/1 -> reinterpret5/1
  reinterpret5/1 -> concatenate/5
  in6/1 -> reinterpret6/1
  reinterpret6/1 -> concatenate/6
  in7/1 -> reinterpret7/1
  reinterpret7/1 -> concatenate/7
  in8/1 -> reinterpret8/1
  reinterpret8/1 -> concatenate/8
  in9/1 -> reinterpret9/1
  reinterpret9/1 -> concatenate/9
  in10/1 -> reinterpret10/1
  reinterpret10/1 -> concatenate/10
  in11/1 -> reinterpret11/1
  reinterpret11/1 -> concatenate/11
  in12/1 -> reinterpret12/1
  reinterpret12/1 -> concatenate/12
  in13/1 -> reinterpret13/1
  reinterpret13/1 -> concatenate/13
  in14/1 -> reinterpret14/1
  reinterpret14/1 -> concatenate/14
  in15/1 -> reinterpret15/1
  reinterpret15/1 -> concatenate/15
  in16/1 -> reinterpret16/1
  reinterpret16/1 -> concatenate/16
  in17/1 -> reinterpret17/1
  reinterpret17/1 -> concatenate/17
  in18/1 -> reinterpret18/1
  reinterpret18/1 -> concatenate/18
  in19/1 -> reinterpret19/1
  reinterpret19/1 -> concatenate/19
  in20/1 -> reinterpret20/1
  reinterpret20/1 -> concatenate/20
  in21/1 -> reinterpret21/1
  reinterpret21/1 -> concatenate/21
  in22/1 -> reinterpret22/1
  reinterpret22/1 -> concatenate/22
  in23/1 -> reinterpret23/1
  reinterpret23/1 -> concatenate/23
  in24/1 -> reinterpret24/1
  reinterpret24/1 -> concatenate/24
  in25/1 -> reinterpret25/1
  reinterpret25/1 -> concatenate/25
  in26/1 -> reinterpret26/1
  reinterpret26/1 -> concatenate/26
  in27/1 -> reinterpret27/1
  reinterpret27/1 -> concatenate/27
  in28/1 -> reinterpret28/1
  reinterpret28/1 -> concatenate/28
  in29/1 -> reinterpret29/1
  reinterpret29/1 -> concatenate/29
  in30/1 -> reinterpret30/1
  reinterpret30/1 -> concatenate/30
  in31/1 -> reinterpret31/1
  reinterpret31/1 -> concatenate/31
  in32/1 -> reinterpret32/1
  reinterpret32/1 -> concatenate/32
  in33/1 -> reinterpret33/1
  reinterpret33/1 -> concatenate/33
  in34/1 -> reinterpret34/1
  reinterpret34/1 -> concatenate/34
  in35/1 -> reinterpret35/1
  reinterpret35/1 -> concatenate/35
  in36/1 -> reinterpret36/1
  reinterpret36/1 -> concatenate/36
  in37/1 -> reinterpret37/1
  reinterpret37/1 -> concatenate/37
  in38/1 -> reinterpret38/1
  reinterpret38/1 -> concatenate/38
  in39/1 -> reinterpret39/1
  reinterpret39/1 -> concatenate/39
  in40/1 -> reinterpret40/1
  reinterpret40/1 -> concatenate/40
  in41/1 -> reinterpret41/1
  reinterpret41/1 -> concatenate/41
  in42/1 -> reinterpret42/1
  reinterpret42/1 -> concatenate/42
  in43/1 -> reinterpret43/1
  reinterpret43/1 -> concatenate/43
  in44/1 -> reinterpret44/1
  reinterpret44/1 -> concatenate/44
  in45/1 -> reinterpret45/1
  reinterpret45/1 -> concatenate/45
  in46/1 -> reinterpret46/1
  reinterpret46/1 -> concatenate/46
  in47/1 -> reinterpret47/1
  reinterpret47/1 -> concatenate/47
  in48/1 -> reinterpret48/1
  reinterpret48/1 -> concatenate/48

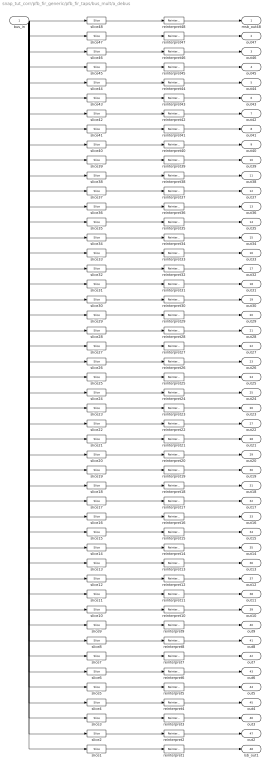
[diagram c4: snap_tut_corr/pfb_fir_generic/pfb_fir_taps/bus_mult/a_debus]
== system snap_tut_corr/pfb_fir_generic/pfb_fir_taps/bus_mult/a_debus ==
  bus_in : Inport
  reinterpret{1..48} (48 alike) : xbsIndex_r4/Reinterpret  force_arith_type=on  arith_type="Signed  (2's comp)"  force_bin_pt=on  bin_pt=7  block_type=reinterpret
  slice1 : xbsIndex_r4/Slice  nbits=8  boolean_output=off  mode=Upper Bit Location + Width  bit1=-376  base1=MSB of Input  bit0=0  base0=LSB of Input  dbl_ovrd=off  block_type=slice
  slice10 : xbsIndex_r4/Slice  nbits=8  boolean_output=off  mode=Upper Bit Location + Width  bit1=-304  base1=MSB of Input  bit0=0  base0=LSB of Input  dbl_ovrd=off  block_type=slice
  slice11 : xbsIndex_r4/Slice  nbits=8  boolean_output=off  mode=Upper Bit Location + Width  bit1=-296  base1=MSB of Input  bit0=0  base0=LSB of Input  dbl_ovrd=off  block_type=slice
  slice12 : xbsIndex_r4/Slice  nbits=8  boolean_output=off  mode=Upper Bit Location + Width  bit1=-288  base1=MSB of Input  bit0=0  base0=LSB of Input  dbl_ovrd=off  block_type=slice
  slice13 : xbsIndex_r4/Slice  nbits=8  boolean_output=off  mode=Upper Bit Location + Width  bit1=-280  base1=MSB of Input  bit0=0  base0=LSB of Input  dbl_ovrd=off  block_type=slice
  slice14 : xbsIndex_r4/Slice  nbits=8  boolean_output=off  mode=Upper Bit Location + Width  bit1=-272  base1=MSB of Input  bit0=0  base0=LSB of Input  dbl_ovrd=off  block_type=slice
  slice15 : xbsIndex_r4/Slice  nbits=8  boolean_output=off  mode=Upper Bit Location + Width  bit1=-264  base1=MSB of Input  bit0=0  base0=LSB of Input  dbl_ovrd=off  block_type=slice
  slice16 : xbsIndex_r4/Slice  nbits=8  boolean_output=off  mode=Upper Bit Location + Width  bit1=-256  base1=MSB of Input  bit0=0  base0=LSB of Input  dbl_ovrd=off  block_type=slice
  slice17 : xbsIndex_r4/Slice  nbits=8  boolean_output=off  mode=Upper Bit Location + Width  bit1=-248  base1=MSB of Input  bit0=0  base0=LSB of Input  dbl_ovrd=off  block_type=slice
  slice18 : xbsIndex_r4/Slice  nbits=8  boolean_output=off  mode=Upper Bit Location + Width  bit1=-240  base1=MSB of Input  bit0=0  base0=LSB of Input  dbl_ovrd=off  block_type=slice
  slice19 : xbsIndex_r4/Slice  nbits=8  boolean_output=off  mode=Upper Bit Location + Width  bit1=-232  base1=MSB of Input  bit0=0  base0=LSB of Input  dbl_ovrd=off  block_type=slice
  slice2 : xbsIndex_r4/Slice  nbits=8  boolean_output=off  mode=Upper Bit Location + Width  bit1=-368  base1=MSB of Input  bit0=0  base0=LSB of Input  dbl_ovrd=off  block_type=slice
  slice20 : xbsIndex_r4/Slice  nbits=8  boolean_output=off  mode=Upper Bit Location + Width  bit1=-224  base1=MSB of Input  bit0=0  base0=LSB of Input  dbl_ovrd=off  block_type=slice
  slice21 : xbsIndex_r4/Slice  nbits=8  boolean_output=off  mode=Upper Bit Location + Width  bit1=-216  base1=MSB of Input  bit0=0  base0=LSB of Input  dbl_ovrd=off  block_type=slice
  slice22 : xbsIndex_r4/Slice  nbits=8  boolean_output=off  mode=Upper Bit Location + Width  bit1=-208  base1=MSB of Input  bit0=0  base0=LSB of Input  dbl_ovrd=off  block_type=slice
  slice23 : xbsIndex_r4/Slice  nbits=8  boolean_output=off  mode=Upper Bit Location + Width  bit1=-200  base1=MSB of Input  bit0=0  base0=LSB of Input  dbl_ovrd=off  block_type=slice
  slice24 : xbsIndex_r4/Slice  nbits=8  boolean_output=off  mode=Upper Bit Location + Width  bit1=-192  base1=MSB of Input  bit0=0  base0=LSB of Input  dbl_ovrd=off  block_type=slice
  slice25 : xbsIndex_r4/Slice  nbits=8  boolean_output=off  mode=Upper Bit Location + Width  bit1=-184  base1=MSB of Input  bit0=0  base0=LSB of Input  dbl_ovrd=off  block_type=slice
  slice26 : xbsIndex_r4/Slice  nbits=8  boolean_output=off  mode=Upper Bit Location + Width  bit1=-176  base1=MSB of Input  bit0=0  base0=LSB of Input  dbl_ovrd=off  block_type=slice
  slice27 : xbsIndex_r4/Slice  nbits=8  boolean_output=off  mode=Upper Bit Location + Width  bit1=-168  base1=MSB of Input  bit0=0  base0=LSB of Input  dbl_ovrd=off  block_type=slice
  slice28 : xbsIndex_r4/Slice  nbits=8  boolean_output=off  mode=Upper Bit Location + Width  bit1=-160  base1=MSB of Input  bit0=0  base0=LSB of Input  dbl_ovrd=off  block_type=slice
  slice29 : xbsIndex_r4/Slice  nbits=8  boolean_output=off  mode=Upper Bit Location + Width  bit1=-152  base1=MSB of Input  bit0=0  base0=LSB of Input  dbl_ovrd=off  block_type=slice
  slice3 : xbsIndex_r4/Slice  nbits=8  boolean_output=off  mode=Upper Bit Location + Width  bit1=-360  base1=MSB of Input  bit0=0  base0=LSB of Input  dbl_ovrd=off  block_type=slice
  slice30 : xbsIndex_r4/Slice  nbits=8  boolean_output=off  mode=Upper Bit Location + Width  bit1=-144  base1=MSB of Input  bit0=0  base0=LSB of Input  dbl_ovrd=off  block_type=slice
  slice31 : xbsIndex_r4/Slice  nbits=8  boolean_output=off  mode=Upper Bit Location + Width  bit1=-136  base1=MSB of Input  bit0=0  base0=LSB of Input  dbl_ovrd=off  block_type=slice
  slice32 : xbsIndex_r4/Slice  nbits=8  boolean_output=off  mode=Upper Bit Location + Width  bit1=-128  base1=MSB of Input  bit0=0  base0=LSB of Input  dbl_ovrd=off  block_type=slice
  slice33 : xbsIndex_r4/Slice  nbits=8  boolean_output=off  mode=Upper Bit Location + Width  bit1=-120  base1=MSB of Input  bit0=0  base0=LSB of Input  dbl_ovrd=off  block_type=slice
  slice34 : xbsIndex_r4/Slice  nbits=8  boolean_output=off  mode=Upper Bit Location + Width  bit1=-112  base1=MSB of Input  bit0=0  base0=LSB of Input  dbl_ovrd=off  block_type=slice
  slice35 : xbsIndex_r4/Slice  nbits=8  boolean_output=off  mode=Upper Bit Location + Width  bit1=-104  base1=MSB of Input  bit0=0  base0=LSB of Input  dbl_ovrd=off  block_type=slice
  slice36 : xbsIndex_r4/Slice  nbits=8  boolean_output=off  mode=Upper Bit Location + Width  bit1=-96  base1=MSB of Input  bit0=0  base0=LSB of Input  dbl_ovrd=off  block_type=slice
  slice37 : xbsIndex_r4/Slice  nbits=8  boolean_output=off  mode=Upper Bit Location + Width  bit1=-88  base1=MSB of Input  bit0=0  base0=LSB of Input  dbl_ovrd=off  block_type=slice
  slice38 : xbsIndex_r4/Slice  nbits=8  boolean_output=off  mode=Upper Bit Location + Width  bit1=-80  base1=MSB of Input  bit0=0  base0=LSB of Input  dbl_ovrd=off  block_type=slice
  slice39 : xbsIndex_r4/Slice  nbits=8  boolean_output=off  mode=Upper Bit Location + Width  bit1=-72  base1=MSB of Input  bit0=0  base0=LSB of Input  dbl_ovrd=off  block_type=slice
  slice4 : xbsIndex_r4/Slice  nbits=8  boolean_output=off  mode=Upper Bit Location + Width  bit1=-352  base1=MSB of Input  bit0=0  base0=LSB of Input  dbl_ovrd=off  block_type=slice
  slice40 : xbsIndex_r4/Slice  nbits=8  boolean_output=off  mode=Upper Bit Location + Width  bit1=-64  base1=MSB of Input  bit0=0  base0=LSB of Input  dbl_ovrd=off  block_type=slice
  slice41 : xbsIndex_r4/Slice  nbits=8  boolean_output=off  mode=Upper Bit Location + Width  bit1=-56  base1=MSB of Input  bit0=0  base0=LSB of Input  dbl_ovrd=off  block_type=slice
  slice42 : xbsIndex_r4/Slice  nbits=8  boolean_output=off  mode=Upper Bit Location + Width  bit1=-48  base1=MSB of Input  bit0=0  base0=LSB of Input  dbl_ovrd=off  block_type=slice
  slice43 : xbsIndex_r4/Slice  nbits=8  boolean_output=off  mode=Upper Bit Location + Width  bit1=-40  base1=MSB of Input  bit0=0  base0=LSB of Input  dbl_ovrd=off  block_type=slice
  slice44 : xbsIndex_r4/Slice  nbits=8  boolean_output=off  mode=Upper Bit Location + Width  bit1=-32  base1=MSB of Input  bit0=0  base0=LSB of Input  dbl_ovrd=off  block_type=slice
  slice45 : xbsIndex_r4/Slice  nbits=8  boolean_output=off  mode=Upper Bit Location + Width  bit1=-24  base1=MSB of Input  bit0=0  base0=LSB of Input  dbl_ovrd=off  block_type=slice
  slice46 : xbsIndex_r4/Slice  nbits=8  boolean_output=off  mode=Upper Bit Location + Width  bit1=-16  base1=MSB of Input  bit0=0  base0=LSB of Input  dbl_ovrd=off  block_type=slice
  slice47 : xbsIndex_r4/Slice  nbits=8  boolean_output=off  mode=Upper Bit Location + Width  bit1=-8  base1=MSB of Input  bit0=0  base0=LSB of Input  dbl_ovrd=off  block_type=slice
  slice48 : xbsIndex_r4/Slice  nbits=8  boolean_output=off  mode=Upper Bit Location + Width  bit1=0  base1=MSB of Input  bit0=0  base0=LSB of Input  dbl_ovrd=off  block_type=slice
  slice5 : xbsIndex_r4/Slice  nbits=8  boolean_output=off  mode=Upper Bit Location + Width  bit1=-344  base1=MSB of Input  bit0=0  base0=LSB of Input  dbl_ovrd=off  block_type=slice
  slice6 : xbsIndex_r4/Slice  nbits=8  boolean_output=off  mode=Upper Bit Location + Width  bit1=-336  base1=MSB of Input  bit0=0  base0=LSB of Input  dbl_ovrd=off  block_type=slice
  slice7 : xbsIndex_r4/Slice  nbits=8  boolean_output=off  mode=Upper Bit Location + Width  bit1=-328  base1=MSB of Input  bit0=0  base0=LSB of Input  dbl_ovrd=off  block_type=slice
  slice8 : xbsIndex_r4/Slice  nbits=8  boolean_output=off  mode=Upper Bit Location + Width  bit1=-320  base1=MSB of Input  bit0=0  base0=LSB of Input  dbl_ovrd=off  block_type=slice
  slice9 : xbsIndex_r4/Slice  nbits=8  boolean_output=off  mode=Upper Bit Location + Width  bit1=-312  base1=MSB of Input  bit0=0  base0=LSB of Input  dbl_ovrd=off  block_type=slice
  msb_out48 : Outport
  out47 : Outport  Port=2
  out46 : Outport  Port=3
  out45 : Outport  Port=4
  out44 : Outport  Port=5
  out43 : Outport  Port=6
  out42 : Outport  Port=7
  out41 : Outport  Port=8
  out40 : Outport  Port=9
  out39 : Outport  Port=10
  out38 : Outport  Port=11
  out37 : Outport  Port=12
  out36 : Outport  Port=13
  out35 : Outport  Port=14
  out34 : Outport  Port=15
  out33 : Outport  Port=16
  out32 : Outport  Port=17
  out31 : Outport  Port=18
  out30 : Outport  Port=19
  out29 : Outport  Port=20
  out28 : Outport  Port=21
  out27 : Outport  Port=22
  out26 : Outport  Port=23
  out25 : Outport  Port=24
  out24 : Outport  Port=25
  out23 : Outport  Port=26
  out22 : Outport  Port=27
  out21 : Outport  Port=28
  out20 : Outport  Port=29
  out19 : Outport  Port=30
  out18 : Outport  Port=31
  out17 : Outport  Port=32
  out16 : Outport  Port=33
  out15 : Outport  Port=34
  out14 : Outport  Port=35
  out13 : Outport  Port=36
  out12 : Outport  Port=37
  out11 : Outport  Port=38
  out10 : Outport  Port=39
  out9 : Outport  Port=40
  out8 : Outport  Port=41
  out7 : Outport  Port=42
  out6 : Outport  Port=43
  out5 : Outport  Port=44
  out4 : Outport  Port=45
  out3 : Outport  Port=46
  out2 : Outport  Port=47
  lsb_out1 : Outport  Port=48
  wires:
  bus_in/1 -> slice48/1, slice47/1, slice46/1, slice45/1, slice44/1, slice43/1, slice42/1, slice41/1, slice40/1, slice39/1, slice38/1, slice37/1, slice36/1, slice35/1, slice34/1, slice33/1, slice32/1, slice31/1, slice30/1, slice29/1, slice28/1, slice27/1, slice26/1, slice25/1, slice24/1, slice23/1, slice22/1, slice21/1, slice20/1, slice19/1, slice18/1, slice17/1, slice16/1, slice15/1, slice14/1, slice13/1, slice12/1, slice11/1, slice10/1, slice9/1, slice8/1, slice7/1, slice6/1, slice5/1, slice4/1, slice3/1, slice2/1, slice1/1
  slice48/1 -> reinterpret48/1
  reinterpret48/1 -> msb_out48/1
  slice47/1 -> reinterpret47/1
  reinterpret47/1 -> out47/1
  slice46/1 -> reinterpret46/1
  reinterpret46/1 -> out46/1
  slice45/1 -> reinterpret45/1
  reinterpret45/1 -> out45/1
  slice44/1 -> reinterpret44/1
  reinterpret44/1 -> out44/1
  slice43/1 -> reinterpret43/1
  reinterpret43/1 -> out43/1
  slice42/1 -> reinterpret42/1
  reinterpret42/1 -> out42/1
  slice41/1 -> reinterpret41/1
  reinterpret41/1 -> out41/1
  slice40/1 -> reinterpret40/1
  reinterpret40/1 -> out40/1
  slice39/1 -> reinterpret39/1
  reinterpret39/1 -> out39/1
  slice38/1 -> reinterpret38/1
  reinterpret38/1 -> out38/1
  slice37/1 -> reinterpret37/1
  reinterpret37/1 -> out37/1
  slice36/1 -> reinterpret36/1
  reinterpret36/1 -> out36/1
  slice35/1 -> reinterpret35/1
  reinterpret35/1 -> out35/1
  slice34/1 -> reinterpret34/1
  reinterpret34/1 -> out34/1
  slice33/1 -> reinterpret33/1
  reinterpret33/1 -> out33/1
  slice32/1 -> reinterpret32/1
  reinterpret32/1 -> out32/1
  slice31/1 -> reinterpret31/1
  reinterpret31/1 -> out31/1
  slice30/1 -> reinterpret30/1
  reinterpret30/1 -> out30/1
  slice29/1 -> reinterpret29/1
  reinterpret29/1 -> out29/1
  slice28/1 -> reinterpret28/1
  reinterpret28/1 -> out28/1
  slice27/1 -> reinterpret27/1
  reinterpret27/1 -> out27/1
  slice26/1 -> reinterpret26/1
  reinterpret26/1 -> out26/1
  slice25/1 -> reinterpret25/1
  reinterpret25/1 -> out25/1
  slice24/1 -> reinterpret24/1
  reinterpret24/1 -> out24/1
  slice23/1 -> reinterpret23/1
  reinterpret23/1 -> out23/1
  slice22/1 -> reinterpret22/1
  reinterpret22/1 -> out22/1
  slice21/1 -> reinterpret21/1
  reinterpret21/1 -> out21/1
  slice20/1 -> reinterpret20/1
  reinterpret20/1 -> out20/1
  slice19/1 -> reinterpret19/1
  reinterpret19/1 -> out19/1
  slice18/1 -> reinterpret18/1
  reinterpret18/1 -> out18/1
  slice17/1 -> reinterpret17/1
  reinterpret17/1 -> out17/1
  slice16/1 -> reinterpret16/1
  reinterpret16/1 -> out16/1
  slice15/1 -> reinterpret15/1
  reinterpret15/1 -> out15/1
  slice14/1 -> reinterpret14/1
  reinterpret14/1 -> out14/1
  slice13/1 -> reinterpret13/1
  reinterpret13/1 -> out13/1
  slice12/1 -> reinterpret12/1
  reinterpret12/1 -> out12/1
  slice11/1 -> reinterpret11/1
  reinterpret11/1 -> out11/1
  slice10/1 -> reinterpret10/1
  reinterpret10/1 -> out10/1
  slice9/1 -> reinterpret9/1
  reinterpret9/1 -> out9/1
  slice8/1 -> reinterpret8/1
  reinterpret8/1 -> out8/1
  slice7/1 -> reinterpret7/1
  reinterpret7/1 -> out7/1
  slice6/1 -> reinterpret6/1
  reinterpret6/1 -> out6/1
  slice5/1 -> reinterpret5/1
  reinterpret5/1 -> out5/1
  slice4/1 -> reinterpret4/1
  reinterpret4/1 -> out4/1
  slice3/1 -> reinterpret3/1
  reinterpret3/1 -> out3/1
  slice2/1 -> reinterpret2/1
  reinterpret2/1 -> out2/1
  slice1/1 -> reinterpret1/1
  reinterpret1/1 -> lsb_out1/1

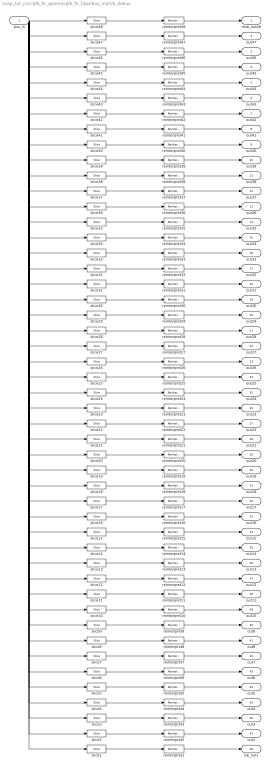
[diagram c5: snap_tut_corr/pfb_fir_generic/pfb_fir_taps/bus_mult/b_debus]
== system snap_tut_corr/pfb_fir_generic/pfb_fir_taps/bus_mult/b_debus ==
  bus_in : Inport
  reinterpret{1..48} (48 alike) : xbsIndex_r4/Reinterpret  force_arith_type=on  arith_type="Signed  (2's comp)"  force_bin_pt=on  bin_pt=17  block_type=reinterpret
  slice1 : xbsIndex_r4/Slice  nbits=18  boolean_output=off  mode=Upper Bit Location + Width  bit1=-846  base1=MSB of Input  bit0=0  base0=LSB of Input  dbl_ovrd=off  block_type=slice
  slice10 : xbsIndex_r4/Slice  nbits=18  boolean_output=off  mode=Upper Bit Location + Width  bit1=-684  base1=MSB of Input  bit0=0  base0=LSB of Input  dbl_ovrd=off  block_type=slice
  slice11 : xbsIndex_r4/Slice  nbits=18  boolean_output=off  mode=Upper Bit Location + Width  bit1=-666  base1=MSB of Input  bit0=0  base0=LSB of Input  dbl_ovrd=off  block_type=slice
  slice12 : xbsIndex_r4/Slice  nbits=18  boolean_output=off  mode=Upper Bit Location + Width  bit1=-648  base1=MSB of Input  bit0=0  base0=LSB of Input  dbl_ovrd=off  block_type=slice
  slice13 : xbsIndex_r4/Slice  nbits=18  boolean_output=off  mode=Upper Bit Location + Width  bit1=-630  base1=MSB of Input  bit0=0  base0=LSB of Input  dbl_ovrd=off  block_type=slice
  slice14 : xbsIndex_r4/Slice  nbits=18  boolean_output=off  mode=Upper Bit Location + Width  bit1=-612  base1=MSB of Input  bit0=0  base0=LSB of Input  dbl_ovrd=off  block_type=slice
  slice15 : xbsIndex_r4/Slice  nbits=18  boolean_output=off  mode=Upper Bit Location + Width  bit1=-594  base1=MSB of Input  bit0=0  base0=LSB of Input  dbl_ovrd=off  block_type=slice
  slice16 : xbsIndex_r4/Slice  nbits=18  boolean_output=off  mode=Upper Bit Location + Width  bit1=-576  base1=MSB of Input  bit0=0  base0=LSB of Input  dbl_ovrd=off  block_type=slice
  slice17 : xbsIndex_r4/Slice  nbits=18  boolean_output=off  mode=Upper Bit Location + Width  bit1=-558  base1=MSB of Input  bit0=0  base0=LSB of Input  dbl_ovrd=off  block_type=slice
  slice18 : xbsIndex_r4/Slice  nbits=18  boolean_output=off  mode=Upper Bit Location + Width  bit1=-540  base1=MSB of Input  bit0=0  base0=LSB of Input  dbl_ovrd=off  block_type=slice
  slice19 : xbsIndex_r4/Slice  nbits=18  boolean_output=off  mode=Upper Bit Location + Width  bit1=-522  base1=MSB of Input  bit0=0  base0=LSB of Input  dbl_ovrd=off  block_type=slice
  slice2 : xbsIndex_r4/Slice  nbits=18  boolean_output=off  mode=Upper Bit Location + Width  bit1=-828  base1=MSB of Input  bit0=0  base0=LSB of Input  dbl_ovrd=off  block_type=slice
  slice20 : xbsIndex_r4/Slice  nbits=18  boolean_output=off  mode=Upper Bit Location + Width  bit1=-504  base1=MSB of Input  bit0=0  base0=LSB of Input  dbl_ovrd=off  block_type=slice
  slice21 : xbsIndex_r4/Slice  nbits=18  boolean_output=off  mode=Upper Bit Location + Width  bit1=-486  base1=MSB of Input  bit0=0  base0=LSB of Input  dbl_ovrd=off  block_type=slice
  slice22 : xbsIndex_r4/Slice  nbits=18  boolean_output=off  mode=Upper Bit Location + Width  bit1=-468  base1=MSB of Input  bit0=0  base0=LSB of Input  dbl_ovrd=off  block_type=slice
  slice23 : xbsIndex_r4/Slice  nbits=18  boolean_output=off  mode=Upper Bit Location + Width  bit1=-450  base1=MSB of Input  bit0=0  base0=LSB of Input  dbl_ovrd=off  block_type=slice
  slice24 : xbsIndex_r4/Slice  nbits=18  boolean_output=off  mode=Upper Bit Location + Width  bit1=-432  base1=MSB of Input  bit0=0  base0=LSB of Input  dbl_ovrd=off  block_type=slice
  slice25 : xbsIndex_r4/Slice  nbits=18  boolean_output=off  mode=Upper Bit Location + Width  bit1=-414  base1=MSB of Input  bit0=0  base0=LSB of Input  dbl_ovrd=off  block_type=slice
  slice26 : xbsIndex_r4/Slice  nbits=18  boolean_output=off  mode=Upper Bit Location + Width  bit1=-396  base1=MSB of Input  bit0=0  base0=LSB of Input  dbl_ovrd=off  block_type=slice
  slice27 : xbsIndex_r4/Slice  nbits=18  boolean_output=off  mode=Upper Bit Location + Width  bit1=-378  base1=MSB of Input  bit0=0  base0=LSB of Input  dbl_ovrd=off  block_type=slice
  slice28 : xbsIndex_r4/Slice  nbits=18  boolean_output=off  mode=Upper Bit Location + Width  bit1=-360  base1=MSB of Input  bit0=0  base0=LSB of Input  dbl_ovrd=off  block_type=slice
  slice29 : xbsIndex_r4/Slice  nbits=18  boolean_output=off  mode=Upper Bit Location + Width  bit1=-342  base1=MSB of Input  bit0=0  base0=LSB of Input  dbl_ovrd=off  block_type=slice
  slice3 : xbsIndex_r4/Slice  nbits=18  boolean_output=off  mode=Upper Bit Location + Width  bit1=-810  base1=MSB of Input  bit0=0  base0=LSB of Input  dbl_ovrd=off  block_type=slice
  slice30 : xbsIndex_r4/Slice  nbits=18  boolean_output=off  mode=Upper Bit Location + Width  bit1=-324  base1=MSB of Input  bit0=0  base0=LSB of Input  dbl_ovrd=off  block_type=slice
  slice31 : xbsIndex_r4/Slice  nbits=18  boolean_output=off  mode=Upper Bit Location + Width  bit1=-306  base1=MSB of Input  bit0=0  base0=LSB of Input  dbl_ovrd=off  block_type=slice
  slice32 : xbsIndex_r4/Slice  nbits=18  boolean_output=off  mode=Upper Bit Location + Width  bit1=-288  base1=MSB of Input  bit0=0  base0=LSB of Input  dbl_ovrd=off  block_type=slice
  slice33 : xbsIndex_r4/Slice  nbits=18  boolean_output=off  mode=Upper Bit Location + Width  bit1=-270  base1=MSB of Input  bit0=0  base0=LSB of Input  dbl_ovrd=off  block_type=slice
  slice34 : xbsIndex_r4/Slice  nbits=18  boolean_output=off  mode=Upper Bit Location + Width  bit1=-252  base1=MSB of Input  bit0=0  base0=LSB of Input  dbl_ovrd=off  block_type=slice
  slice35 : xbsIndex_r4/Slice  nbits=18  boolean_output=off  mode=Upper Bit Location + Width  bit1=-234  base1=MSB of Input  bit0=0  base0=LSB of Input  dbl_ovrd=off  block_type=slice
  slice36 : xbsIndex_r4/Slice  nbits=18  boolean_output=off  mode=Upper Bit Location + Width  bit1=-216  base1=MSB of Input  bit0=0  base0=LSB of Input  dbl_ovrd=off  block_type=slice
  slice37 : xbsIndex_r4/Slice  nbits=18  boolean_output=off  mode=Upper Bit Location + Width  bit1=-198  base1=MSB of Input  bit0=0  base0=LSB of Input  dbl_ovrd=off  block_type=slice
  slice38 : xbsIndex_r4/Slice  nbits=18  boolean_output=off  mode=Upper Bit Location + Width  bit1=-180  base1=MSB of Input  bit0=0  base0=LSB of Input  dbl_ovrd=off  block_type=slice
  slice39 : xbsIndex_r4/Slice  nbits=18  boolean_output=off  mode=Upper Bit Location + Width  bit1=-162  base1=MSB of Input  bit0=0  base0=LSB of Input  dbl_ovrd=off  block_type=slice
  slice4 : xbsIndex_r4/Slice  nbits=18  boolean_output=off  mode=Upper Bit Location + Width  bit1=-792  base1=MSB of Input  bit0=0  base0=LSB of Input  dbl_ovrd=off  block_type=slice
  slice40 : xbsIndex_r4/Slice  nbits=18  boolean_output=off  mode=Upper Bit Location + Width  bit1=-144  base1=MSB of Input  bit0=0  base0=LSB of Input  dbl_ovrd=off  block_type=slice
  slice41 : xbsIndex_r4/Slice  nbits=18  boolean_output=off  mode=Upper Bit Location + Width  bit1=-126  base1=MSB of Input  bit0=0  base0=LSB of Input  dbl_ovrd=off  block_type=slice
  slice42 : xbsIndex_r4/Slice  nbits=18  boolean_output=off  mode=Upper Bit Location + Width  bit1=-108  base1=MSB of Input  bit0=0  base0=LSB of Input  dbl_ovrd=off  block_type=slice
  slice43 : xbsIndex_r4/Slice  nbits=18  boolean_output=off  mode=Upper Bit Location + Width  bit1=-90  base1=MSB of Input  bit0=0  base0=LSB of Input  dbl_ovrd=off  block_type=slice
  slice44 : xbsIndex_r4/Slice  nbits=18  boolean_output=off  mode=Upper Bit Location + Width  bit1=-72  base1=MSB of Input  bit0=0  base0=LSB of Input  dbl_ovrd=off  block_type=slice
  slice45 : xbsIndex_r4/Slice  nbits=18  boolean_output=off  mode=Upper Bit Location + Width  bit1=-54  base1=MSB of Input  bit0=0  base0=LSB of Input  dbl_ovrd=off  block_type=slice
  slice46 : xbsIndex_r4/Slice  nbits=18  boolean_output=off  mode=Upper Bit Location + Width  bit1=-36  base1=MSB of Input  bit0=0  base0=LSB of Input  dbl_ovrd=off  block_type=slice
  slice47 : xbsIndex_r4/Slice  nbits=18  boolean_output=off  mode=Upper Bit Location + Width  bit1=-18  base1=MSB of Input  bit0=0  base0=LSB of Input  dbl_ovrd=off  block_type=slice
  slice48 : xbsIndex_r4/Slice  nbits=18  boolean_output=off  mode=Upper Bit Location + Width  bit1=0  base1=MSB of Input  bit0=0  base0=LSB of Input  dbl_ovrd=off  block_type=slice
  slice5 : xbsIndex_r4/Slice  nbits=18  boolean_output=off  mode=Upper Bit Location + Width  bit1=-774  base1=MSB of Input  bit0=0  base0=LSB of Input  dbl_ovrd=off  block_type=slice
  slice6 : xbsIndex_r4/Slice  nbits=18  boolean_output=off  mode=Upper Bit Location + Width  bit1=-756  base1=MSB of Input  bit0=0  base0=LSB of Input  dbl_ovrd=off  block_type=slice
  slice7 : xbsIndex_r4/Slice  nbits=18  boolean_output=off  mode=Upper Bit Location + Width  bit1=-738  base1=MSB of Input  bit0=0  base0=LSB of Input  dbl_ovrd=off  block_type=slice
  slice8 : xbsIndex_r4/Slice  nbits=18  boolean_output=off  mode=Upper Bit Location + Width  bit1=-720  base1=MSB of Input  bit0=0  base0=LSB of Input  dbl_ovrd=off  block_type=slice
  slice9 : xbsIndex_r4/Slice  nbits=18  boolean_output=off  mode=Upper Bit Location + Width  bit1=-702  base1=MSB of Input  bit0=0  base0=LSB of Input  dbl_ovrd=off  block_type=slice
  msb_out48 : Outport
  out47 : Outport  Port=2
  out46 : Outport  Port=3
  out45 : Outport  Port=4
  out44 : Outport  Port=5
  out43 : Outport  Port=6
  out42 : Outport  Port=7
  out41 : Outport  Port=8
  out40 : Outport  Port=9
  out39 : Outport  Port=10
  out38 : Outport  Port=11
  out37 : Outport  Port=12
  out36 : Outport  Port=13
  out35 : Outport  Port=14
  out34 : Outport  Port=15
  out33 : Outport  Port=16
  out32 : Outport  Port=17
  out31 : Outport  Port=18
  out30 : Outport  Port=19
  out29 : Outport  Port=20
  out28 : Outport  Port=21
  out27 : Outport  Port=22
  out26 : Outport  Port=23
  out25 : Outport  Port=24
  out24 : Outport  Port=25
  out23 : Outport  Port=26
  out22 : Outport  Port=27
  out21 : Outport  Port=28
  out20 : Outport  Port=29
  out19 : Outport  Port=30
  out18 : Outport  Port=31
  out17 : Outport  Port=32
  out16 : Outport  Port=33
  out15 : Outport  Port=34
  out14 : Outport  Port=35
  out13 : Outport  Port=36
  out12 : Outport  Port=37
  out11 : Outport  Port=38
  out10 : Outport  Port=39
  out9 : Outport  Port=40
  out8 : Outport  Port=41
  out7 : Outport  Port=42
  out6 : Outport  Port=43
  out5 : Outport  Port=44
  out4 : Outport  Port=45
  out3 : Outport  Port=46
  out2 : Outport  Port=47
  lsb_out1 : Outport  Port=48
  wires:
  bus_in/1 -> slice48/1, slice47/1, slice46/1, slice45/1, slice44/1, slice43/1, slice42/1, slice41/1, slice40/1, slice39/1, slice38/1, slice37/1, slice36/1, slice35/1, slice34/1, slice33/1, slice32/1, slice31/1, slice30/1, slice29/1, slice28/1, slice27/1, slice26/1, slice25/1, slice24/1, slice23/1, slice22/1, slice21/1, slice20/1, slice19/1, slice18/1, slice17/1, slice16/1, slice15/1, slice14/1, slice13/1, slice12/1, slice11/1, slice10/1, slice9/1, slice8/1, slice7/1, slice6/1, slice5/1, slice4/1, slice3/1, slice2/1, slice1/1
  slice48/1 -> reinterpret48/1
  reinterpret48/1 -> msb_out48/1
  slice47/1 -> reinterpret47/1
  reinterpret47/1 -> out47/1
  slice46/1 -> reinterpret46/1
  reinterpret46/1 -> out46/1
  slice45/1 -> reinterpret45/1
  reinterpret45/1 -> out45/1
  slice44/1 -> reinterpret44/1
  reinterpret44/1 -> out44/1
  slice43/1 -> reinterpret43/1
  reinterpret43/1 -> out43/1
  slice42/1 -> reinterpret42/1
  reinterpret42/1 -> out42/1
  slice41/1 -> reinterpret41/1
  reinterpret41/1 -> out41/1
  slice40/1 -> reinterpret40/1
  reinterpret40/1 -> out40/1
  slice39/1 -> reinterpret39/1
  reinterpret39/1 -> out39/1
  slice38/1 -> reinterpret38/1
  reinterpret38/1 -> out38/1
  slice37/1 -> reinterpret37/1
  reinterpret37/1 -> out37/1
  slice36/1 -> reinterpret36/1
  reinterpret36/1 -> out36/1
  slice35/1 -> reinterpret35/1
  reinterpret35/1 -> out35/1
  slice34/1 -> reinterpret34/1
  reinterpret34/1 -> out34/1
  slice33/1 -> reinterpret33/1
  reinterpret33/1 -> out33/1
  slice32/1 -> reinterpret32/1
  reinterpret32/1 -> out32/1
  slice31/1 -> reinterpret31/1
  reinterpret31/1 -> out31/1
  slice30/1 -> reinterpret30/1
  reinterpret30/1 -> out30/1
  slice29/1 -> reinterpret29/1
  reinterpret29/1 -> out29/1
  slice28/1 -> reinterpret28/1
  reinterpret28/1 -> out28/1
  slice27/1 -> reinterpret27/1
  reinterpret27/1 -> out27/1
  slice26/1 -> reinterpret26/1
  reinterpret26/1 -> out26/1
  slice25/1 -> reinterpret25/1
  reinterpret25/1 -> out25/1
  slice24/1 -> reinterpret24/1
  reinterpret24/1 -> out24/1
  slice23/1 -> reinterpret23/1
  reinterpret23/1 -> out23/1
  slice22/1 -> reinterpret22/1
  reinterpret22/1 -> out22/1
  slice21/1 -> reinterpret21/1
  reinterpret21/1 -> out21/1
  slice20/1 -> reinterpret20/1
  reinterpret20/1 -> out20/1
  slice19/1 -> reinterpret19/1
  reinterpret19/1 -> out19/1
  slice18/1 -> reinterpret18/1
  reinterpret18/1 -> out18/1
  slice17/1 -> reinterpret17/1
  reinterpret17/1 -> out17/1
  slice16/1 -> reinterpret16/1
  reinterpret16/1 -> out16/1
  slice15/1 -> reinterpret15/1
  reinterpret15/1 -> out15/1
  slice14/1 -> reinterpret14/1
  reinterpret14/1 -> out14/1
  slice13/1 -> reinterpret13/1
  reinterpret13/1 -> out13/1
  slice12/1 -> reinterpret12/1
  reinterpret12/1 -> out12/1
  slice11/1 -> reinterpret11/1
  reinterpret11/1 -> out11/1
  slice10/1 -> reinterpret10/1
  reinterpret10/1 -> out10/1
  slice9/1 -> reinterpret9/1
  reinterpret9/1 -> out9/1
  slice8/1 -> reinterpret8/1
  reinterpret8/1 -> out8/1
  slice7/1 -> reinterpret7/1
  reinterpret7/1 -> out7/1
  slice6/1 -> reinterpret6/1
  reinterpret6/1 -> out6/1
  slice5/1 -> reinterpret5/1
  reinterpret5/1 -> out5/1
  slice4/1 -> reinterpret4/1
  reinterpret4/1 -> out4/1
  slice3/1 -> reinterpret3/1
  reinterpret3/1 -> out3/1
  slice2/1 -> reinterpret2/1
  reinterpret2/1 -> out2/1
  slice1/1 -> reinterpret1/1
  reinterpret1/1 -> lsb_out1/1

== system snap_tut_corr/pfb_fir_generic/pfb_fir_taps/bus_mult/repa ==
  in : Inport
  bussify : Subsystem  AncestorBlock=casper_library_flow_control/bus_create  mask(bus_create){inputNum=1}
      mask prompts: inputNum "Number of inputs:"
      mask init:
      | bus_create_init(gcb,...
      |     'inputNum', inputNum);
  out : Outport
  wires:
  in/1 -> bussify/1(in1)
  bussify/1(bus_out) -> out/1

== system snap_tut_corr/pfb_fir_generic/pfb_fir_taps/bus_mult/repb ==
  in : Inport
  bussify : Subsystem  AncestorBlock=casper_library_flow_control/bus_create  mask(bus_create){inputNum=1}
      mask prompts: inputNum "Number of inputs:"
      mask init:
      | bus_create_init(gcb,...
      |     'inputNum', inputNum);
  out : Outport
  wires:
  in/1 -> bussify/1(in1)
  bussify/1(bus_out) -> out/1

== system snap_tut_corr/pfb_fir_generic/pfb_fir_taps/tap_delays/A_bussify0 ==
  in1 : Inport
  in2 : Inport  Port=2
  in3 : Inport  Port=3
  in4 : Inport  Port=4
  in5 : Inport  Port=5
  in6 : Inport  Port=6
  in7 : Inport  Port=7
  in8 : Inport  Port=8
  concatenate : xbsIndex_r4/Concat  num_inputs=8  dbl_ovrd=off  block_type=concat
  reinterpret{1..8} (8 alike) : xbsIndex_r4/Reinterpret  force_arith_type=on  arith_type=Unsigned  force_bin_pt=on  bin_pt=0  block_type=reinterpret
  bus_out : Outport
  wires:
  concatenate/1 -> bus_out/1
  in1/1 -> reinterpret1/1
  reinterpret1/1 -> concatenate/1
  in2/1 -> reinterpret2/1
  reinterpret2/1 -> concatenate/2
  in3/1 -> reinterpret3/1
  reinterpret3/1 -> concatenate/3
  in4/1 -> reinterpret4/1
  reinterpret4/1 -> concatenate/4
  in5/1 -> reinterpret5/1
  reinterpret5/1 -> concatenate/5
  in6/1 -> reinterpret6/1
  reinterpret6/1 -> concatenate/6
  in7/1 -> reinterpret7/1
  reinterpret7/1 -> concatenate/7
  in8/1 -> reinterpret8/1
  reinterpret8/1 -> concatenate/8

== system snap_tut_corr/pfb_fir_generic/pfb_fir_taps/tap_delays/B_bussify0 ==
  in1 : Inport
  in2 : Inport  Port=2
  in3 : Inport  Port=3
  in4 : Inport  Port=4
  in5 : Inport  Port=5
  in6 : Inport  Port=6
  in7 : Inport  Port=7
  in8 : Inport  Port=8
  concatenate : xbsIndex_r4/Concat  num_inputs=8  dbl_ovrd=off  block_type=concat
  reinterpret{1..8} (8 alike) : xbsIndex_r4/Reinterpret  force_arith_type=on  arith_type=Unsigned  force_bin_pt=on  bin_pt=0  block_type=reinterpret
  bus_out : Outport
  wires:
  concatenate/1 -> bus_out/1
  in1/1 -> reinterpret1/1
  reinterpret1/1 -> concatenate/1
  in2/1 -> reinterpret2/1
  reinterpret2/1 -> concatenate/2
  in3/1 -> reinterpret3/1
  reinterpret3/1 -> concatenate/3
  in4/1 -> reinterpret4/1
  reinterpret4/1 -> concatenate/4
  in5/1 -> reinterpret5/1
  reinterpret5/1 -> concatenate/5
  in6/1 -> reinterpret6/1
  reinterpret6/1 -> concatenate/6
  in7/1 -> reinterpret7/1
  reinterpret7/1 -> concatenate/7
  in8/1 -> reinterpret8/1
  reinterpret8/1 -> concatenate/8

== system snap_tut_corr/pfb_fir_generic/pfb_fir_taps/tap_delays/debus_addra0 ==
  bus_in : Inport
  reinterpret{1..8} (8 alike) : xbsIndex_r4/Reinterpret  force_arith_type=on  arith_type=Unsigned  force_bin_pt=on  bin_pt=0  block_type=reinterpret
  slice1 : xbsIndex_r4/Slice  nbits=9  boolean_output=off  mode=Upper Bit Location + Width  bit1=-63  base1=MSB of Input  bit0=0  base0=LSB of Input  dbl_ovrd=off  block_type=slice
  slice2 : xbsIndex_r4/Slice  nbits=9  boolean_output=off  mode=Upper Bit Location + Width  bit1=-54  base1=MSB of Input  bit0=0  base0=LSB of Input  dbl_ovrd=off  block_type=slice
  slice3 : xbsIndex_r4/Slice  nbits=9  boolean_output=off  mode=Upper Bit Location + Width  bit1=-45  base1=MSB of Input  bit0=0  base0=LSB of Input  dbl_ovrd=off  block_type=slice
  slice4 : xbsIndex_r4/Slice  nbits=9  boolean_output=off  mode=Upper Bit Location + Width  bit1=-36  base1=MSB of Input  bit0=0  base0=LSB of Input  dbl_ovrd=off  block_type=slice
  slice5 : xbsIndex_r4/Slice  nbits=9  boolean_output=off  mode=Upper Bit Location + Width  bit1=-27  base1=MSB of Input  bit0=0  base0=LSB of Input  dbl_ovrd=off  block_type=slice
  slice6 : xbsIndex_r4/Slice  nbits=9  boolean_output=off  mode=Upper Bit Location + Width  bit1=-18  base1=MSB of Input  bit0=0  base0=LSB of Input  dbl_ovrd=off  block_type=slice
  slice7 : xbsIndex_r4/Slice  nbits=9  boolean_output=off  mode=Upper Bit Location + Width  bit1=-9  base1=MSB of Input  bit0=0  base0=LSB of Input  dbl_ovrd=off  block_type=slice
  slice8 : xbsIndex_r4/Slice  nbits=9  boolean_output=off  mode=Upper Bit Location + Width  bit1=0  base1=MSB of Input  bit0=0  base0=LSB of Input  dbl_ovrd=off  block_type=slice
  msb_out8 : Outport
  out7 : Outport  Port=2
  out6 : Outport  Port=3
  out5 : Outport  Port=4
  out4 : Outport  Port=5
  out3 : Outport  Port=6
  out2 : Outport  Port=7
  lsb_out1 : Outport  Port=8
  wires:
  bus_in/1 -> slice8/1, slice7/1, slice6/1, slice5/1, slice4/1, slice3/1, slice2/1, slice1/1
  slice8/1 -> reinterpret8/1
  reinterpret8/1 -> msb_out8/1
  slice7/1 -> reinterpret7/1
  reinterpret7/1 -> out7/1
  slice6/1 -> reinterpret6/1
  reinterpret6/1 -> out6/1
  slice5/1 -> reinterpret5/1
  reinterpret5/1 -> out5/1
  slice4/1 -> reinterpret4/1
  reinterpret4/1 -> out4/1
  slice3/1 -> reinterpret3/1
  reinterpret3/1 -> out3/1
  slice2/1 -> reinterpret2/1
  reinterpret2/1 -> out2/1
  slice1/1 -> reinterpret1/1
  reinterpret1/1 -> lsb_out1/1

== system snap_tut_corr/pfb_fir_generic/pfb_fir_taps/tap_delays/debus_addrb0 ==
  bus_in : Inport
  reinterpret{1..8} (8 alike) : xbsIndex_r4/Reinterpret  force_arith_type=on  arith_type=Unsigned  force_bin_pt=on  bin_pt=0  block_type=reinterpret
  slice1 : xbsIndex_r4/Slice  nbits=9  boolean_output=off  mode=Upper Bit Location + Width  bit1=-63  base1=MSB of Input  bit0=0  base0=LSB of Input  dbl_ovrd=off  block_type=slice
  slice2 : xbsIndex_r4/Slice  nbits=9  boolean_output=off  mode=Upper Bit Location + Width  bit1=-54  base1=MSB of Input  bit0=0  base0=LSB of Input  dbl_ovrd=off  block_type=slice
  slice3 : xbsIndex_r4/Slice  nbits=9  boolean_output=off  mode=Upper Bit Location + Width  bit1=-45  base1=MSB of Input  bit0=0  base0=LSB of Input  dbl_ovrd=off  block_type=slice
  slice4 : xbsIndex_r4/Slice  nbits=9  boolean_output=off  mode=Upper Bit Location + Width  bit1=-36  base1=MSB of Input  bit0=0  base0=LSB of Input  dbl_ovrd=off  block_type=slice
  slice5 : xbsIndex_r4/Slice  nbits=9  boolean_output=off  mode=Upper Bit Location + Width  bit1=-27  base1=MSB of Input  bit0=0  base0=LSB of Input  dbl_ovrd=off  block_type=slice
  slice6 : xbsIndex_r4/Slice  nbits=9  boolean_output=off  mode=Upper Bit Location + Width  bit1=-18  base1=MSB of Input  bit0=0  base0=LSB of Input  dbl_ovrd=off  block_type=slice
  slice7 : xbsIndex_r4/Slice  nbits=9  boolean_output=off  mode=Upper Bit Location + Width  bit1=-9  base1=MSB of Input  bit0=0  base0=LSB of Input  dbl_ovrd=off  block_type=slice
  slice8 : xbsIndex_r4/Slice  nbits=9  boolean_output=off  mode=Upper Bit Location + Width  bit1=0  base1=MSB of Input  bit0=0  base0=LSB of Input  dbl_ovrd=off  block_type=slice
  msb_out8 : Outport
  out7 : Outport  Port=2
  out6 : Outport  Port=3
  out5 : Outport  Port=4
  out4 : Outport  Port=5
  out3 : Outport  Port=6
  out2 : Outport  Port=7
  lsb_out1 : Outport  Port=8
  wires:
  bus_in/1 -> slice8/1, slice7/1, slice6/1, slice5/1, slice4/1, slice3/1, slice2/1, slice1/1
  slice8/1 -> reinterpret8/1
  reinterpret8/1 -> msb_out8/1
  slice7/1 -> reinterpret7/1
  reinterpret7/1 -> out7/1
  slice6/1 -> reinterpret6/1
  reinterpret6/1 -> out6/1
  slice5/1 -> reinterpret5/1
  reinterpret5/1 -> out5/1
  slice4/1 -> reinterpret4/1
  reinterpret4/1 -> out4/1
  slice3/1 -> reinterpret3/1
  reinterpret3/1 -> out3/1
  slice2/1 -> reinterpret2/1
  reinterpret2/1 -> out2/1
  slice1/1 -> reinterpret1/1
  reinterpret1/1 -> lsb_out1/1
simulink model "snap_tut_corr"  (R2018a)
settings: Solver=VariableStepDiscrete  StartTime=0.0  StopTime=100  RelTol=1e-3
undefined symbols (not defined in the file): Area, behavioral, Behavioral, Bit, Both, BRAM, bram, c, core, d, Falling, getfield, hamming, hex2dec, led, Location, logic, Lower, Minimum_Area, out, quant0, quant1, quant2, reg, repmat, Rising, ROACH, ROACH2, SNAP, Speed, sync_in, Truncate, Unsigned, Upper, Width, Wrap, xc7k160t
libraries: xbsIndex_r4 x17901, casper_library_misc x29, xbsReplacements_r4 x20, casper_library_delays x14, xps_library x5
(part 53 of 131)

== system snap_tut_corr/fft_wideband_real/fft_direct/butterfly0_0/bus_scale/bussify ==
  in1 : Inport
  in2 : Inport  Port=2
  in3 : Inport  Port=3
  in4 : Inport  Port=4
  in5 : Inport  Port=5
  in6 : Inport  Port=6
  in7 : Inport  Port=7
  in8 : Inport  Port=8
  in9 : Inport  Port=9
  in10 : Inport  Port=10
  in11 : Inport  Port=11
  in12 : Inport  Port=12
  in13 : Inport  Port=13
  in14 : Inport  Port=14
  in15 : Inport  Port=15
  in16 : Inport  Port=16
  in17 : Inport  Port=17
  in18 : Inport  Port=18
  in19 : Inport  Port=19
  in20 : Inport  Port=20
  in21 : Inport  Port=21
  in22 : Inport  Port=22
  in23 : Inport  Port=23
  in24 : Inport  Port=24
  concatenate : xbsIndex_r4/Concat  num_inputs=24  dbl_ovrd=off  block_type=concat
  reinterpret{1..24} (24 alike) : xbsIndex_r4/Reinterpret  force_arith_type=on  arith_type=Unsigned  force_bin_pt=on  bin_pt=0  block_type=reinterpret
  bus_out : Outport
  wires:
  concatenate/1 -> bus_out/1
  in1/1 -> reinterpret1/1
  reinterpret1/1 -> concatenate/1
  in2/1 -> reinterpret2/1
  reinterpret2/1 -> concatenate/2
  in3/1 -> reinterpret3/1
  reinterpret3/1 -> concatenate/3
  in4/1 -> reinterpret4/1
  reinterpret4/1 -> concatenate/4
  in5/1 -> reinterpret5/1
  reinterpret5/1 -> concatenate/5
  in6/1 -> reinterpret6/1
  reinterpret6/1 -> concatenate/6
  in7/1 -> reinterpret7/1
  reinterpret7/1 -> concatenate/7
  in8/1 -> reinterpret8/1
  reinterpret8/1 -> concatenate/8
  in9/1 -> reinterpret9/1
  reinterpret9/1 -> concatenate/9
  in10/1 -> reinterpret10/1
  reinterpret10/1 -> concatenate/10
  in11/1 -> reinterpret11/1
  reinterpret11/1 -> concatenate/11
  in12/1 -> reinterpret12/1
  reinterpret12/1 -> concatenate/12
  in13/1 -> reinterpret13/1
  reinterpret13/1 -> concatenate/13
  in14/1 -> reinterpret14/1
  reinterpret14/1 -> concatenate/14
  in15/1 -> reinterpret15/1
  reinterpret15/1 -> concatenate/15
  in16/1 -> reinterpret16/1
  reinterpret16/1 -> concatenate/16
  in17/1 -> reinterpret17/1
  reinterpret17/1 -> concatenate/17
  in18/1 -> reinterpret18/1
  reinterpret18/1 -> concatenate/18
  in19/1 -> reinterpret19/1
  reinterpret19/1 -> concatenate/19
  in20/1 -> reinterpret20/1
  reinterpret20/1 -> concatenate/20
  in21/1 -> reinterpret21/1
  reinterpret21/1 -> concatenate/21
  in22/1 -> reinterpret22/1
  reinterpret22/1 -> concatenate/22
  in23/1 -> reinterpret23/1
  reinterpret23/1 -> concatenate/23
  in24/1 -> reinterpret24/1
  reinterpret24/1 -> concatenate/24

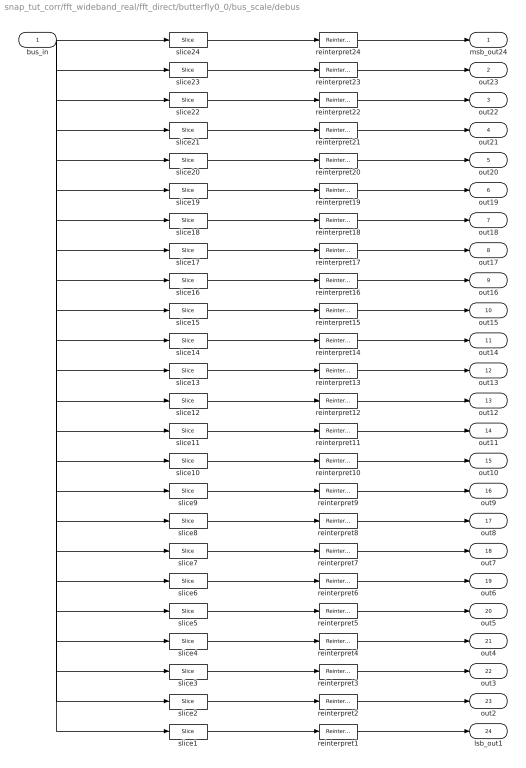
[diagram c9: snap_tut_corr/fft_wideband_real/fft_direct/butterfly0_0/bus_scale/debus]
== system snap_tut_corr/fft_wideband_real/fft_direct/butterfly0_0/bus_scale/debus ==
  bus_in : Inport
  reinterpret{1..24} (24 alike) : xbsIndex_r4/Reinterpret  force_arith_type=on  arith_type="Signed  (2's comp)"  force_bin_pt=on  bin_pt=17  block_type=reinterpret
  slice1 : xbsIndex_r4/Slice  nbits=20  boolean_output=off  mode=Upper Bit Location + Width  bit1=-460  base1=MSB of Input  bit0=0  base0=LSB of Input  dbl_ovrd=off  block_type=slice
  slice10 : xbsIndex_r4/Slice  nbits=20  boolean_output=off  mode=Upper Bit Location + Width  bit1=-280  base1=MSB of Input  bit0=0  base0=LSB of Input  dbl_ovrd=off  block_type=slice
  slice11 : xbsIndex_r4/Slice  nbits=20  boolean_output=off  mode=Upper Bit Location + Width  bit1=-260  base1=MSB of Input  bit0=0  base0=LSB of Input  dbl_ovrd=off  block_type=slice
  slice12 : xbsIndex_r4/Slice  nbits=20  boolean_output=off  mode=Upper Bit Location + Width  bit1=-240  base1=MSB of Input  bit0=0  base0=LSB of Input  dbl_ovrd=off  block_type=slice
  slice13 : xbsIndex_r4/Slice  nbits=20  boolean_output=off  mode=Upper Bit Location + Width  bit1=-220  base1=MSB of Input  bit0=0  base0=LSB of Input  dbl_ovrd=off  block_type=slice
  slice14 : xbsIndex_r4/Slice  nbits=20  boolean_output=off  mode=Upper Bit Location + Width  bit1=-200  base1=MSB of Input  bit0=0  base0=LSB of Input  dbl_ovrd=off  block_type=slice
  slice15 : xbsIndex_r4/Slice  nbits=20  boolean_output=off  mode=Upper Bit Location + Width  bit1=-180  base1=MSB of Input  bit0=0  base0=LSB of Input  dbl_ovrd=off  block_type=slice
  slice16 : xbsIndex_r4/Slice  nbits=20  boolean_output=off  mode=Upper Bit Location + Width  bit1=-160  base1=MSB of Input  bit0=0  base0=LSB of Input  dbl_ovrd=off  block_type=slice
  slice17 : xbsIndex_r4/Slice  nbits=20  boolean_output=off  mode=Upper Bit Location + Width  bit1=-140  base1=MSB of Input  bit0=0  base0=LSB of Input  dbl_ovrd=off  block_type=slice
  slice18 : xbsIndex_r4/Slice  nbits=20  boolean_output=off  mode=Upper Bit Location + Width  bit1=-120  base1=MSB of Input  bit0=0  base0=LSB of Input  dbl_ovrd=off  block_type=slice
  slice19 : xbsIndex_r4/Slice  nbits=20  boolean_output=off  mode=Upper Bit Location + Width  bit1=-100  base1=MSB of Input  bit0=0  base0=LSB of Input  dbl_ovrd=off  block_type=slice
  slice2 : xbsIndex_r4/Slice  nbits=20  boolean_output=off  mode=Upper Bit Location + Width  bit1=-440  base1=MSB of Input  bit0=0  base0=LSB of Input  dbl_ovrd=off  block_type=slice
  slice20 : xbsIndex_r4/Slice  nbits=20  boolean_output=off  mode=Upper Bit Location + Width  bit1=-80  base1=MSB of Input  bit0=0  base0=LSB of Input  dbl_ovrd=off  block_type=slice
  slice21 : xbsIndex_r4/Slice  nbits=20  boolean_output=off  mode=Upper Bit Location + Width  bit1=-60  base1=MSB of Input  bit0=0  base0=LSB of Input  dbl_ovrd=off  block_type=slice
  slice22 : xbsIndex_r4/Slice  nbits=20  boolean_output=off  mode=Upper Bit Location + Width  bit1=-40  base1=MSB of Input  bit0=0  base0=LSB of Input  dbl_ovrd=off  block_type=slice
  slice23 : xbsIndex_r4/Slice  nbits=20  boolean_output=off  mode=Upper Bit Location + Width  bit1=-20  base1=MSB of Input  bit0=0  base0=LSB of Input  dbl_ovrd=off  block_type=slice
  slice24 : xbsIndex_r4/Slice  nbits=20  boolean_output=off  mode=Upper Bit Location + Width  bit1=0  base1=MSB of Input  bit0=0  base0=LSB of Input  dbl_ovrd=off  block_type=slice
  slice3 : xbsIndex_r4/Slice  nbits=20  boolean_output=off  mode=Upper Bit Location + Width  bit1=-420  base1=MSB of Input  bit0=0  base0=LSB of Input  dbl_ovrd=off  block_type=slice
  slice4 : xbsIndex_r4/Slice  nbits=20  boolean_output=off  mode=Upper Bit Location + Width  bit1=-400  base1=MSB of Input  bit0=0  base0=LSB of Input  dbl_ovrd=off  block_type=slice
  slice5 : xbsIndex_r4/Slice  nbits=20  boolean_output=off  mode=Upper Bit Location + Width  bit1=-380  base1=MSB of Input  bit0=0  base0=LSB of Input  dbl_ovrd=off  block_type=slice
  slice6 : xbsIndex_r4/Slice  nbits=20  boolean_output=off  mode=Upper Bit Location + Width  bit1=-360  base1=MSB of Input  bit0=0  base0=LSB of Input  dbl_ovrd=off  block_type=slice
  slice7 : xbsIndex_r4/Slice  nbits=20  boolean_output=off  mode=Upper Bit Location + Width  bit1=-340  base1=MSB of Input  bit0=0  base0=LSB of Input  dbl_ovrd=off  block_type=slice
  slice8 : xbsIndex_r4/Slice  nbits=20  boolean_output=off  mode=Upper Bit Location + Width  bit1=-320  base1=MSB of Input  bit0=0  base0=LSB of Input  dbl_ovrd=off  block_type=slice
  slice9 : xbsIndex_r4/Slice  nbits=20  boolean_output=off  mode=Upper Bit Location + Width  bit1=-300  base1=MSB of Input  bit0=0  base0=LSB of Input  dbl_ovrd=off  block_type=slice
  msb_out24 : Outport
  out23 : Outport  Port=2
  out22 : Outport  Port=3
  out21 : Outport  Port=4
  out20 : Outport  Port=5
  out19 : Outport  Port=6
  out18 : Outport  Port=7
  out17 : Outport  Port=8
  out16 : Outport  Port=9
  out15 : Outport  Port=10
  out14 : Outport  Port=11
  out13 : Outport  Port=12
  out12 : Outport  Port=13
  out11 : Outport  Port=14
  out10 : Outport  Port=15
  out9 : Outport  Port=16
  out8 : Outport  Port=17
  out7 : Outport  Port=18
  out6 : Outport  Port=19
  out5 : Outport  Port=20
  out4 : Outport  Port=21
  out3 : Outport  Port=22
  out2 : Outport  Port=23
  lsb_out1 : Outport  Port=24
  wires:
  bus_in/1 -> slice24/1, slice23/1, slice22/1, slice21/1, slice20/1, slice19/1, slice18/1, slice17/1, slice16/1, slice15/1, slice14/1, slice13/1, slice12/1, slice11/1, slice10/1, slice9/1, slice8/1, slice7/1, slice6/1, slice5/1, slice4/1, slice3/1, slice2/1, slice1/1
  slice24/1 -> reinterpret24/1
  reinterpret24/1 -> msb_out24/1
  slice23/1 -> reinterpret23/1
  reinterpret23/1 -> out23/1
  slice22/1 -> reinterpret22/1
  reinterpret22/1 -> out22/1
  slice21/1 -> reinterpret21/1
  reinterpret21/1 -> out21/1
  slice20/1 -> reinterpret20/1
  reinterpret20/1 -> out20/1
  slice19/1 -> reinterpret19/1
  reinterpret19/1 -> out19/1
  slice18/1 -> reinterpret18/1
  reinterpret18/1 -> out18/1
  slice17/1 -> reinterpret17/1
  reinterpret17/1 -> out17/1
  slice16/1 -> reinterpret16/1
  reinterpret16/1 -> out16/1
  slice15/1 -> reinterpret15/1
  reinterpret15/1 -> out15/1
  slice14/1 -> reinterpret14/1
  reinterpret14/1 -> out14/1
  slice13/1 -> reinterpret13/1
  reinterpret13/1 -> out13/1
  slice12/1 -> reinterpret12/1
  reinterpret12/1 -> out12/1
  slice11/1 -> reinterpret11/1
  reinterpret11/1 -> out11/1
  slice10/1 -> reinterpret10/1
  reinterpret10/1 -> out10/1
  slice9/1 -> reinterpret9/1
  reinterpret9/1 -> out9/1
  slice8/1 -> reinterpret8/1
  reinterpret8/1 -> out8/1
  slice7/1 -> reinterpret7/1
  reinterpret7/1 -> out7/1
  slice6/1 -> reinterpret6/1
  reinterpret6/1 -> out6/1
  slice5/1 -> reinterpret5/1
  reinterpret5/1 -> out5/1
  slice4/1 -> reinterpret4/1
  reinterpret4/1 -> out4/1
  slice3/1 -> reinterpret3/1
  reinterpret3/1 -> out3/1
  slice2/1 -> reinterpret2/1
  reinterpret2/1 -> out2/1
  slice1/1 -> reinterpret1/1
  reinterpret1/1 -> lsb_out1/1

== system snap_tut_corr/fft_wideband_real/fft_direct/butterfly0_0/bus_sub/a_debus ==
  bus_in : Inport
  reinterpret{1..12} (12 alike) : xbsIndex_r4/Reinterpret  force_arith_type=on  arith_type="Signed  (2's comp)"  force_bin_pt=on  bin_pt=17  block_type=reinterpret
  slice1 : xbsIndex_r4/Slice  nbits=18  boolean_output=off  mode=Upper Bit Location + Width  bit1=-198  base1=MSB of Input  bit0=0  base0=LSB of Input  dbl_ovrd=off  block_type=slice
  slice10 : xbsIndex_r4/Slice  nbits=18  boolean_output=off  mode=Upper Bit Location + Width  bit1=-36  base1=MSB of Input  bit0=0  base0=LSB of Input  dbl_ovrd=off  block_type=slice
  slice11 : xbsIndex_r4/Slice  nbits=18  boolean_output=off  mode=Upper Bit Location + Width  bit1=-18  base1=MSB of Input  bit0=0  base0=LSB of Input  dbl_ovrd=off  block_type=slice
  slice12 : xbsIndex_r4/Slice  nbits=18  boolean_output=off  mode=Upper Bit Location + Width  bit1=0  base1=MSB of Input  bit0=0  base0=LSB of Input  dbl_ovrd=off  block_type=slice
  slice2 : xbsIndex_r4/Slice  nbits=18  boolean_output=off  mode=Upper Bit Location + Width  bit1=-180  base1=MSB of Input  bit0=0  base0=LSB of Input  dbl_ovrd=off  block_type=slice
  slice3 : xbsIndex_r4/Slice  nbits=18  boolean_output=off  mode=Upper Bit Location + Width  bit1=-162  base1=MSB of Input  bit0=0  base0=LSB of Input  dbl_ovrd=off  block_type=slice
  slice4 : xbsIndex_r4/Slice  nbits=18  boolean_output=off  mode=Upper Bit Location + Width  bit1=-144  base1=MSB of Input  bit0=0  base0=LSB of Input  dbl_ovrd=off  block_type=slice
  slice5 : xbsIndex_r4/Slice  nbits=18  boolean_output=off  mode=Upper Bit Location + Width  bit1=-126  base1=MSB of Input  bit0=0  base0=LSB of Input  dbl_ovrd=off  block_type=slice
  slice6 : xbsIndex_r4/Slice  nbits=18  boolean_output=off  mode=Upper Bit Location + Width  bit1=-108  base1=MSB of Input  bit0=0  base0=LSB of Input  dbl_ovrd=off  block_type=slice
  slice7 : xbsIndex_r4/Slice  nbits=18  boolean_output=off  mode=Upper Bit Location + Width  bit1=-90  base1=MSB of Input  bit0=0  base0=LSB of Input  dbl_ovrd=off  block_type=slice
  slice8 : xbsIndex_r4/Slice  nbits=18  boolean_output=off  mode=Upper Bit Location + Width  bit1=-72  base1=MSB of Input  bit0=0  base0=LSB of Input  dbl_ovrd=off  block_type=slice
  slice9 : xbsIndex_r4/Slice  nbits=18  boolean_output=off  mode=Upper Bit Location + Width  bit1=-54  base1=MSB of Input  bit0=0  base0=LSB of Input  dbl_ovrd=off  block_type=slice
  msb_out12 : Outport
  out11 : Outport  Port=2
  out10 : Outport  Port=3
  out9 : Outport  Port=4
  out8 : Outport  Port=5
  out7 : Outport  Port=6
  out6 : Outport  Port=7
  out5 : Outport  Port=8
  out4 : Outport  Port=9
  out3 : Outport  Port=10
  out2 : Outport  Port=11
  lsb_out1 : Outport  Port=12
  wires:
  bus_in/1 -> slice12/1, slice11/1, slice10/1, slice9/1, slice8/1, slice7/1, slice6/1, slice5/1, slice4/1, slice3/1, slice2/1, slice1/1
  slice12/1 -> reinterpret12/1
  reinterpret12/1 -> msb_out12/1
  slice11/1 -> reinterpret11/1
  reinterpret11/1 -> out11/1
  slice10/1 -> reinterpret10/1
  reinterpret10/1 -> out10/1
  slice9/1 -> reinterpret9/1
  reinterpret9/1 -> out9/1
  slice8/1 -> reinterpret8/1
  reinterpret8/1 -> out8/1
  slice7/1 -> reinterpret7/1
  reinterpret7/1 -> out7/1
  slice6/1 -> reinterpret6/1
  reinterpret6/1 -> out6/1
  slice5/1 -> reinterpret5/1
  reinterpret5/1 -> out5/1
  slice4/1 -> reinterpret4/1
  reinterpret4/1 -> out4/1
  slice3/1 -> reinterpret3/1
  reinterpret3/1 -> out3/1
  slice2/1 -> reinterpret2/1
  reinterpret2/1 -> out2/1
  slice1/1 -> reinterpret1/1
  reinterpret1/1 -> lsb_out1/1

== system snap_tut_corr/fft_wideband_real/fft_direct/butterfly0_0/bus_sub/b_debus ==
  bus_in : Inport
  reinterpret{1..12} (12 alike) : xbsIndex_r4/Reinterpret  force_arith_type=on  arith_type="Signed  (2's comp)"  force_bin_pt=on  bin_pt=17  block_type=reinterpret
  slice1 : xbsIndex_r4/Slice  nbits=19  boolean_output=off  mode=Upper Bit Location + Width  bit1=-209  base1=MSB of Input  bit0=0  base0=LSB of Input  dbl_ovrd=off  block_type=slice
  slice10 : xbsIndex_r4/Slice  nbits=19  boolean_output=off  mode=Upper Bit Location + Width  bit1=-38  base1=MSB of Input  bit0=0  base0=LSB of Input  dbl_ovrd=off  block_type=slice
  slice11 : xbsIndex_r4/Slice  nbits=19  boolean_output=off  mode=Upper Bit Location + Width  bit1=-19  base1=MSB of Input  bit0=0  base0=LSB of Input  dbl_ovrd=off  block_type=slice
  slice12 : xbsIndex_r4/Slice  nbits=19  boolean_output=off  mode=Upper Bit Location + Width  bit1=0  base1=MSB of Input  bit0=0  base0=LSB of Input  dbl_ovrd=off  block_type=slice
  slice2 : xbsIndex_r4/Slice  nbits=19  boolean_output=off  mode=Upper Bit Location + Width  bit1=-190  base1=MSB of Input  bit0=0  base0=LSB of Input  dbl_ovrd=off  block_type=slice
  slice3 : xbsIndex_r4/Slice  nbits=19  boolean_output=off  mode=Upper Bit Location + Width  bit1=-171  base1=MSB of Input  bit0=0  base0=LSB of Input  dbl_ovrd=off  block_type=slice
  slice4 : xbsIndex_r4/Slice  nbits=19  boolean_output=off  mode=Upper Bit Location + Width  bit1=-152  base1=MSB of Input  bit0=0  base0=LSB of Input  dbl_ovrd=off  block_type=slice
  slice5 : xbsIndex_r4/Slice  nbits=19  boolean_output=off  mode=Upper Bit Location + Width  bit1=-133  base1=MSB of Input  bit0=0  base0=LSB of Input  dbl_ovrd=off  block_type=slice
  slice6 : xbsIndex_r4/Slice  nbits=19  boolean_output=off  mode=Upper Bit Location + Width  bit1=-114  base1=MSB of Input  bit0=0  base0=LSB of Input  dbl_ovrd=off  block_type=slice
  slice7 : xbsIndex_r4/Slice  nbits=19  boolean_output=off  mode=Upper Bit Location + Width  bit1=-95  base1=MSB of Input  bit0=0  base0=LSB of Input  dbl_ovrd=off  block_type=slice
  slice8 : xbsIndex_r4/Slice  nbits=19  boolean_output=off  mode=Upper Bit Location + Width  bit1=-76  base1=MSB of Input  bit0=0  base0=LSB of Input  dbl_ovrd=off  block_type=slice
  slice9 : xbsIndex_r4/Slice  nbits=19  boolean_output=off  mode=Upper Bit Location + Width  bit1=-57  base1=MSB of Input  bit0=0  base0=LSB of Input  dbl_ovrd=off  block_type=slice
  msb_out12 : Outport
  out11 : Outport  Port=2
  out10 : Outport  Port=3
  out9 : Outport  Port=4
  out8 : Outport  Port=5
  out7 : Outport  Port=6
  out6 : Outport  Port=7
  out5 : Outport  Port=8
  out4 : Outport  Port=9
  out3 : Outport  Port=10
  out2 : Outport  Port=11
  lsb_out1 : Outport  Port=12
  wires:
  bus_in/1 -> slice12/1, slice11/1, slice10/1, slice9/1, slice8/1, slice7/1, slice6/1, slice5/1, slice4/1, slice3/1, slice2/1, slice1/1
  slice12/1 -> reinterpret12/1
  reinterpret12/1 -> msb_out12/1
  slice11/1 -> reinterpret11/1
  reinterpret11/1 -> out11/1
  slice10/1 -> reinterpret10/1
  reinterpret10/1 -> out10/1
  slice9/1 -> reinterpret9/1
  reinterpret9/1 -> out9/1
  slice8/1 -> reinterpret8/1
  reinterpret8/1 -> out8/1
  slice7/1 -> reinterpret7/1
  reinterpret7/1 -> out7/1
  slice6/1 -> reinterpret6/1
  reinterpret6/1 -> out6/1
  slice5/1 -> reinterpret5/1
  reinterpret5/1 -> out5/1
  slice4/1 -> reinterpret4/1
  reinterpret4/1 -> out4/1
  slice3/1 -> reinterpret3/1
  reinterpret3/1 -> out3/1
  slice2/1 -> reinterpret2/1
  reinterpret2/1 -> out2/1
  slice1/1 -> reinterpret1/1
  reinterpret1/1 -> lsb_out1/1

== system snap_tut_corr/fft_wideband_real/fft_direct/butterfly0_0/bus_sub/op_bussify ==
  in1 : Inport
  in2 : Inport  Port=2
  in3 : Inport  Port=3
  in4 : Inport  Port=4
  in5 : Inport  Port=5
  in6 : Inport  Port=6
  in7 : Inport  Port=7
  in8 : Inport  Port=8
  in9 : Inport  Port=9
  in10 : Inport  Port=10
  in11 : Inport  Port=11
  in12 : Inport  Port=12
  concatenate : xbsIndex_r4/Concat  num_inputs=12  dbl_ovrd=off  block_type=concat
  reinterpret{1..12} (12 alike) : xbsIndex_r4/Reinterpret  force_arith_type=on  arith_type=Unsigned  force_bin_pt=on  bin_pt=0  block_type=reinterpret
  bus_out : Outport
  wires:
  concatenate/1 -> bus_out/1
  in1/1 -> reinterpret1/1
  reinterpret1/1 -> concatenate/1
  in2/1 -> reinterpret2/1
  reinterpret2/1 -> concatenate/2
  in3/1 -> reinterpret3/1
  reinterpret3/1 -> concatenate/3
  in4/1 -> reinterpret4/1
  reinterpret4/1 -> concatenate/4
  in5/1 -> reinterpret5/1
  reinterpret5/1 -> concatenate/5
  in6/1 -> reinterpret6/1
  reinterpret6/1 -> concatenate/6
  in7/1 -> reinterpret7/1
  reinterpret7/1 -> concatenate/7
  in8/1 -> reinterpret8/1
  reinterpret8/1 -> concatenate/8
  in9/1 -> reinterpret9/1
  reinterpret9/1 -> concatenate/9
  in10/1 -> reinterpret10/1
  reinterpret10/1 -> concatenate/10
  in11/1 -> reinterpret11/1
  reinterpret11/1 -> concatenate/11
  in12/1 -> reinterpret12/1
  reinterpret12/1 -> concatenate/12

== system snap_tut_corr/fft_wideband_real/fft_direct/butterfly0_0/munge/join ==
  in1 : Inport
  in2 : Inport  Port=2
  in3 : Inport  Port=3
  in4 : Inport  Port=4
  in5 : Inport  Port=5
  in6 : Inport  Port=6
  in7 : Inport  Port=7
  in8 : Inport  Port=8
  in9 : Inport  Port=9
  in10 : Inport  Port=10
  in11 : Inport  Port=11
  in12 : Inport  Port=12
  concatenate : xbsIndex_r4/Concat  num_inputs=12  dbl_ovrd=off  block_type=concat
  reinterpret{1..12} (12 alike) : xbsIndex_r4/Reinterpret  force_arith_type=on  arith_type=Unsigned  force_bin_pt=on  bin_pt=0  block_type=reinterpret
  bus_out : Outport
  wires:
  concatenate/1 -> bus_out/1
  in1/1 -> reinterpret1/1
  reinterpret1/1 -> concatenate/1
  in2/1 -> reinterpret2/1
  reinterpret2/1 -> concatenate/2
  in3/1 -> reinterpret3/1
  reinterpret3/1 -> concatenate/3
  in4/1 -> reinterpret4/1
  reinterpret4/1 -> concatenate/4
  in5/1 -> reinterpret5/1
  reinterpret5/1 -> concatenate/5
  in6/1 -> reinterpret6/1
  reinterpret6/1 -> concatenate/6
  in7/1 -> reinterpret7/1
  reinterpret7/1 -> concatenate/7
  in8/1 -> reinterpret8/1
  reinterpret8/1 -> concatenate/8
  in9/1 -> reinterpret9/1
  reinterpret9/1 -> concatenate/9
  in10/1 -> reinterpret10/1
  reinterpret10/1 -> concatenate/10
  in11/1 -> reinterpret11/1
  reinterpret11/1 -> concatenate/11
  in12/1 -> reinterpret12/1
  reinterpret12/1 -> concatenate/12

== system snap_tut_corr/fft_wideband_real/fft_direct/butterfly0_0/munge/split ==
  bus_in : Inport
  reinterpret{1..12} (12 alike) : xbsIndex_r4/Reinterpret  force_arith_type=on  arith_type=Unsigned  force_bin_pt=on  bin_pt=0  block_type=reinterpret
  slice1 : xbsIndex_r4/Slice  nbits=2  boolean_output=off  mode=Upper Bit Location + Width  bit1=-22  base1=MSB of Input  bit0=0  base0=LSB of Input  dbl_ovrd=off  block_type=slice
  slice10 : xbsIndex_r4/Slice  nbits=2  boolean_output=off  mode=Upper Bit Location + Width  bit1=-4  base1=MSB of Input  bit0=0  base0=LSB of Input  dbl_ovrd=off  block_type=slice
  slice11 : xbsIndex_r4/Slice  nbits=2  boolean_output=off  mode=Upper Bit Location + Width  bit1=-2  base1=MSB of Input  bit0=0  base0=LSB of Input  dbl_ovrd=off  block_type=slice
  slice12 : xbsIndex_r4/Slice  nbits=2  boolean_output=off  mode=Upper Bit Location + Width  bit1=0  base1=MSB of Input  bit0=0  base0=LSB of Input  dbl_ovrd=off  block_type=slice
  slice2 : xbsIndex_r4/Slice  nbits=2  boolean_output=off  mode=Upper Bit Location + Width  bit1=-20  base1=MSB of Input  bit0=0  base0=LSB of Input  dbl_ovrd=off  block_type=slice
  slice3 : xbsIndex_r4/Slice  nbits=2  boolean_output=off  mode=Upper Bit Location + Width  bit1=-18  base1=MSB of Input  bit0=0  base0=LSB of Input  dbl_ovrd=off  block_type=slice
  slice4 : xbsIndex_r4/Slice  nbits=2  boolean_output=off  mode=Upper Bit Location + Width  bit1=-16  base1=MSB of Input  bit0=0  base0=LSB of Input  dbl_ovrd=off  block_type=slice
  slice5 : xbsIndex_r4/Slice  nbits=2  boolean_output=off  mode=Upper Bit Location + Width  bit1=-14  base1=MSB of Input  bit0=0  base0=LSB of Input  dbl_ovrd=off  block_type=slice
  slice6 : xbsIndex_r4/Slice  nbits=2  boolean_output=off  mode=Upper Bit Location + Width  bit1=-12  base1=MSB of Input  bit0=0  base0=LSB of Input  dbl_ovrd=off  block_type=slice
  slice7 : xbsIndex_r4/Slice  nbits=2  boolean_output=off  mode=Upper Bit Location + Width  bit1=-10  base1=MSB of Input  bit0=0  base0=LSB of Input  dbl_ovrd=off  block_type=slice
  slice8 : xbsIndex_r4/Slice  nbits=2  boolean_output=off  mode=Upper Bit Location + Width  bit1=-8  base1=MSB of Input  bit0=0  base0=LSB of Input  dbl_ovrd=off  block_type=slice
  slice9 : xbsIndex_r4/Slice  nbits=2  boolean_output=off  mode=Upper Bit Location + Width  bit1=-6  base1=MSB of Input  bit0=0  base0=LSB of Input  dbl_ovrd=off  block_type=slice
  msb_out12 : Outport
  out11 : Outport  Port=2
  out10 : Outport  Port=3
  out9 : Outport  Port=4
  out8 : Outport  Port=5
  out7 : Outport  Port=6
  out6 : Outport  Port=7
  out5 : Outport  Port=8
  out4 : Outport  Port=9
  out3 : Outport  Port=10
  out2 : Outport  Port=11
  lsb_out1 : Outport  Port=12
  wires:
  bus_in/1 -> slice12/1, slice11/1, slice10/1, slice9/1, slice8/1, slice7/1, slice6/1, slice5/1, slice4/1, slice3/1, slice2/1, slice1/1
  slice12/1 -> reinterpret12/1
  reinterpret12/1 -> msb_out12/1
  slice11/1 -> reinterpret11/1
  reinterpret11/1 -> out11/1
  slice10/1 -> reinterpret10/1
  reinterpret10/1 -> out10/1
  slice9/1 -> reinterpret9/1
  reinterpret9/1 -> out9/1
  slice8/1 -> reinterpret8/1
  reinterpret8/1 -> out8/1
  slice7/1 -> reinterpret7/1
  reinterpret7/1 -> out7/1
  slice6/1 -> reinterpret6/1
  reinterpret6/1 -> out6/1
  slice5/1 -> reinterpret5/1
  reinterpret5/1 -> out5/1
  slice4/1 -> reinterpret4/1
  reinterpret4/1 -> out4/1
  slice3/1 -> reinterpret3/1
  reinterpret3/1 -> out3/1
  slice2/1 -> reinterpret2/1
  reinterpret2/1 -> out2/1
  slice1/1 -> reinterpret1/1
  reinterpret1/1 -> lsb_out1/1

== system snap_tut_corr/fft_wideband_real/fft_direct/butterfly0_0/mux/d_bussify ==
  in1 : Inport
  in2 : Inport  Port=2
  in3 : Inport  Port=3
  in4 : Inport  Port=4
  in5 : Inport  Port=5
  in6 : Inport  Port=6
  in7 : Inport  Port=7
  in8 : Inport  Port=8
  in9 : Inport  Port=9
  in10 : Inport  Port=10
  in11 : Inport  Port=11
  in12 : Inport  Port=12
  in13 : Inport  Port=13
  in14 : Inport  Port=14
  in15 : Inport  Port=15
  in16 : Inport  Port=16
  in17 : Inport  Port=17
  in18 : Inport  Port=18
  in19 : Inport  Port=19
  in20 : Inport  Port=20
  in21 : Inport  Port=21
  in22 : Inport  Port=22
  in23 : Inport  Port=23
  in24 : Inport  Port=24
  concatenate : xbsIndex_r4/Concat  num_inputs=24  dbl_ovrd=off  block_type=concat
  reinterpret{1..24} (24 alike) : xbsIndex_r4/Reinterpret  force_arith_type=on  arith_type=Unsigned  force_bin_pt=on  bin_pt=0  block_type=reinterpret
  bus_out : Outport
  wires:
  concatenate/1 -> bus_out/1
  in1/1 -> reinterpret1/1
  reinterpret1/1 -> concatenate/1
  in2/1 -> reinterpret2/1
  reinterpret2/1 -> concatenate/2
  in3/1 -> reinterpret3/1
  reinterpret3/1 -> concatenate/3
  in4/1 -> reinterpret4/1
  reinterpret4/1 -> concatenate/4
  in5/1 -> reinterpret5/1
  reinterpret5/1 -> concatenate/5
  in6/1 -> reinterpret6/1
  reinterpret6/1 -> concatenate/6
  in7/1 -> reinterpret7/1
  reinterpret7/1 -> concatenate/7
  in8/1 -> reinterpret8/1
  reinterpret8/1 -> concatenate/8
  in9/1 -> reinterpret9/1
  reinterpret9/1 -> concatenate/9
  in10/1 -> reinterpret10/1
  reinterpret10/1 -> concatenate/10
  in11/1 -> reinterpret11/1
  reinterpret11/1 -> concatenate/11
  in12/1 -> reinterpret12/1
  reinterpret12/1 -> concatenate/12
  in13/1 -> reinterpret13/1
  reinterpret13/1 -> concatenate/13
  in14/1 -> reinterpret14/1
  reinterpret14/1 -> concatenate/14
  in15/1 -> reinterpret15/1
  reinterpret15/1 -> concatenate/15
  in16/1 -> reinterpret16/1
  reinterpret16/1 -> concatenate/16
  in17/1 -> reinterpret17/1
  reinterpret17/1 -> concatenate/17
  in18/1 -> reinterpret18/1
  reinterpret18/1 -> concatenate/18
  in19/1 -> reinterpret19/1
  reinterpret19/1 -> concatenate/19
  in20/1 -> reinterpret20/1
  reinterpret20/1 -> concatenate/20
  in21/1 -> reinterpret21/1
  reinterpret21/1 -> concatenate/21
  in22/1 -> reinterpret22/1
  reinterpret22/1 -> concatenate/22
  in23/1 -> reinterpret23/1
  reinterpret23/1 -> concatenate/23
  in24/1 -> reinterpret24/1
  reinterpret24/1 -> concatenate/24

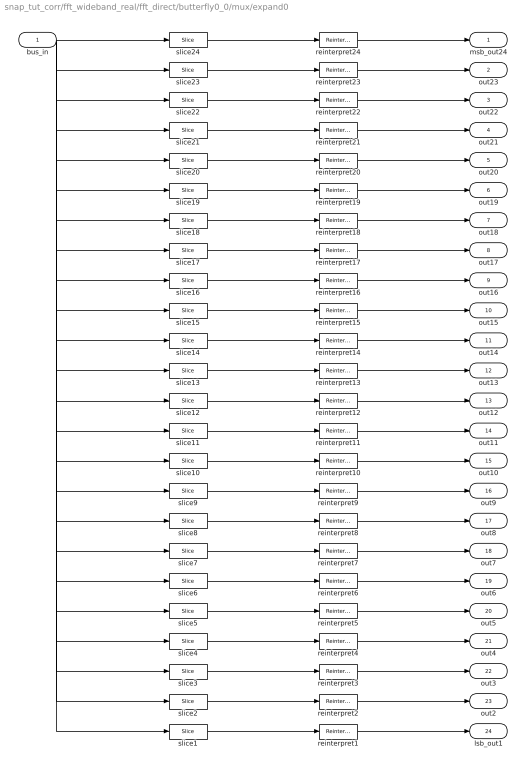
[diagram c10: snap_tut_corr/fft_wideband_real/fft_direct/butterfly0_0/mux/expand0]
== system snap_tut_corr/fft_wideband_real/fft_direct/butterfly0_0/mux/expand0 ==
  bus_in : Inport
  reinterpret{1..24} (24 alike) : xbsIndex_r4/Reinterpret  force_arith_type=on  arith_type=Unsigned  force_bin_pt=on  bin_pt=0  block_type=reinterpret
  slice1 : xbsIndex_r4/Slice  nbits=21  boolean_output=off  mode=Upper Bit Location + Width  bit1=-483  base1=MSB of Input  bit0=0  base0=LSB of Input  dbl_ovrd=off  block_type=slice
  slice10 : xbsIndex_r4/Slice  nbits=21  boolean_output=off  mode=Upper Bit Location + Width  bit1=-294  base1=MSB of Input  bit0=0  base0=LSB of Input  dbl_ovrd=off  block_type=slice
  slice11 : xbsIndex_r4/Slice  nbits=21  boolean_output=off  mode=Upper Bit Location + Width  bit1=-273  base1=MSB of Input  bit0=0  base0=LSB of Input  dbl_ovrd=off  block_type=slice
  slice12 : xbsIndex_r4/Slice  nbits=21  boolean_output=off  mode=Upper Bit Location + Width  bit1=-252  base1=MSB of Input  bit0=0  base0=LSB of Input  dbl_ovrd=off  block_type=slice
  slice13 : xbsIndex_r4/Slice  nbits=21  boolean_output=off  mode=Upper Bit Location + Width  bit1=-231  base1=MSB of Input  bit0=0  base0=LSB of Input  dbl_ovrd=off  block_type=slice
  slice14 : xbsIndex_r4/Slice  nbits=21  boolean_output=off  mode=Upper Bit Location + Width  bit1=-210  base1=MSB of Input  bit0=0  base0=LSB of Input  dbl_ovrd=off  block_type=slice
  slice15 : xbsIndex_r4/Slice  nbits=21  boolean_output=off  mode=Upper Bit Location + Width  bit1=-189  base1=MSB of Input  bit0=0  base0=LSB of Input  dbl_ovrd=off  block_type=slice
  slice16 : xbsIndex_r4/Slice  nbits=21  boolean_output=off  mode=Upper Bit Location + Width  bit1=-168  base1=MSB of Input  bit0=0  base0=LSB of Input  dbl_ovrd=off  block_type=slice
  slice17 : xbsIndex_r4/Slice  nbits=21  boolean_output=off  mode=Upper Bit Location + Width  bit1=-147  base1=MSB of Input  bit0=0  base0=LSB of Input  dbl_ovrd=off  block_type=slice
  slice18 : xbsIndex_r4/Slice  nbits=21  boolean_output=off  mode=Upper Bit Location + Width  bit1=-126  base1=MSB of Input  bit0=0  base0=LSB of Input  dbl_ovrd=off  block_type=slice
  slice19 : xbsIndex_r4/Slice  nbits=21  boolean_output=off  mode=Upper Bit Location + Width  bit1=-105  base1=MSB of Input  bit0=0  base0=LSB of Input  dbl_ovrd=off  block_type=slice
  slice2 : xbsIndex_r4/Slice  nbits=21  boolean_output=off  mode=Upper Bit Location + Width  bit1=-462  base1=MSB of Input  bit0=0  base0=LSB of Input  dbl_ovrd=off  block_type=slice
  slice20 : xbsIndex_r4/Slice  nbits=21  boolean_output=off  mode=Upper Bit Location + Width  bit1=-84  base1=MSB of Input  bit0=0  base0=LSB of Input  dbl_ovrd=off  block_type=slice
  slice21 : xbsIndex_r4/Slice  nbits=21  boolean_output=off  mode=Upper Bit Location + Width  bit1=-63  base1=MSB of Input  bit0=0  base0=LSB of Input  dbl_ovrd=off  block_type=slice
  slice22 : xbsIndex_r4/Slice  nbits=21  boolean_output=off  mode=Upper Bit Location + Width  bit1=-42  base1=MSB of Input  bit0=0  base0=LSB of Input  dbl_ovrd=off  block_type=slice
  slice23 : xbsIndex_r4/Slice  nbits=21  boolean_output=off  mode=Upper Bit Location + Width  bit1=-21  base1=MSB of Input  bit0=0  base0=LSB of Input  dbl_ovrd=off  block_type=slice
  slice24 : xbsIndex_r4/Slice  nbits=21  boolean_output=off  mode=Upper Bit Location + Width  bit1=0  base1=MSB of Input  bit0=0  base0=LSB of Input  dbl_ovrd=off  block_type=slice
  slice3 : xbsIndex_r4/Slice  nbits=21  boolean_output=off  mode=Upper Bit Location + Width  bit1=-441  base1=MSB of Input  bit0=0  base0=LSB of Input  dbl_ovrd=off  block_type=slice
  slice4 : xbsIndex_r4/Slice  nbits=21  boolean_output=off  mode=Upper Bit Location + Width  bit1=-420  base1=MSB of Input  bit0=0  base0=LSB of Input  dbl_ovrd=off  block_type=slice
  slice5 : xbsIndex_r4/Slice  nbits=21  boolean_output=off  mode=Upper Bit Location + Width  bit1=-399  base1=MSB of Input  bit0=0  base0=LSB of Input  dbl_ovrd=off  block_type=slice
  slice6 : xbsIndex_r4/Slice  nbits=21  boolean_output=off  mode=Upper Bit Location + Width  bit1=-378  base1=MSB of Input  bit0=0  base0=LSB of Input  dbl_ovrd=off  block_type=slice
  slice7 : xbsIndex_r4/Slice  nbits=21  boolean_output=off  mode=Upper Bit Location + Width  bit1=-357  base1=MSB of Input  bit0=0  base0=LSB of Input  dbl_ovrd=off  block_type=slice
  slice8 : xbsIndex_r4/Slice  nbits=21  boolean_output=off  mode=Upper Bit Location + Width  bit1=-336  base1=MSB of Input  bit0=0  base0=LSB of Input  dbl_ovrd=off  block_type=slice
  slice9 : xbsIndex_r4/Slice  nbits=21  boolean_output=off  mode=Upper Bit Location + Width  bit1=-315  base1=MSB of Input  bit0=0  base0=LSB of Input  dbl_ovrd=off  block_type=slice
  msb_out24 : Outport
  out23 : Outport  Port=2
  out22 : Outport  Port=3
  out21 : Outport  Port=4
  out20 : Outport  Port=5
  out19 : Outport  Port=6
  out18 : Outport  Port=7
  out17 : Outport  Port=8
  out16 : Outport  Port=9
  out15 : Outport  Port=10
  out14 : Outport  Port=11
  out13 : Outport  Port=12
  out12 : Outport  Port=13
  out11 : Outport  Port=14
  out10 : Outport  Port=15
  out9 : Outport  Port=16
  out8 : Outport  Port=17
  out7 : Outport  Port=18
  out6 : Outport  Port=19
  out5 : Outport  Port=20
  out4 : Outport  Port=21
  out3 : Outport  Port=22
  out2 : Outport  Port=23
  lsb_out1 : Outport  Port=24
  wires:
  bus_in/1 -> slice24/1, slice23/1, slice22/1, slice21/1, slice20/1, slice19/1, slice18/1, slice17/1, slice16/1, slice15/1, slice14/1, slice13/1, slice12/1, slice11/1, slice10/1, slice9/1, slice8/1, slice7/1, slice6/1, slice5/1, slice4/1, slice3/1, slice2/1, slice1/1
  slice24/1 -> reinterpret24/1
  reinterpret24/1 -> msb_out24/1
  slice23/1 -> reinterpret23/1
  reinterpret23/1 -> out23/1
  slice22/1 -> reinterpret22/1
  reinterpret22/1 -> out22/1
  slice21/1 -> reinterpret21/1
  reinterpret21/1 -> out21/1
  slice20/1 -> reinterpret20/1
  reinterpret20/1 -> out20/1
  slice19/1 -> reinterpret19/1
  reinterpret19/1 -> out19/1
  slice18/1 -> reinterpret18/1
  reinterpret18/1 -> out18/1
  slice17/1 -> reinterpret17/1
  reinterpret17/1 -> out17/1
  slice16/1 -> reinterpret16/1
  reinterpret16/1 -> out16/1
  slice15/1 -> reinterpret15/1
  reinterpret15/1 -> out15/1
  slice14/1 -> reinterpret14/1
  reinterpret14/1 -> out14/1
  slice13/1 -> reinterpret13/1
  reinterpret13/1 -> out13/1
  slice12/1 -> reinterpret12/1
  reinterpret12/1 -> out12/1
  slice11/1 -> reinterpret11/1
  reinterpret11/1 -> out11/1
  slice10/1 -> reinterpret10/1
  reinterpret10/1 -> out10/1
  slice9/1 -> reinterpret9/1
  reinterpret9/1 -> out9/1
  slice8/1 -> reinterpret8/1
  reinterpret8/1 -> out8/1
  slice7/1 -> reinterpret7/1
  reinterpret7/1 -> out7/1
  slice6/1 -> reinterpret6/1
  reinterpret6/1 -> out6/1
  slice5/1 -> reinterpret5/1
  reinterpret5/1 -> out5/1
  slice4/1 -> reinterpret4/1
  reinterpret4/1 -> out4/1
  slice3/1 -> reinterpret3/1
  reinterpret3/1 -> out3/1
  slice2/1 -> reinterpret2/1
  reinterpret2/1 -> out2/1
  slice1/1 -> reinterpret1/1
  reinterpret1/1 -> lsb_out1/1

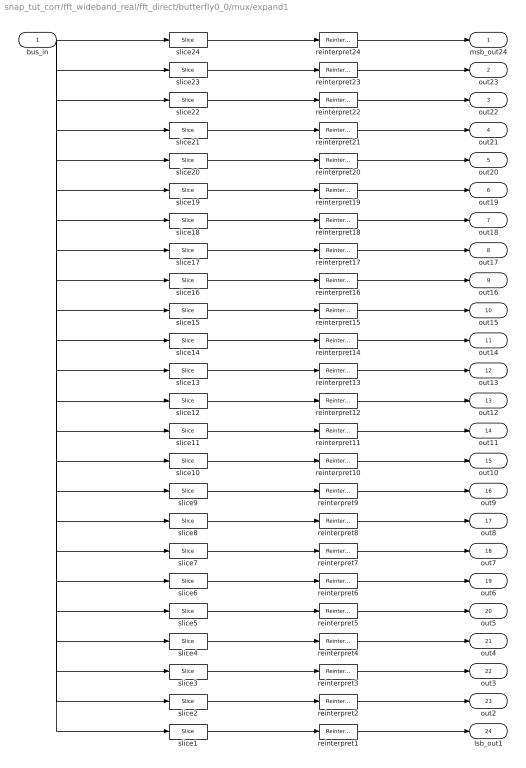
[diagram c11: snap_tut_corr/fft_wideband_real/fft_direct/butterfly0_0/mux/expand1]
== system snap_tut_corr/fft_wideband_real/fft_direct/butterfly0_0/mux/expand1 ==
  bus_in : Inport
  reinterpret{1..24} (24 alike) : xbsIndex_r4/Reinterpret  force_arith_type=on  arith_type=Unsigned  force_bin_pt=on  bin_pt=0  block_type=reinterpret
  slice1 : xbsIndex_r4/Slice  nbits=21  boolean_output=off  mode=Upper Bit Location + Width  bit1=-483  base1=MSB of Input  bit0=0  base0=LSB of Input  dbl_ovrd=off  block_type=slice
  slice10 : xbsIndex_r4/Slice  nbits=21  boolean_output=off  mode=Upper Bit Location + Width  bit1=-294  base1=MSB of Input  bit0=0  base0=LSB of Input  dbl_ovrd=off  block_type=slice
  slice11 : xbsIndex_r4/Slice  nbits=21  boolean_output=off  mode=Upper Bit Location + Width  bit1=-273  base1=MSB of Input  bit0=0  base0=LSB of Input  dbl_ovrd=off  block_type=slice
  slice12 : xbsIndex_r4/Slice  nbits=21  boolean_output=off  mode=Upper Bit Location + Width  bit1=-252  base1=MSB of Input  bit0=0  base0=LSB of Input  dbl_ovrd=off  block_type=slice
  slice13 : xbsIndex_r4/Slice  nbits=21  boolean_output=off  mode=Upper Bit Location + Width  bit1=-231  base1=MSB of Input  bit0=0  base0=LSB of Input  dbl_ovrd=off  block_type=slice
  slice14 : xbsIndex_r4/Slice  nbits=21  boolean_output=off  mode=Upper Bit Location + Width  bit1=-210  base1=MSB of Input  bit0=0  base0=LSB of Input  dbl_ovrd=off  block_type=slice
  slice15 : xbsIndex_r4/Slice  nbits=21  boolean_output=off  mode=Upper Bit Location + Width  bit1=-189  base1=MSB of Input  bit0=0  base0=LSB of Input  dbl_ovrd=off  block_type=slice
  slice16 : xbsIndex_r4/Slice  nbits=21  boolean_output=off  mode=Upper Bit Location + Width  bit1=-168  base1=MSB of Input  bit0=0  base0=LSB of Input  dbl_ovrd=off  block_type=slice
  slice17 : xbsIndex_r4/Slice  nbits=21  boolean_output=off  mode=Upper Bit Location + Width  bit1=-147  base1=MSB of Input  bit0=0  base0=LSB of Input  dbl_ovrd=off  block_type=slice
  slice18 : xbsIndex_r4/Slice  nbits=21  boolean_output=off  mode=Upper Bit Location + Width  bit1=-126  base1=MSB of Input  bit0=0  base0=LSB of Input  dbl_ovrd=off  block_type=slice
  slice19 : xbsIndex_r4/Slice  nbits=21  boolean_output=off  mode=Upper Bit Location + Width  bit1=-105  base1=MSB of Input  bit0=0  base0=LSB of Input  dbl_ovrd=off  block_type=slice
  slice2 : xbsIndex_r4/Slice  nbits=21  boolean_output=off  mode=Upper Bit Location + Width  bit1=-462  base1=MSB of Input  bit0=0  base0=LSB of Input  dbl_ovrd=off  block_type=slice
  slice20 : xbsIndex_r4/Slice  nbits=21  boolean_output=off  mode=Upper Bit Location + Width  bit1=-84  base1=MSB of Input  bit0=0  base0=LSB of Input  dbl_ovrd=off  block_type=slice
  slice21 : xbsIndex_r4/Slice  nbits=21  boolean_output=off  mode=Upper Bit Location + Width  bit1=-63  base1=MSB of Input  bit0=0  base0=LSB of Input  dbl_ovrd=off  block_type=slice
  slice22 : xbsIndex_r4/Slice  nbits=21  boolean_output=off  mode=Upper Bit Location + Width  bit1=-42  base1=MSB of Input  bit0=0  base0=LSB of Input  dbl_ovrd=off  block_type=slice
  slice23 : xbsIndex_r4/Slice  nbits=21  boolean_output=off  mode=Upper Bit Location + Width  bit1=-21  base1=MSB of Input  bit0=0  base0=LSB of Input  dbl_ovrd=off  block_type=slice
  slice24 : xbsIndex_r4/Slice  nbits=21  boolean_output=off  mode=Upper Bit Location + Width  bit1=0  base1=MSB of Input  bit0=0  base0=LSB of Input  dbl_ovrd=off  block_type=slice
  slice3 : xbsIndex_r4/Slice  nbits=21  boolean_output=off  mode=Upper Bit Location + Width  bit1=-441  base1=MSB of Input  bit0=0  base0=LSB of Input  dbl_ovrd=off  block_type=slice
  slice4 : xbsIndex_r4/Slice  nbits=21  boolean_output=off  mode=Upper Bit Location + Width  bit1=-420  base1=MSB of Input  bit0=0  base0=LSB of Input  dbl_ovrd=off  block_type=slice
  slice5 : xbsIndex_r4/Slice  nbits=21  boolean_output=off  mode=Upper Bit Location + Width  bit1=-399  base1=MSB of Input  bit0=0  base0=LSB of Input  dbl_ovrd=off  block_type=slice
  slice6 : xbsIndex_r4/Slice  nbits=21  boolean_output=off  mode=Upper Bit Location + Width  bit1=-378  base1=MSB of Input  bit0=0  base0=LSB of Input  dbl_ovrd=off  block_type=slice
  slice7 : xbsIndex_r4/Slice  nbits=21  boolean_output=off  mode=Upper Bit Location + Width  bit1=-357  base1=MSB of Input  bit0=0  base0=LSB of Input  dbl_ovrd=off  block_type=slice
  slice8 : xbsIndex_r4/Slice  nbits=21  boolean_output=off  mode=Upper Bit Location + Width  bit1=-336  base1=MSB of Input  bit0=0  base0=LSB of Input  dbl_ovrd=off  block_type=slice
  slice9 : xbsIndex_r4/Slice  nbits=21  boolean_output=off  mode=Upper Bit Location + Width  bit1=-315  base1=MSB of Input  bit0=0  base0=LSB of Input  dbl_ovrd=off  block_type=slice
  msb_out24 : Outport
  out23 : Outport  Port=2
  out22 : Outport  Port=3
  out21 : Outport  Port=4
  out20 : Outport  Port=5
  out19 : Outport  Port=6
  out18 : Outport  Port=7
  out17 : Outport  Port=8
  out16 : Outport  Port=9
  out15 : Outport  Port=10
  out14 : Outport  Port=11
  out13 : Outport  Port=12
  out12 : Outport  Port=13
  out11 : Outport  Port=14
  out10 : Outport  Port=15
  out9 : Outport  Port=16
  out8 : Outport  Port=17
  out7 : Outport  Port=18
  out6 : Outport  Port=19
  out5 : Outport  Port=20
  out4 : Outport  Port=21
  out3 : Outport  Port=22
  out2 : Outport  Port=23
  lsb_out1 : Outport  Port=24
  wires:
  bus_in/1 -> slice24/1, slice23/1, slice22/1, slice21/1, slice20/1, slice19/1, slice18/1, slice17/1, slice16/1, slice15/1, slice14/1, slice13/1, slice12/1, slice11/1, slice10/1, slice9/1, slice8/1, slice7/1, slice6/1, slice5/1, slice4/1, slice3/1, slice2/1, slice1/1
  slice24/1 -> reinterpret24/1
  reinterpret24/1 -> msb_out24/1
  slice23/1 -> reinterpret23/1
  reinterpret23/1 -> out23/1
  slice22/1 -> reinterpret22/1
  reinterpret22/1 -> out22/1
  slice21/1 -> reinterpret21/1
  reinterpret21/1 -> out21/1
  slice20/1 -> reinterpret20/1
  reinterpret20/1 -> out20/1
  slice19/1 -> reinterpret19/1
  reinterpret19/1 -> out19/1
  slice18/1 -> reinterpret18/1
  reinterpret18/1 -> out18/1
  slice17/1 -> reinterpret17/1
  reinterpret17/1 -> out17/1
  slice16/1 -> reinterpret16/1
  reinterpret16/1 -> out16/1
  slice15/1 -> reinterpret15/1
  reinterpret15/1 -> out15/1
  slice14/1 -> reinterpret14/1
  reinterpret14/1 -> out14/1
  slice13/1 -> reinterpret13/1
  reinterpret13/1 -> out13/1
  slice12/1 -> reinterpret12/1
  reinterpret12/1 -> out12/1
  slice11/1 -> reinterpret11/1
  reinterpret11/1 -> out11/1
  slice10/1 -> reinterpret10/1
  reinterpret10/1 -> out10/1
  slice9/1 -> reinterpret9/1
  reinterpret9/1 -> out9/1
  slice8/1 -> reinterpret8/1
  reinterpret8/1 -> out8/1
  slice7/1 -> reinterpret7/1
  reinterpret7/1 -> out7/1
  slice6/1 -> reinterpret6/1
  reinterpret6/1 -> out6/1
  slice5/1 -> reinterpret5/1
  reinterpret5/1 -> out5/1
  slice4/1 -> reinterpret4/1
  reinterpret4/1 -> out4/1
  slice3/1 -> reinterpret3/1
  reinterpret3/1 -> out3/1
  slice2/1 -> reinterpret2/1
  reinterpret2/1 -> out2/1
  slice1/1 -> reinterpret1/1
  reinterpret1/1 -> lsb_out1/1

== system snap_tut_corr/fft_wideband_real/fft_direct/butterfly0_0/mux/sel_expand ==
  bus_in : Inport
  reinterpret{1..24} (24 alike) : xbsIndex_r4/Reinterpret  force_arith_type=on  arith_type=Unsigned  force_bin_pt=on  bin_pt=0  block_type=reinterpret
  slice1 : xbsIndex_r4/Slice  nbits=1  boolean_output=off  mode=Upper Bit Location + Width  bit1=-23  base1=MSB of Input  bit0=0  base0=LSB of Input  dbl_ovrd=off  block_type=slice
  slice10 : xbsIndex_r4/Slice  nbits=1  boolean_output=off  mode=Upper Bit Location + Width  bit1=-14  base1=MSB of Input  bit0=0  base0=LSB of Input  dbl_ovrd=off  block_type=slice
  slice11 : xbsIndex_r4/Slice  nbits=1  boolean_output=off  mode=Upper Bit Location + Width  bit1=-13  base1=MSB of Input  bit0=0  base0=LSB of Input  dbl_ovrd=off  block_type=slice
  slice12 : xbsIndex_r4/Slice  nbits=1  boolean_output=off  mode=Upper Bit Location + Width  bit1=-12  base1=MSB of Input  bit0=0  base0=LSB of Input  dbl_ovrd=off  block_type=slice
  slice13 : xbsIndex_r4/Slice  nbits=1  boolean_output=off  mode=Upper Bit Location + Width  bit1=-11  base1=MSB of Input  bit0=0  base0=LSB of Input  dbl_ovrd=off  block_type=slice
  slice14 : xbsIndex_r4/Slice  nbits=1  boolean_output=off  mode=Upper Bit Location + Width  bit1=-10  base1=MSB of Input  bit0=0  base0=LSB of Input  dbl_ovrd=off  block_type=slice
  slice15 : xbsIndex_r4/Slice  nbits=1  boolean_output=off  mode=Upper Bit Location + Width  bit1=-9  base1=MSB of Input  bit0=0  base0=LSB of Input  dbl_ovrd=off  block_type=slice
  slice16 : xbsIndex_r4/Slice  nbits=1  boolean_output=off  mode=Upper Bit Location + Width  bit1=-8  base1=MSB of Input  bit0=0  base0=LSB of Input  dbl_ovrd=off  block_type=slice
  slice17 : xbsIndex_r4/Slice  nbits=1  boolean_output=off  mode=Upper Bit Location + Width  bit1=-7  base1=MSB of Input  bit0=0  base0=LSB of Input  dbl_ovrd=off  block_type=slice
  slice18 : xbsIndex_r4/Slice  nbits=1  boolean_output=off  mode=Upper Bit Location + Width  bit1=-6  base1=MSB of Input  bit0=0  base0=LSB of Input  dbl_ovrd=off  block_type=slice
  slice19 : xbsIndex_r4/Slice  nbits=1  boolean_output=off  mode=Upper Bit Location + Width  bit1=-5  base1=MSB of Input  bit0=0  base0=LSB of Input  dbl_ovrd=off  block_type=slice
  slice2 : xbsIndex_r4/Slice  nbits=1  boolean_output=off  mode=Upper Bit Location + Width  bit1=-22  base1=MSB of Input  bit0=0  base0=LSB of Input  dbl_ovrd=off  block_type=slice
  slice20 : xbsIndex_r4/Slice  nbits=1  boolean_output=off  mode=Upper Bit Location + Width  bit1=-4  base1=MSB of Input  bit0=0  base0=LSB of Input  dbl_ovrd=off  block_type=slice
  slice21 : xbsIndex_r4/Slice  nbits=1  boolean_output=off  mode=Upper Bit Location + Width  bit1=-3  base1=MSB of Input  bit0=0  base0=LSB of Input  dbl_ovrd=off  block_type=slice
  slice22 : xbsIndex_r4/Slice  nbits=1  boolean_output=off  mode=Upper Bit Location + Width  bit1=-2  base1=MSB of Input  bit0=0  base0=LSB of Input  dbl_ovrd=off  block_type=slice
  slice23 : xbsIndex_r4/Slice  nbits=1  boolean_output=off  mode=Upper Bit Location + Width  bit1=-1  base1=MSB of Input  bit0=0  base0=LSB of Input  dbl_ovrd=off  block_type=slice
  slice24 : xbsIndex_r4/Slice  nbits=1  boolean_output=off  mode=Upper Bit Location + Width  bit1=0  base1=MSB of Input  bit0=0  base0=LSB of Input  dbl_ovrd=off  block_type=slice
  slice3 : xbsIndex_r4/Slice  nbits=1  boolean_output=off  mode=Upper Bit Location + Width  bit1=-21  base1=MSB of Input  bit0=0  base0=LSB of Input  dbl_ovrd=off  block_type=slice
  slice4 : xbsIndex_r4/Slice  nbits=1  boolean_output=off  mode=Upper Bit Location + Width  bit1=-20  base1=MSB of Input  bit0=0  base0=LSB of Input  dbl_ovrd=off  block_type=slice
  slice5 : xbsIndex_r4/Slice  nbits=1  boolean_output=off  mode=Upper Bit Location + Width  bit1=-19  base1=MSB of Input  bit0=0  base0=LSB of Input  dbl_ovrd=off  block_type=slice
  slice6 : xbsIndex_r4/Slice  nbits=1  boolean_output=off  mode=Upper Bit Location + Width  bit1=-18  base1=MSB of Input  bit0=0  base0=LSB of Input  dbl_ovrd=off  block_type=slice
  slice7 : xbsIndex_r4/Slice  nbits=1  boolean_output=off  mode=Upper Bit Location + Width  bit1=-17  base1=MSB of Input  bit0=0  base0=LSB of Input  dbl_ovrd=off  block_type=slice
  slice8 : xbsIndex_r4/Slice  nbits=1  boolean_output=off  mode=Upper Bit Location + Width  bit1=-16  base1=MSB of Input  bit0=0  base0=LSB of Input  dbl_ovrd=off  block_type=slice
  slice9 : xbsIndex_r4/Slice  nbits=1  boolean_output=off  mode=Upper Bit Location + Width  bit1=-15  base1=MSB of Input  bit0=0  base0=LSB of Input  dbl_ovrd=off  block_type=slice
  msb_out24 : Outport
  out23 : Outport  Port=2
  out22 : Outport  Port=3
  out21 : Outport  Port=4
  out20 : Outport  Port=5
  out19 : Outport  Port=6
  out18 : Outport  Port=7
  out17 : Outport  Port=8
  out16 : Outport  Port=9
  out15 : Outport  Port=10
  out14 : Outport  Port=11
  out13 : Outport  Port=12
  out12 : Outport  Port=13
  out11 : Outport  Port=14
  out10 : Outport  Port=15
  out9 : Outport  Port=16
  out8 : Outport  Port=17
  out7 : Outport  Port=18
  out6 : Outport  Port=19
  out5 : Outport  Port=20
  out4 : Outport  Port=21
  out3 : Outport  Port=22
  out2 : Outport  Port=23
  lsb_out1 : Outport  Port=24
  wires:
  bus_in/1 -> slice24/1, slice23/1, slice22/1, slice21/1, slice20/1, slice19/1, slice18/1, slice17/1, slice16/1, slice15/1, slice14/1, slice13/1, slice12/1, slice11/1, slice10/1, slice9/1, slice8/1, slice7/1, slice6/1, slice5/1, slice4/1, slice3/1, slice2/1, slice1/1
  slice24/1 -> reinterpret24/1
  reinterpret24/1 -> msb_out24/1
  slice23/1 -> reinterpret23/1
  reinterpret23/1 -> out23/1
  slice22/1 -> reinterpret22/1
  reinterpret22/1 -> out22/1
  slice21/1 -> reinterpret21/1
  reinterpret21/1 -> out21/1
  slice20/1 -> reinterpret20/1
  reinterpret20/1 -> out20/1
  slice19/1 -> reinterpret19/1
  reinterpret19/1 -> out19/1
  slice18/1 -> reinterpret18/1
  reinterpret18/1 -> out18/1
  slice17/1 -> reinterpret17/1
  reinterpret17/1 -> out17/1
  slice16/1 -> reinterpret16/1
  reinterpret16/1 -> out16/1
  slice15/1 -> reinterpret15/1
  reinterpret15/1 -> out15/1
  slice14/1 -> reinterpret14/1
  reinterpret14/1 -> out14/1
  slice13/1 -> reinterpret13/1
  reinterpret13/1 -> out13/1
  slice12/1 -> reinterpret12/1
  reinterpret12/1 -> out12/1
  slice11/1 -> reinterpret11/1
  reinterpret11/1 -> out11/1
  slice10/1 -> reinterpret10/1
  reinterpret10/1 -> out10/1
  slice9/1 -> reinterpret9/1
  reinterpret9/1 -> out9/1
  slice8/1 -> reinterpret8/1
  reinterpret8/1 -> out8/1
  slice7/1 -> reinterpret7/1
  reinterpret7/1 -> out7/1
  slice6/1 -> reinterpret6/1
  reinterpret6/1 -> out6/1
  slice5/1 -> reinterpret5/1
  reinterpret5/1 -> out5/1
  slice4/1 -> reinterpret4/1
  reinterpret4/1 -> out4/1
  slice3/1 -> reinterpret3/1
  reinterpret3/1 -> out3/1
  slice2/1 -> reinterpret2/1
  reinterpret2/1 -> out2/1
  slice1/1 -> reinterpret1/1
  reinterpret1/1 -> lsb_out1/1

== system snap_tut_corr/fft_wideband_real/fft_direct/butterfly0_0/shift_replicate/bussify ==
  in1 : Inport
  in2 : Inport  Port=2
  in3 : Inport  Port=3
  in4 : Inport  Port=4
  in5 : Inport  Port=5
  in6 : Inport  Port=6
  in7 : Inport  Port=7
  in8 : Inport  Port=8
  in9 : Inport  Port=9
  in10 : Inport  Port=10
  in11 : Inport  Port=11
  in12 : Inport  Port=12
  in13 : Inport  Port=13
  in14 : Inport  Port=14
  in15 : Inport  Port=15
  in16 : Inport  Port=16
  in17 : Inport  Port=17
  in18 : Inport  Port=18
  in19 : Inport  Port=19
  in20 : Inport  Port=20
  in21 : Inport  Port=21
  in22 : Inport  Port=22
  in23 : Inport  Port=23
  in24 : Inport  Port=24
  concatenate : xbsIndex_r4/Concat  num_inputs=24  dbl_ovrd=off  block_type=concat
  reinterpret{1..24} (24 alike) : xbsIndex_r4/Reinterpret  force_arith_type=on  arith_type=Unsigned  force_bin_pt=on  bin_pt=0  block_type=reinterpret
  bus_out : Outport
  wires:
  concatenate/1 -> bus_out/1
  in1/1 -> reinterpret1/1
  reinterpret1/1 -> concatenate/1
  in2/1 -> reinterpret2/1
  reinterpret2/1 -> concatenate/2
  in3/1 -> reinterpret3/1
  reinterpret3/1 -> concatenate/3
  in4/1 -> reinterpret4/1
  reinterpret4/1 -> concatenate/4
  in5/1 -> reinterpret5/1
  reinterpret5/1 -> concatenate/5
  in6/1 -> reinterpret6/1
  reinterpret6/1 -> concatenate/6
  in7/1 -> reinterpret7/1
  reinterpret7/1 -> concatenate/7
  in8/1 -> reinterpret8/1
  reinterpret8/1 -> concatenate/8
  in9/1 -> reinterpret9/1
  reinterpret9/1 -> concatenate/9
  in10/1 -> reinterpret10/1
  reinterpret10/1 -> concatenate/10
  in11/1 -> reinterpret11/1
  reinterpret11/1 -> concatenate/11
  in12/1 -> reinterpret12/1
  reinterpret12/1 -> concatenate/12
  in13/1 -> reinterpret13/1
  reinterpret13/1 -> concatenate/13
  in14/1 -> reinterpret14/1
  reinterpret14/1 -> concatenate/14
  in15/1 -> reinterpret15/1
  reinterpret15/1 -> concatenate/15
  in16/1 -> reinterpret16/1
  reinterpret16/1 -> concatenate/16
  in17/1 -> reinterpret17/1
  reinterpret17/1 -> concatenate/17
  in18/1 -> reinterpret18/1
  reinterpret18/1 -> concatenate/18
  in19/1 -> reinterpret19/1
  reinterpret19/1 -> concatenate/19
  in20/1 -> reinterpret20/1
  reinterpret20/1 -> concatenate/20
  in21/1 -> reinterpret21/1
  reinterpret21/1 -> concatenate/21
  in22/1 -> reinterpret22/1
  reinterpret22/1 -> concatenate/22
  in23/1 -> reinterpret23/1
  reinterpret23/1 -> concatenate/23
  in24/1 -> reinterpret24/1
  reinterpret24/1 -> concatenate/24
